VERSION 5.8 ;
BUSBITCHARS "[]" ;
DIVIDERCHAR "/" ;
UNITS
    DATABASE MICRONS 1000 ;
END UNITS

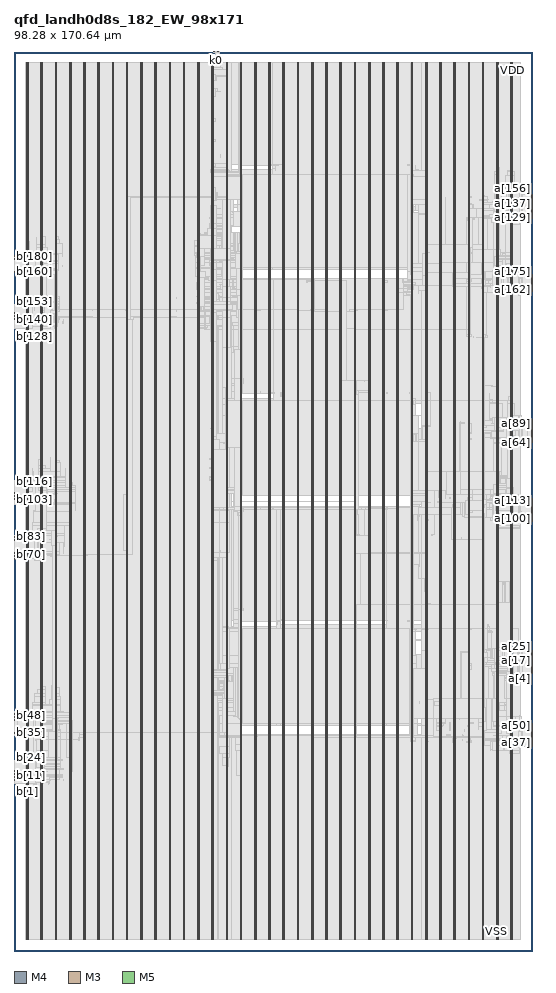
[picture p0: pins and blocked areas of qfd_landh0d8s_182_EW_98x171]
MACRO qfd_landh0d8s_182_EW_98x171
  FOREIGN qfd_landh0d8s_182_EW_98x171 0 0 ;
  CLASS BLOCK ;
  SIZE 98.28 BY 170.64 ;
  PIN a[0]
    DIRECTION INPUT ;
    USE SIGNAL ;
    PORT
      LAYER M4 ;
        RECT  98.196 52.56 98.28 52.584 ;
    END
  END a[0]
  PIN a[100]
    DIRECTION INPUT ;
    USE SIGNAL ;
    PORT
      LAYER M4 ;
        RECT  98.196 81.936 98.28 81.96 ;
    END
  END a[100]
  PIN a[101]
    DIRECTION INPUT ;
    USE SIGNAL ;
    PORT
      LAYER M4 ;
        RECT  98.196 82.08 98.28 82.104 ;
    END
  END a[101]
  PIN a[102]
    DIRECTION INPUT ;
    USE SIGNAL ;
    PORT
      LAYER M4 ;
        RECT  98.196 82.224 98.28 82.248 ;
    END
  END a[102]
  PIN a[103]
    DIRECTION INPUT ;
    USE SIGNAL ;
    PORT
      LAYER M4 ;
        RECT  98.196 82.368 98.28 82.392 ;
    END
  END a[103]
  PIN a[104]
    DIRECTION INPUT ;
    USE SIGNAL ;
    PORT
      LAYER M4 ;
        RECT  98.196 82.512 98.28 82.536 ;
    END
  END a[104]
  PIN a[105]
    DIRECTION INPUT ;
    USE SIGNAL ;
    PORT
      LAYER M4 ;
        RECT  98.196 82.656 98.28 82.68 ;
    END
  END a[105]
  PIN a[106]
    DIRECTION INPUT ;
    USE SIGNAL ;
    PORT
      LAYER M4 ;
        RECT  98.196 82.8 98.28 82.824 ;
    END
  END a[106]
  PIN a[107]
    DIRECTION INPUT ;
    USE SIGNAL ;
    PORT
      LAYER M4 ;
        RECT  98.196 82.944 98.28 82.968 ;
    END
  END a[107]
  PIN a[108]
    DIRECTION INPUT ;
    USE SIGNAL ;
    PORT
      LAYER M4 ;
        RECT  98.196 83.088 98.28 83.112 ;
    END
  END a[108]
  PIN a[109]
    DIRECTION INPUT ;
    USE SIGNAL ;
    PORT
      LAYER M4 ;
        RECT  98.196 83.232 98.28 83.256 ;
    END
  END a[109]
  PIN a[10]
    DIRECTION INPUT ;
    USE SIGNAL ;
    PORT
      LAYER M4 ;
        RECT  98.196 54 98.28 54.024 ;
    END
  END a[10]
  PIN a[110]
    DIRECTION INPUT ;
    USE SIGNAL ;
    PORT
      LAYER M4 ;
        RECT  98.196 83.376 98.28 83.4 ;
    END
  END a[110]
  PIN a[111]
    DIRECTION INPUT ;
    USE SIGNAL ;
    PORT
      LAYER M4 ;
        RECT  98.196 83.52 98.28 83.544 ;
    END
  END a[111]
  PIN a[112]
    DIRECTION INPUT ;
    USE SIGNAL ;
    PORT
      LAYER M4 ;
        RECT  98.196 83.664 98.28 83.688 ;
    END
  END a[112]
  PIN a[113]
    DIRECTION INPUT ;
    USE SIGNAL ;
    PORT
      LAYER M4 ;
        RECT  98.196 83.808 98.28 83.832 ;
    END
  END a[113]
  PIN a[114]
    DIRECTION INPUT ;
    USE SIGNAL ;
    PORT
      LAYER M4 ;
        RECT  98.196 83.952 98.28 83.976 ;
    END
  END a[114]
  PIN a[115]
    DIRECTION INPUT ;
    USE SIGNAL ;
    PORT
      LAYER M4 ;
        RECT  98.196 84.096 98.28 84.12 ;
    END
  END a[115]
  PIN a[116]
    DIRECTION INPUT ;
    USE SIGNAL ;
    PORT
      LAYER M4 ;
        RECT  98.196 84.24 98.28 84.264 ;
    END
  END a[116]
  PIN a[117]
    DIRECTION INPUT ;
    USE SIGNAL ;
    PORT
      LAYER M4 ;
        RECT  98.196 84.384 98.28 84.408 ;
    END
  END a[117]
  PIN a[118]
    DIRECTION INPUT ;
    USE SIGNAL ;
    PORT
      LAYER M4 ;
        RECT  98.196 84.528 98.28 84.552 ;
    END
  END a[118]
  PIN a[119]
    DIRECTION INPUT ;
    USE SIGNAL ;
    PORT
      LAYER M4 ;
        RECT  98.196 84.672 98.28 84.696 ;
    END
  END a[119]
  PIN a[11]
    DIRECTION INPUT ;
    USE SIGNAL ;
    PORT
      LAYER M4 ;
        RECT  98.196 54.144 98.28 54.168 ;
    END
  END a[11]
  PIN a[120]
    DIRECTION INPUT ;
    USE SIGNAL ;
    PORT
      LAYER M4 ;
        RECT  98.196 84.816 98.28 84.84 ;
    END
  END a[120]
  PIN a[121]
    DIRECTION INPUT ;
    USE SIGNAL ;
    PORT
      LAYER M4 ;
        RECT  98.196 84.96 98.28 84.984 ;
    END
  END a[121]
  PIN a[122]
    DIRECTION INPUT ;
    USE SIGNAL ;
    PORT
      LAYER M4 ;
        RECT  98.196 85.104 98.28 85.128 ;
    END
  END a[122]
  PIN a[123]
    DIRECTION INPUT ;
    USE SIGNAL ;
    PORT
      LAYER M4 ;
        RECT  98.196 85.248 98.28 85.272 ;
    END
  END a[123]
  PIN a[124]
    DIRECTION INPUT ;
    USE SIGNAL ;
    PORT
      LAYER M4 ;
        RECT  98.196 85.392 98.28 85.416 ;
    END
  END a[124]
  PIN a[125]
    DIRECTION INPUT ;
    USE SIGNAL ;
    PORT
      LAYER M4 ;
        RECT  98.196 85.536 98.28 85.56 ;
    END
  END a[125]
  PIN a[126]
    DIRECTION INPUT ;
    USE SIGNAL ;
    PORT
      LAYER M4 ;
        RECT  98.196 85.68 98.28 85.704 ;
    END
  END a[126]
  PIN a[127]
    DIRECTION INPUT ;
    USE SIGNAL ;
    PORT
      LAYER M4 ;
        RECT  98.196 85.824 98.28 85.848 ;
    END
  END a[127]
  PIN a[128]
    DIRECTION INPUT ;
    USE SIGNAL ;
    PORT
      LAYER M4 ;
        RECT  98.196 138.96 98.28 138.984 ;
    END
  END a[128]
  PIN a[129]
    DIRECTION INPUT ;
    USE SIGNAL ;
    PORT
      LAYER M4 ;
        RECT  98.196 139.104 98.28 139.128 ;
    END
  END a[129]
  PIN a[12]
    DIRECTION INPUT ;
    USE SIGNAL ;
    PORT
      LAYER M4 ;
        RECT  98.196 54.288 98.28 54.312 ;
    END
  END a[12]
  PIN a[130]
    DIRECTION INPUT ;
    USE SIGNAL ;
    PORT
      LAYER M4 ;
        RECT  98.196 139.248 98.28 139.272 ;
    END
  END a[130]
  PIN a[131]
    DIRECTION INPUT ;
    USE SIGNAL ;
    PORT
      LAYER M4 ;
        RECT  98.196 139.392 98.28 139.416 ;
    END
  END a[131]
  PIN a[132]
    DIRECTION INPUT ;
    USE SIGNAL ;
    PORT
      LAYER M4 ;
        RECT  98.196 139.536 98.28 139.56 ;
    END
  END a[132]
  PIN a[133]
    DIRECTION INPUT ;
    USE SIGNAL ;
    PORT
      LAYER M4 ;
        RECT  98.196 139.68 98.28 139.704 ;
    END
  END a[133]
  PIN a[134]
    DIRECTION INPUT ;
    USE SIGNAL ;
    PORT
      LAYER M4 ;
        RECT  98.196 139.824 98.28 139.848 ;
    END
  END a[134]
  PIN a[135]
    DIRECTION INPUT ;
    USE SIGNAL ;
    PORT
      LAYER M4 ;
        RECT  98.196 139.968 98.28 139.992 ;
    END
  END a[135]
  PIN a[136]
    DIRECTION INPUT ;
    USE SIGNAL ;
    PORT
      LAYER M4 ;
        RECT  98.196 140.112 98.28 140.136 ;
    END
  END a[136]
  PIN a[137]
    DIRECTION INPUT ;
    USE SIGNAL ;
    PORT
      LAYER M4 ;
        RECT  98.196 140.256 98.28 140.28 ;
    END
  END a[137]
  PIN a[138]
    DIRECTION INPUT ;
    USE SIGNAL ;
    PORT
      LAYER M4 ;
        RECT  98.196 140.4 98.28 140.424 ;
    END
  END a[138]
  PIN a[139]
    DIRECTION INPUT ;
    USE SIGNAL ;
    PORT
      LAYER M4 ;
        RECT  98.196 140.544 98.28 140.568 ;
    END
  END a[139]
  PIN a[13]
    DIRECTION INPUT ;
    USE SIGNAL ;
    PORT
      LAYER M4 ;
        RECT  98.196 54.432 98.28 54.456 ;
    END
  END a[13]
  PIN a[140]
    DIRECTION INPUT ;
    USE SIGNAL ;
    PORT
      LAYER M4 ;
        RECT  98.196 140.688 98.28 140.712 ;
    END
  END a[140]
  PIN a[141]
    DIRECTION INPUT ;
    USE SIGNAL ;
    PORT
      LAYER M4 ;
        RECT  98.196 140.832 98.28 140.856 ;
    END
  END a[141]
  PIN a[142]
    DIRECTION INPUT ;
    USE SIGNAL ;
    PORT
      LAYER M4 ;
        RECT  98.196 140.976 98.28 141 ;
    END
  END a[142]
  PIN a[143]
    DIRECTION INPUT ;
    USE SIGNAL ;
    PORT
      LAYER M4 ;
        RECT  98.196 141.12 98.28 141.144 ;
    END
  END a[143]
  PIN a[144]
    DIRECTION INPUT ;
    USE SIGNAL ;
    PORT
      LAYER M4 ;
        RECT  98.196 141.264 98.28 141.288 ;
    END
  END a[144]
  PIN a[145]
    DIRECTION INPUT ;
    USE SIGNAL ;
    PORT
      LAYER M4 ;
        RECT  98.196 141.408 98.28 141.432 ;
    END
  END a[145]
  PIN a[146]
    DIRECTION INPUT ;
    USE SIGNAL ;
    PORT
      LAYER M4 ;
        RECT  98.196 141.552 98.28 141.576 ;
    END
  END a[146]
  PIN a[147]
    DIRECTION INPUT ;
    USE SIGNAL ;
    PORT
      LAYER M4 ;
        RECT  98.196 141.696 98.28 141.72 ;
    END
  END a[147]
  PIN a[148]
    DIRECTION INPUT ;
    USE SIGNAL ;
    PORT
      LAYER M4 ;
        RECT  98.196 141.84 98.28 141.864 ;
    END
  END a[148]
  PIN a[149]
    DIRECTION INPUT ;
    USE SIGNAL ;
    PORT
      LAYER M4 ;
        RECT  98.196 141.984 98.28 142.008 ;
    END
  END a[149]
  PIN a[14]
    DIRECTION INPUT ;
    USE SIGNAL ;
    PORT
      LAYER M4 ;
        RECT  98.196 54.576 98.28 54.6 ;
    END
  END a[14]
  PIN a[150]
    DIRECTION INPUT ;
    USE SIGNAL ;
    PORT
      LAYER M4 ;
        RECT  98.196 142.128 98.28 142.152 ;
    END
  END a[150]
  PIN a[151]
    DIRECTION INPUT ;
    USE SIGNAL ;
    PORT
      LAYER M4 ;
        RECT  98.196 142.272 98.28 142.296 ;
    END
  END a[151]
  PIN a[152]
    DIRECTION INPUT ;
    USE SIGNAL ;
    PORT
      LAYER M4 ;
        RECT  98.196 142.416 98.28 142.44 ;
    END
  END a[152]
  PIN a[153]
    DIRECTION INPUT ;
    USE SIGNAL ;
    PORT
      LAYER M4 ;
        RECT  98.196 142.56 98.28 142.584 ;
    END
  END a[153]
  PIN a[154]
    DIRECTION INPUT ;
    USE SIGNAL ;
    PORT
      LAYER M4 ;
        RECT  98.196 142.704 98.28 142.728 ;
    END
  END a[154]
  PIN a[155]
    DIRECTION INPUT ;
    USE SIGNAL ;
    PORT
      LAYER M4 ;
        RECT  98.196 142.848 98.28 142.872 ;
    END
  END a[155]
  PIN a[156]
    DIRECTION INPUT ;
    USE SIGNAL ;
    PORT
      LAYER M4 ;
        RECT  98.196 142.992 98.28 143.016 ;
    END
  END a[156]
  PIN a[157]
    DIRECTION INPUT ;
    USE SIGNAL ;
    PORT
      LAYER M4 ;
        RECT  98.196 143.136 98.28 143.16 ;
    END
  END a[157]
  PIN a[158]
    DIRECTION INPUT ;
    USE SIGNAL ;
    PORT
      LAYER M4 ;
        RECT  98.196 143.28 98.28 143.304 ;
    END
  END a[158]
  PIN a[159]
    DIRECTION INPUT ;
    USE SIGNAL ;
    PORT
      LAYER M4 ;
        RECT  98.196 143.424 98.28 143.448 ;
    END
  END a[159]
  PIN a[15]
    DIRECTION INPUT ;
    USE SIGNAL ;
    PORT
      LAYER M4 ;
        RECT  98.196 54.72 98.28 54.744 ;
    END
  END a[15]
  PIN a[160]
    DIRECTION INPUT ;
    USE SIGNAL ;
    PORT
      LAYER M4 ;
        RECT  98.196 125.136 98.28 125.16 ;
    END
  END a[160]
  PIN a[161]
    DIRECTION INPUT ;
    USE SIGNAL ;
    PORT
      LAYER M4 ;
        RECT  98.196 125.28 98.28 125.304 ;
    END
  END a[161]
  PIN a[162]
    DIRECTION INPUT ;
    USE SIGNAL ;
    PORT
      LAYER M4 ;
        RECT  98.196 125.424 98.28 125.448 ;
    END
  END a[162]
  PIN a[163]
    DIRECTION INPUT ;
    USE SIGNAL ;
    PORT
      LAYER M4 ;
        RECT  98.196 125.568 98.28 125.592 ;
    END
  END a[163]
  PIN a[164]
    DIRECTION INPUT ;
    USE SIGNAL ;
    PORT
      LAYER M4 ;
        RECT  98.196 125.712 98.28 125.736 ;
    END
  END a[164]
  PIN a[165]
    DIRECTION INPUT ;
    USE SIGNAL ;
    PORT
      LAYER M4 ;
        RECT  98.196 125.856 98.28 125.88 ;
    END
  END a[165]
  PIN a[166]
    DIRECTION INPUT ;
    USE SIGNAL ;
    PORT
      LAYER M4 ;
        RECT  98.196 126 98.28 126.024 ;
    END
  END a[166]
  PIN a[167]
    DIRECTION INPUT ;
    USE SIGNAL ;
    PORT
      LAYER M4 ;
        RECT  98.196 126.144 98.28 126.168 ;
    END
  END a[167]
  PIN a[168]
    DIRECTION INPUT ;
    USE SIGNAL ;
    PORT
      LAYER M4 ;
        RECT  98.196 126.288 98.28 126.312 ;
    END
  END a[168]
  PIN a[169]
    DIRECTION INPUT ;
    USE SIGNAL ;
    PORT
      LAYER M4 ;
        RECT  98.196 126.432 98.28 126.456 ;
    END
  END a[169]
  PIN a[16]
    DIRECTION INPUT ;
    USE SIGNAL ;
    PORT
      LAYER M4 ;
        RECT  98.196 54.864 98.28 54.888 ;
    END
  END a[16]
  PIN a[170]
    DIRECTION INPUT ;
    USE SIGNAL ;
    PORT
      LAYER M4 ;
        RECT  98.196 126.576 98.28 126.6 ;
    END
  END a[170]
  PIN a[171]
    DIRECTION INPUT ;
    USE SIGNAL ;
    PORT
      LAYER M4 ;
        RECT  98.196 126.72 98.28 126.744 ;
    END
  END a[171]
  PIN a[172]
    DIRECTION INPUT ;
    USE SIGNAL ;
    PORT
      LAYER M4 ;
        RECT  98.196 126.864 98.28 126.888 ;
    END
  END a[172]
  PIN a[173]
    DIRECTION INPUT ;
    USE SIGNAL ;
    PORT
      LAYER M4 ;
        RECT  98.196 127.008 98.28 127.032 ;
    END
  END a[173]
  PIN a[174]
    DIRECTION INPUT ;
    USE SIGNAL ;
    PORT
      LAYER M4 ;
        RECT  98.196 127.152 98.28 127.176 ;
    END
  END a[174]
  PIN a[175]
    DIRECTION INPUT ;
    USE SIGNAL ;
    PORT
      LAYER M4 ;
        RECT  98.196 127.296 98.28 127.32 ;
    END
  END a[175]
  PIN a[176]
    DIRECTION INPUT ;
    USE SIGNAL ;
    PORT
      LAYER M4 ;
        RECT  98.196 127.44 98.28 127.464 ;
    END
  END a[176]
  PIN a[177]
    DIRECTION INPUT ;
    USE SIGNAL ;
    PORT
      LAYER M4 ;
        RECT  98.196 127.584 98.28 127.608 ;
    END
  END a[177]
  PIN a[178]
    DIRECTION INPUT ;
    USE SIGNAL ;
    PORT
      LAYER M4 ;
        RECT  98.196 127.728 98.28 127.752 ;
    END
  END a[178]
  PIN a[179]
    DIRECTION INPUT ;
    USE SIGNAL ;
    PORT
      LAYER M4 ;
        RECT  98.196 127.872 98.28 127.896 ;
    END
  END a[179]
  PIN a[17]
    DIRECTION INPUT ;
    USE SIGNAL ;
    PORT
      LAYER M4 ;
        RECT  98.196 55.008 98.28 55.032 ;
    END
  END a[17]
  PIN a[180]
    DIRECTION INPUT ;
    USE SIGNAL ;
    PORT
      LAYER M4 ;
        RECT  98.196 128.016 98.28 128.04 ;
    END
  END a[180]
  PIN a[181]
    DIRECTION INPUT ;
    USE SIGNAL ;
    PORT
      LAYER M4 ;
        RECT  98.196 128.16 98.28 128.184 ;
    END
  END a[181]
  PIN a[18]
    DIRECTION INPUT ;
    USE SIGNAL ;
    PORT
      LAYER M4 ;
        RECT  98.196 55.152 98.28 55.176 ;
    END
  END a[18]
  PIN a[19]
    DIRECTION INPUT ;
    USE SIGNAL ;
    PORT
      LAYER M4 ;
        RECT  98.196 55.296 98.28 55.32 ;
    END
  END a[19]
  PIN a[1]
    DIRECTION INPUT ;
    USE SIGNAL ;
    PORT
      LAYER M4 ;
        RECT  98.196 52.704 98.28 52.728 ;
    END
  END a[1]
  PIN a[20]
    DIRECTION INPUT ;
    USE SIGNAL ;
    PORT
      LAYER M4 ;
        RECT  98.196 55.44 98.28 55.464 ;
    END
  END a[20]
  PIN a[21]
    DIRECTION INPUT ;
    USE SIGNAL ;
    PORT
      LAYER M4 ;
        RECT  98.196 55.584 98.28 55.608 ;
    END
  END a[21]
  PIN a[22]
    DIRECTION INPUT ;
    USE SIGNAL ;
    PORT
      LAYER M4 ;
        RECT  98.196 55.728 98.28 55.752 ;
    END
  END a[22]
  PIN a[23]
    DIRECTION INPUT ;
    USE SIGNAL ;
    PORT
      LAYER M4 ;
        RECT  98.196 55.872 98.28 55.896 ;
    END
  END a[23]
  PIN a[24]
    DIRECTION INPUT ;
    USE SIGNAL ;
    PORT
      LAYER M4 ;
        RECT  98.196 56.016 98.28 56.04 ;
    END
  END a[24]
  PIN a[25]
    DIRECTION INPUT ;
    USE SIGNAL ;
    PORT
      LAYER M4 ;
        RECT  98.196 56.16 98.28 56.184 ;
    END
  END a[25]
  PIN a[26]
    DIRECTION INPUT ;
    USE SIGNAL ;
    PORT
      LAYER M4 ;
        RECT  98.196 56.304 98.28 56.328 ;
    END
  END a[26]
  PIN a[27]
    DIRECTION INPUT ;
    USE SIGNAL ;
    PORT
      LAYER M4 ;
        RECT  98.196 56.448 98.28 56.472 ;
    END
  END a[27]
  PIN a[28]
    DIRECTION INPUT ;
    USE SIGNAL ;
    PORT
      LAYER M4 ;
        RECT  98.196 56.592 98.28 56.616 ;
    END
  END a[28]
  PIN a[29]
    DIRECTION INPUT ;
    USE SIGNAL ;
    PORT
      LAYER M4 ;
        RECT  98.196 56.736 98.28 56.76 ;
    END
  END a[29]
  PIN a[2]
    DIRECTION INPUT ;
    USE SIGNAL ;
    PORT
      LAYER M4 ;
        RECT  98.196 52.848 98.28 52.872 ;
    END
  END a[2]
  PIN a[30]
    DIRECTION INPUT ;
    USE SIGNAL ;
    PORT
      LAYER M4 ;
        RECT  98.196 56.88 98.28 56.904 ;
    END
  END a[30]
  PIN a[31]
    DIRECTION INPUT ;
    USE SIGNAL ;
    PORT
      LAYER M4 ;
        RECT  98.196 57.024 98.28 57.048 ;
    END
  END a[31]
  PIN a[32]
    DIRECTION INPUT ;
    USE SIGNAL ;
    PORT
      LAYER M4 ;
        RECT  98.196 38.736 98.28 38.76 ;
    END
  END a[32]
  PIN a[33]
    DIRECTION INPUT ;
    USE SIGNAL ;
    PORT
      LAYER M4 ;
        RECT  98.196 38.88 98.28 38.904 ;
    END
  END a[33]
  PIN a[34]
    DIRECTION INPUT ;
    USE SIGNAL ;
    PORT
      LAYER M4 ;
        RECT  98.196 39.024 98.28 39.048 ;
    END
  END a[34]
  PIN a[35]
    DIRECTION INPUT ;
    USE SIGNAL ;
    PORT
      LAYER M4 ;
        RECT  98.196 39.168 98.28 39.192 ;
    END
  END a[35]
  PIN a[36]
    DIRECTION INPUT ;
    USE SIGNAL ;
    PORT
      LAYER M4 ;
        RECT  98.196 39.312 98.28 39.336 ;
    END
  END a[36]
  PIN a[37]
    DIRECTION INPUT ;
    USE SIGNAL ;
    PORT
      LAYER M4 ;
        RECT  98.196 39.456 98.28 39.48 ;
    END
  END a[37]
  PIN a[38]
    DIRECTION INPUT ;
    USE SIGNAL ;
    PORT
      LAYER M4 ;
        RECT  98.196 39.6 98.28 39.624 ;
    END
  END a[38]
  PIN a[39]
    DIRECTION INPUT ;
    USE SIGNAL ;
    PORT
      LAYER M4 ;
        RECT  98.196 39.744 98.28 39.768 ;
    END
  END a[39]
  PIN a[3]
    DIRECTION INPUT ;
    USE SIGNAL ;
    PORT
      LAYER M4 ;
        RECT  98.196 52.992 98.28 53.016 ;
    END
  END a[3]
  PIN a[40]
    DIRECTION INPUT ;
    USE SIGNAL ;
    PORT
      LAYER M4 ;
        RECT  98.196 39.888 98.28 39.912 ;
    END
  END a[40]
  PIN a[41]
    DIRECTION INPUT ;
    USE SIGNAL ;
    PORT
      LAYER M4 ;
        RECT  98.196 40.032 98.28 40.056 ;
    END
  END a[41]
  PIN a[42]
    DIRECTION INPUT ;
    USE SIGNAL ;
    PORT
      LAYER M4 ;
        RECT  98.196 40.176 98.28 40.2 ;
    END
  END a[42]
  PIN a[43]
    DIRECTION INPUT ;
    USE SIGNAL ;
    PORT
      LAYER M4 ;
        RECT  98.196 40.32 98.28 40.344 ;
    END
  END a[43]
  PIN a[44]
    DIRECTION INPUT ;
    USE SIGNAL ;
    PORT
      LAYER M4 ;
        RECT  98.196 40.464 98.28 40.488 ;
    END
  END a[44]
  PIN a[45]
    DIRECTION INPUT ;
    USE SIGNAL ;
    PORT
      LAYER M4 ;
        RECT  98.196 40.608 98.28 40.632 ;
    END
  END a[45]
  PIN a[46]
    DIRECTION INPUT ;
    USE SIGNAL ;
    PORT
      LAYER M4 ;
        RECT  98.196 40.752 98.28 40.776 ;
    END
  END a[46]
  PIN a[47]
    DIRECTION INPUT ;
    USE SIGNAL ;
    PORT
      LAYER M4 ;
        RECT  98.196 40.896 98.28 40.92 ;
    END
  END a[47]
  PIN a[48]
    DIRECTION INPUT ;
    USE SIGNAL ;
    PORT
      LAYER M4 ;
        RECT  98.196 41.04 98.28 41.064 ;
    END
  END a[48]
  PIN a[49]
    DIRECTION INPUT ;
    USE SIGNAL ;
    PORT
      LAYER M4 ;
        RECT  98.196 41.184 98.28 41.208 ;
    END
  END a[49]
  PIN a[4]
    DIRECTION INPUT ;
    USE SIGNAL ;
    PORT
      LAYER M4 ;
        RECT  98.196 53.136 98.28 53.16 ;
    END
  END a[4]
  PIN a[50]
    DIRECTION INPUT ;
    USE SIGNAL ;
    PORT
      LAYER M4 ;
        RECT  98.196 41.328 98.28 41.352 ;
    END
  END a[50]
  PIN a[51]
    DIRECTION INPUT ;
    USE SIGNAL ;
    PORT
      LAYER M4 ;
        RECT  98.196 41.472 98.28 41.496 ;
    END
  END a[51]
  PIN a[52]
    DIRECTION INPUT ;
    USE SIGNAL ;
    PORT
      LAYER M4 ;
        RECT  98.196 41.616 98.28 41.64 ;
    END
  END a[52]
  PIN a[53]
    DIRECTION INPUT ;
    USE SIGNAL ;
    PORT
      LAYER M4 ;
        RECT  98.196 41.76 98.28 41.784 ;
    END
  END a[53]
  PIN a[54]
    DIRECTION INPUT ;
    USE SIGNAL ;
    PORT
      LAYER M4 ;
        RECT  98.196 41.904 98.28 41.928 ;
    END
  END a[54]
  PIN a[55]
    DIRECTION INPUT ;
    USE SIGNAL ;
    PORT
      LAYER M4 ;
        RECT  98.196 42.048 98.28 42.072 ;
    END
  END a[55]
  PIN a[56]
    DIRECTION INPUT ;
    USE SIGNAL ;
    PORT
      LAYER M4 ;
        RECT  98.196 42.192 98.28 42.216 ;
    END
  END a[56]
  PIN a[57]
    DIRECTION INPUT ;
    USE SIGNAL ;
    PORT
      LAYER M4 ;
        RECT  98.196 42.336 98.28 42.36 ;
    END
  END a[57]
  PIN a[58]
    DIRECTION INPUT ;
    USE SIGNAL ;
    PORT
      LAYER M4 ;
        RECT  98.196 42.48 98.28 42.504 ;
    END
  END a[58]
  PIN a[59]
    DIRECTION INPUT ;
    USE SIGNAL ;
    PORT
      LAYER M4 ;
        RECT  98.196 42.624 98.28 42.648 ;
    END
  END a[59]
  PIN a[5]
    DIRECTION INPUT ;
    USE SIGNAL ;
    PORT
      LAYER M4 ;
        RECT  98.196 53.28 98.28 53.304 ;
    END
  END a[5]
  PIN a[60]
    DIRECTION INPUT ;
    USE SIGNAL ;
    PORT
      LAYER M4 ;
        RECT  98.196 42.768 98.28 42.792 ;
    END
  END a[60]
  PIN a[61]
    DIRECTION INPUT ;
    USE SIGNAL ;
    PORT
      LAYER M4 ;
        RECT  98.196 42.912 98.28 42.936 ;
    END
  END a[61]
  PIN a[62]
    DIRECTION INPUT ;
    USE SIGNAL ;
    PORT
      LAYER M4 ;
        RECT  98.196 43.056 98.28 43.08 ;
    END
  END a[62]
  PIN a[63]
    DIRECTION INPUT ;
    USE SIGNAL ;
    PORT
      LAYER M4 ;
        RECT  98.196 43.2 98.28 43.224 ;
    END
  END a[63]
  PIN a[64]
    DIRECTION INPUT ;
    USE SIGNAL ;
    PORT
      LAYER M4 ;
        RECT  98.196 96.336 98.28 96.36 ;
    END
  END a[64]
  PIN a[65]
    DIRECTION INPUT ;
    USE SIGNAL ;
    PORT
      LAYER M4 ;
        RECT  98.196 96.48 98.28 96.504 ;
    END
  END a[65]
  PIN a[66]
    DIRECTION INPUT ;
    USE SIGNAL ;
    PORT
      LAYER M4 ;
        RECT  98.196 96.624 98.28 96.648 ;
    END
  END a[66]
  PIN a[67]
    DIRECTION INPUT ;
    USE SIGNAL ;
    PORT
      LAYER M4 ;
        RECT  98.196 96.768 98.28 96.792 ;
    END
  END a[67]
  PIN a[68]
    DIRECTION INPUT ;
    USE SIGNAL ;
    PORT
      LAYER M4 ;
        RECT  98.196 96.912 98.28 96.936 ;
    END
  END a[68]
  PIN a[69]
    DIRECTION INPUT ;
    USE SIGNAL ;
    PORT
      LAYER M4 ;
        RECT  98.196 97.056 98.28 97.08 ;
    END
  END a[69]
  PIN a[6]
    DIRECTION INPUT ;
    USE SIGNAL ;
    PORT
      LAYER M4 ;
        RECT  98.196 53.424 98.28 53.448 ;
    END
  END a[6]
  PIN a[70]
    DIRECTION INPUT ;
    USE SIGNAL ;
    PORT
      LAYER M4 ;
        RECT  98.196 97.2 98.28 97.224 ;
    END
  END a[70]
  PIN a[71]
    DIRECTION INPUT ;
    USE SIGNAL ;
    PORT
      LAYER M4 ;
        RECT  98.196 97.344 98.28 97.368 ;
    END
  END a[71]
  PIN a[72]
    DIRECTION INPUT ;
    USE SIGNAL ;
    PORT
      LAYER M4 ;
        RECT  98.196 97.488 98.28 97.512 ;
    END
  END a[72]
  PIN a[73]
    DIRECTION INPUT ;
    USE SIGNAL ;
    PORT
      LAYER M4 ;
        RECT  98.196 97.632 98.28 97.656 ;
    END
  END a[73]
  PIN a[74]
    DIRECTION INPUT ;
    USE SIGNAL ;
    PORT
      LAYER M4 ;
        RECT  98.196 97.776 98.28 97.8 ;
    END
  END a[74]
  PIN a[75]
    DIRECTION INPUT ;
    USE SIGNAL ;
    PORT
      LAYER M4 ;
        RECT  98.196 97.92 98.28 97.944 ;
    END
  END a[75]
  PIN a[76]
    DIRECTION INPUT ;
    USE SIGNAL ;
    PORT
      LAYER M4 ;
        RECT  98.196 98.064 98.28 98.088 ;
    END
  END a[76]
  PIN a[77]
    DIRECTION INPUT ;
    USE SIGNAL ;
    PORT
      LAYER M4 ;
        RECT  98.196 98.208 98.28 98.232 ;
    END
  END a[77]
  PIN a[78]
    DIRECTION INPUT ;
    USE SIGNAL ;
    PORT
      LAYER M4 ;
        RECT  98.196 98.352 98.28 98.376 ;
    END
  END a[78]
  PIN a[79]
    DIRECTION INPUT ;
    USE SIGNAL ;
    PORT
      LAYER M4 ;
        RECT  98.196 98.496 98.28 98.52 ;
    END
  END a[79]
  PIN a[7]
    DIRECTION INPUT ;
    USE SIGNAL ;
    PORT
      LAYER M4 ;
        RECT  98.196 53.568 98.28 53.592 ;
    END
  END a[7]
  PIN a[80]
    DIRECTION INPUT ;
    USE SIGNAL ;
    PORT
      LAYER M4 ;
        RECT  98.196 98.64 98.28 98.664 ;
    END
  END a[80]
  PIN a[81]
    DIRECTION INPUT ;
    USE SIGNAL ;
    PORT
      LAYER M4 ;
        RECT  98.196 98.784 98.28 98.808 ;
    END
  END a[81]
  PIN a[82]
    DIRECTION INPUT ;
    USE SIGNAL ;
    PORT
      LAYER M4 ;
        RECT  98.196 98.928 98.28 98.952 ;
    END
  END a[82]
  PIN a[83]
    DIRECTION INPUT ;
    USE SIGNAL ;
    PORT
      LAYER M4 ;
        RECT  98.196 99.072 98.28 99.096 ;
    END
  END a[83]
  PIN a[84]
    DIRECTION INPUT ;
    USE SIGNAL ;
    PORT
      LAYER M4 ;
        RECT  98.196 99.216 98.28 99.24 ;
    END
  END a[84]
  PIN a[85]
    DIRECTION INPUT ;
    USE SIGNAL ;
    PORT
      LAYER M4 ;
        RECT  98.196 99.36 98.28 99.384 ;
    END
  END a[85]
  PIN a[86]
    DIRECTION INPUT ;
    USE SIGNAL ;
    PORT
      LAYER M4 ;
        RECT  98.196 99.504 98.28 99.528 ;
    END
  END a[86]
  PIN a[87]
    DIRECTION INPUT ;
    USE SIGNAL ;
    PORT
      LAYER M4 ;
        RECT  98.196 99.648 98.28 99.672 ;
    END
  END a[87]
  PIN a[88]
    DIRECTION INPUT ;
    USE SIGNAL ;
    PORT
      LAYER M4 ;
        RECT  98.196 99.792 98.28 99.816 ;
    END
  END a[88]
  PIN a[89]
    DIRECTION INPUT ;
    USE SIGNAL ;
    PORT
      LAYER M4 ;
        RECT  98.196 99.936 98.28 99.96 ;
    END
  END a[89]
  PIN a[8]
    DIRECTION INPUT ;
    USE SIGNAL ;
    PORT
      LAYER M4 ;
        RECT  98.196 53.712 98.28 53.736 ;
    END
  END a[8]
  PIN a[90]
    DIRECTION INPUT ;
    USE SIGNAL ;
    PORT
      LAYER M4 ;
        RECT  98.196 100.08 98.28 100.104 ;
    END
  END a[90]
  PIN a[91]
    DIRECTION INPUT ;
    USE SIGNAL ;
    PORT
      LAYER M4 ;
        RECT  98.196 100.224 98.28 100.248 ;
    END
  END a[91]
  PIN a[92]
    DIRECTION INPUT ;
    USE SIGNAL ;
    PORT
      LAYER M4 ;
        RECT  98.196 100.368 98.28 100.392 ;
    END
  END a[92]
  PIN a[93]
    DIRECTION INPUT ;
    USE SIGNAL ;
    PORT
      LAYER M4 ;
        RECT  98.196 100.512 98.28 100.536 ;
    END
  END a[93]
  PIN a[94]
    DIRECTION INPUT ;
    USE SIGNAL ;
    PORT
      LAYER M4 ;
        RECT  98.196 100.656 98.28 100.68 ;
    END
  END a[94]
  PIN a[95]
    DIRECTION INPUT ;
    USE SIGNAL ;
    PORT
      LAYER M4 ;
        RECT  98.196 100.8 98.28 100.824 ;
    END
  END a[95]
  PIN a[96]
    DIRECTION INPUT ;
    USE SIGNAL ;
    PORT
      LAYER M4 ;
        RECT  98.196 81.36 98.28 81.384 ;
    END
  END a[96]
  PIN a[97]
    DIRECTION INPUT ;
    USE SIGNAL ;
    PORT
      LAYER M4 ;
        RECT  98.196 81.504 98.28 81.528 ;
    END
  END a[97]
  PIN a[98]
    DIRECTION INPUT ;
    USE SIGNAL ;
    PORT
      LAYER M4 ;
        RECT  98.196 81.648 98.28 81.672 ;
    END
  END a[98]
  PIN a[99]
    DIRECTION INPUT ;
    USE SIGNAL ;
    PORT
      LAYER M4 ;
        RECT  98.196 81.792 98.28 81.816 ;
    END
  END a[99]
  PIN a[9]
    DIRECTION INPUT ;
    USE SIGNAL ;
    PORT
      LAYER M4 ;
        RECT  98.196 53.856 98.28 53.88 ;
    END
  END a[9]
  PIN b[0]
    DIRECTION OUTPUT ;
    USE SIGNAL ;
    PORT
      LAYER M4 ;
        RECT  0 31.68 0.084 31.704 ;
    END
  END b[0]
  PIN b[100]
    DIRECTION OUTPUT ;
    USE SIGNAL ;
    PORT
      LAYER M4 ;
        RECT  0 85.248 0.084 85.272 ;
    END
  END b[100]
  PIN b[101]
    DIRECTION OUTPUT ;
    USE SIGNAL ;
    PORT
      LAYER M4 ;
        RECT  0 85.392 0.084 85.416 ;
    END
  END b[101]
  PIN b[102]
    DIRECTION OUTPUT ;
    USE SIGNAL ;
    PORT
      LAYER M4 ;
        RECT  0 85.536 0.084 85.56 ;
    END
  END b[102]
  PIN b[103]
    DIRECTION OUTPUT ;
    USE SIGNAL ;
    PORT
      LAYER M4 ;
        RECT  0 85.68 0.084 85.704 ;
    END
  END b[103]
  PIN b[104]
    DIRECTION OUTPUT ;
    USE SIGNAL ;
    PORT
      LAYER M4 ;
        RECT  0 85.824 0.084 85.848 ;
    END
  END b[104]
  PIN b[105]
    DIRECTION OUTPUT ;
    USE SIGNAL ;
    PORT
      LAYER M4 ;
        RECT  0 85.968 0.084 85.992 ;
    END
  END b[105]
  PIN b[106]
    DIRECTION OUTPUT ;
    USE SIGNAL ;
    PORT
      LAYER M4 ;
        RECT  0 86.112 0.084 86.136 ;
    END
  END b[106]
  PIN b[107]
    DIRECTION OUTPUT ;
    USE SIGNAL ;
    PORT
      LAYER M4 ;
        RECT  0 86.256 0.084 86.28 ;
    END
  END b[107]
  PIN b[108]
    DIRECTION OUTPUT ;
    USE SIGNAL ;
    PORT
      LAYER M4 ;
        RECT  0 86.4 0.084 86.424 ;
    END
  END b[108]
  PIN b[109]
    DIRECTION OUTPUT ;
    USE SIGNAL ;
    PORT
      LAYER M4 ;
        RECT  0 86.544 0.084 86.568 ;
    END
  END b[109]
  PIN b[10]
    DIRECTION OUTPUT ;
    USE SIGNAL ;
    PORT
      LAYER M4 ;
        RECT  0 33.12 0.084 33.144 ;
    END
  END b[10]
  PIN b[110]
    DIRECTION OUTPUT ;
    USE SIGNAL ;
    PORT
      LAYER M4 ;
        RECT  0 86.688 0.084 86.712 ;
    END
  END b[110]
  PIN b[111]
    DIRECTION OUTPUT ;
    USE SIGNAL ;
    PORT
      LAYER M4 ;
        RECT  0 86.832 0.084 86.856 ;
    END
  END b[111]
  PIN b[112]
    DIRECTION OUTPUT ;
    USE SIGNAL ;
    PORT
      LAYER M4 ;
        RECT  0 86.976 0.084 87 ;
    END
  END b[112]
  PIN b[113]
    DIRECTION OUTPUT ;
    USE SIGNAL ;
    PORT
      LAYER M4 ;
        RECT  0 87.12 0.084 87.144 ;
    END
  END b[113]
  PIN b[114]
    DIRECTION OUTPUT ;
    USE SIGNAL ;
    PORT
      LAYER M4 ;
        RECT  0 87.264 0.084 87.288 ;
    END
  END b[114]
  PIN b[115]
    DIRECTION OUTPUT ;
    USE SIGNAL ;
    PORT
      LAYER M4 ;
        RECT  0 87.408 0.084 87.432 ;
    END
  END b[115]
  PIN b[116]
    DIRECTION OUTPUT ;
    USE SIGNAL ;
    PORT
      LAYER M4 ;
        RECT  0 87.552 0.084 87.576 ;
    END
  END b[116]
  PIN b[117]
    DIRECTION OUTPUT ;
    USE SIGNAL ;
    PORT
      LAYER M4 ;
        RECT  0 87.696 0.084 87.72 ;
    END
  END b[117]
  PIN b[118]
    DIRECTION OUTPUT ;
    USE SIGNAL ;
    PORT
      LAYER M4 ;
        RECT  0 87.84 0.084 87.864 ;
    END
  END b[118]
  PIN b[119]
    DIRECTION OUTPUT ;
    USE SIGNAL ;
    PORT
      LAYER M4 ;
        RECT  0 87.984 0.084 88.008 ;
    END
  END b[119]
  PIN b[11]
    DIRECTION OUTPUT ;
    USE SIGNAL ;
    PORT
      LAYER M4 ;
        RECT  0 33.264 0.084 33.288 ;
    END
  END b[11]
  PIN b[120]
    DIRECTION OUTPUT ;
    USE SIGNAL ;
    PORT
      LAYER M4 ;
        RECT  0 88.128 0.084 88.152 ;
    END
  END b[120]
  PIN b[121]
    DIRECTION OUTPUT ;
    USE SIGNAL ;
    PORT
      LAYER M4 ;
        RECT  0 88.272 0.084 88.296 ;
    END
  END b[121]
  PIN b[122]
    DIRECTION OUTPUT ;
    USE SIGNAL ;
    PORT
      LAYER M4 ;
        RECT  0 88.416 0.084 88.44 ;
    END
  END b[122]
  PIN b[123]
    DIRECTION OUTPUT ;
    USE SIGNAL ;
    PORT
      LAYER M4 ;
        RECT  0 88.56 0.084 88.584 ;
    END
  END b[123]
  PIN b[124]
    DIRECTION OUTPUT ;
    USE SIGNAL ;
    PORT
      LAYER M4 ;
        RECT  0 88.704 0.084 88.728 ;
    END
  END b[124]
  PIN b[125]
    DIRECTION OUTPUT ;
    USE SIGNAL ;
    PORT
      LAYER M4 ;
        RECT  0 88.848 0.084 88.872 ;
    END
  END b[125]
  PIN b[126]
    DIRECTION OUTPUT ;
    USE SIGNAL ;
    PORT
      LAYER M4 ;
        RECT  0 88.992 0.084 89.016 ;
    END
  END b[126]
  PIN b[127]
    DIRECTION OUTPUT ;
    USE SIGNAL ;
    PORT
      LAYER M4 ;
        RECT  0 89.136 0.084 89.16 ;
    END
  END b[127]
  PIN b[128]
    DIRECTION OUTPUT ;
    USE SIGNAL ;
    PORT
      LAYER M4 ;
        RECT  0 118.08 0.084 118.104 ;
    END
  END b[128]
  PIN b[129]
    DIRECTION OUTPUT ;
    USE SIGNAL ;
    PORT
      LAYER M4 ;
        RECT  0 118.224 0.084 118.248 ;
    END
  END b[129]
  PIN b[12]
    DIRECTION OUTPUT ;
    USE SIGNAL ;
    PORT
      LAYER M4 ;
        RECT  0 33.408 0.084 33.432 ;
    END
  END b[12]
  PIN b[130]
    DIRECTION OUTPUT ;
    USE SIGNAL ;
    PORT
      LAYER M4 ;
        RECT  0 118.368 0.084 118.392 ;
    END
  END b[130]
  PIN b[131]
    DIRECTION OUTPUT ;
    USE SIGNAL ;
    PORT
      LAYER M4 ;
        RECT  0 118.512 0.084 118.536 ;
    END
  END b[131]
  PIN b[132]
    DIRECTION OUTPUT ;
    USE SIGNAL ;
    PORT
      LAYER M4 ;
        RECT  0 118.656 0.084 118.68 ;
    END
  END b[132]
  PIN b[133]
    DIRECTION OUTPUT ;
    USE SIGNAL ;
    PORT
      LAYER M4 ;
        RECT  0 118.8 0.084 118.824 ;
    END
  END b[133]
  PIN b[134]
    DIRECTION OUTPUT ;
    USE SIGNAL ;
    PORT
      LAYER M4 ;
        RECT  0 118.944 0.084 118.968 ;
    END
  END b[134]
  PIN b[135]
    DIRECTION OUTPUT ;
    USE SIGNAL ;
    PORT
      LAYER M4 ;
        RECT  0 119.088 0.084 119.112 ;
    END
  END b[135]
  PIN b[136]
    DIRECTION OUTPUT ;
    USE SIGNAL ;
    PORT
      LAYER M4 ;
        RECT  0 119.232 0.084 119.256 ;
    END
  END b[136]
  PIN b[137]
    DIRECTION OUTPUT ;
    USE SIGNAL ;
    PORT
      LAYER M4 ;
        RECT  0 119.376 0.084 119.4 ;
    END
  END b[137]
  PIN b[138]
    DIRECTION OUTPUT ;
    USE SIGNAL ;
    PORT
      LAYER M4 ;
        RECT  0 119.52 0.084 119.544 ;
    END
  END b[138]
  PIN b[139]
    DIRECTION OUTPUT ;
    USE SIGNAL ;
    PORT
      LAYER M4 ;
        RECT  0 119.664 0.084 119.688 ;
    END
  END b[139]
  PIN b[13]
    DIRECTION OUTPUT ;
    USE SIGNAL ;
    PORT
      LAYER M4 ;
        RECT  0 33.552 0.084 33.576 ;
    END
  END b[13]
  PIN b[140]
    DIRECTION OUTPUT ;
    USE SIGNAL ;
    PORT
      LAYER M4 ;
        RECT  0 119.808 0.084 119.832 ;
    END
  END b[140]
  PIN b[141]
    DIRECTION OUTPUT ;
    USE SIGNAL ;
    PORT
      LAYER M4 ;
        RECT  0 119.952 0.084 119.976 ;
    END
  END b[141]
  PIN b[142]
    DIRECTION OUTPUT ;
    USE SIGNAL ;
    PORT
      LAYER M4 ;
        RECT  0 120.096 0.084 120.12 ;
    END
  END b[142]
  PIN b[143]
    DIRECTION OUTPUT ;
    USE SIGNAL ;
    PORT
      LAYER M4 ;
        RECT  0 120.24 0.084 120.264 ;
    END
  END b[143]
  PIN b[144]
    DIRECTION OUTPUT ;
    USE SIGNAL ;
    PORT
      LAYER M4 ;
        RECT  0 120.384 0.084 120.408 ;
    END
  END b[144]
  PIN b[145]
    DIRECTION OUTPUT ;
    USE SIGNAL ;
    PORT
      LAYER M4 ;
        RECT  0 120.528 0.084 120.552 ;
    END
  END b[145]
  PIN b[146]
    DIRECTION OUTPUT ;
    USE SIGNAL ;
    PORT
      LAYER M4 ;
        RECT  0 120.672 0.084 120.696 ;
    END
  END b[146]
  PIN b[147]
    DIRECTION OUTPUT ;
    USE SIGNAL ;
    PORT
      LAYER M4 ;
        RECT  0 120.816 0.084 120.84 ;
    END
  END b[147]
  PIN b[148]
    DIRECTION OUTPUT ;
    USE SIGNAL ;
    PORT
      LAYER M4 ;
        RECT  0 120.96 0.084 120.984 ;
    END
  END b[148]
  PIN b[149]
    DIRECTION OUTPUT ;
    USE SIGNAL ;
    PORT
      LAYER M4 ;
        RECT  0 121.104 0.084 121.128 ;
    END
  END b[149]
  PIN b[14]
    DIRECTION OUTPUT ;
    USE SIGNAL ;
    PORT
      LAYER M4 ;
        RECT  0 33.696 0.084 33.72 ;
    END
  END b[14]
  PIN b[150]
    DIRECTION OUTPUT ;
    USE SIGNAL ;
    PORT
      LAYER M4 ;
        RECT  0 121.248 0.084 121.272 ;
    END
  END b[150]
  PIN b[151]
    DIRECTION OUTPUT ;
    USE SIGNAL ;
    PORT
      LAYER M4 ;
        RECT  0 121.392 0.084 121.416 ;
    END
  END b[151]
  PIN b[152]
    DIRECTION OUTPUT ;
    USE SIGNAL ;
    PORT
      LAYER M4 ;
        RECT  0 121.536 0.084 121.56 ;
    END
  END b[152]
  PIN b[153]
    DIRECTION OUTPUT ;
    USE SIGNAL ;
    PORT
      LAYER M4 ;
        RECT  0 121.68 0.084 121.704 ;
    END
  END b[153]
  PIN b[154]
    DIRECTION OUTPUT ;
    USE SIGNAL ;
    PORT
      LAYER M4 ;
        RECT  0 121.824 0.084 121.848 ;
    END
  END b[154]
  PIN b[155]
    DIRECTION OUTPUT ;
    USE SIGNAL ;
    PORT
      LAYER M4 ;
        RECT  0 121.968 0.084 121.992 ;
    END
  END b[155]
  PIN b[156]
    DIRECTION OUTPUT ;
    USE SIGNAL ;
    PORT
      LAYER M4 ;
        RECT  0 122.112 0.084 122.136 ;
    END
  END b[156]
  PIN b[157]
    DIRECTION OUTPUT ;
    USE SIGNAL ;
    PORT
      LAYER M4 ;
        RECT  0 122.256 0.084 122.28 ;
    END
  END b[157]
  PIN b[158]
    DIRECTION OUTPUT ;
    USE SIGNAL ;
    PORT
      LAYER M4 ;
        RECT  0 122.4 0.084 122.424 ;
    END
  END b[158]
  PIN b[159]
    DIRECTION OUTPUT ;
    USE SIGNAL ;
    PORT
      LAYER M4 ;
        RECT  0 122.544 0.084 122.568 ;
    END
  END b[159]
  PIN b[15]
    DIRECTION OUTPUT ;
    USE SIGNAL ;
    PORT
      LAYER M4 ;
        RECT  0 33.84 0.084 33.864 ;
    END
  END b[15]
  PIN b[160]
    DIRECTION OUTPUT ;
    USE SIGNAL ;
    PORT
      LAYER M4 ;
        RECT  0 128.736 0.084 128.76 ;
    END
  END b[160]
  PIN b[161]
    DIRECTION OUTPUT ;
    USE SIGNAL ;
    PORT
      LAYER M4 ;
        RECT  0 128.88 0.084 128.904 ;
    END
  END b[161]
  PIN b[162]
    DIRECTION OUTPUT ;
    USE SIGNAL ;
    PORT
      LAYER M4 ;
        RECT  0 129.024 0.084 129.048 ;
    END
  END b[162]
  PIN b[163]
    DIRECTION OUTPUT ;
    USE SIGNAL ;
    PORT
      LAYER M4 ;
        RECT  0 129.168 0.084 129.192 ;
    END
  END b[163]
  PIN b[164]
    DIRECTION OUTPUT ;
    USE SIGNAL ;
    PORT
      LAYER M4 ;
        RECT  0 129.312 0.084 129.336 ;
    END
  END b[164]
  PIN b[165]
    DIRECTION OUTPUT ;
    USE SIGNAL ;
    PORT
      LAYER M4 ;
        RECT  0 129.456 0.084 129.48 ;
    END
  END b[165]
  PIN b[166]
    DIRECTION OUTPUT ;
    USE SIGNAL ;
    PORT
      LAYER M4 ;
        RECT  0 129.6 0.084 129.624 ;
    END
  END b[166]
  PIN b[167]
    DIRECTION OUTPUT ;
    USE SIGNAL ;
    PORT
      LAYER M4 ;
        RECT  0 129.744 0.084 129.768 ;
    END
  END b[167]
  PIN b[168]
    DIRECTION OUTPUT ;
    USE SIGNAL ;
    PORT
      LAYER M4 ;
        RECT  0 129.888 0.084 129.912 ;
    END
  END b[168]
  PIN b[169]
    DIRECTION OUTPUT ;
    USE SIGNAL ;
    PORT
      LAYER M4 ;
        RECT  0 130.032 0.084 130.056 ;
    END
  END b[169]
  PIN b[16]
    DIRECTION OUTPUT ;
    USE SIGNAL ;
    PORT
      LAYER M4 ;
        RECT  0 33.984 0.084 34.008 ;
    END
  END b[16]
  PIN b[170]
    DIRECTION OUTPUT ;
    USE SIGNAL ;
    PORT
      LAYER M4 ;
        RECT  0 130.176 0.084 130.2 ;
    END
  END b[170]
  PIN b[171]
    DIRECTION OUTPUT ;
    USE SIGNAL ;
    PORT
      LAYER M4 ;
        RECT  0 130.32 0.084 130.344 ;
    END
  END b[171]
  PIN b[172]
    DIRECTION OUTPUT ;
    USE SIGNAL ;
    PORT
      LAYER M4 ;
        RECT  0 130.464 0.084 130.488 ;
    END
  END b[172]
  PIN b[173]
    DIRECTION OUTPUT ;
    USE SIGNAL ;
    PORT
      LAYER M4 ;
        RECT  0 130.608 0.084 130.632 ;
    END
  END b[173]
  PIN b[174]
    DIRECTION OUTPUT ;
    USE SIGNAL ;
    PORT
      LAYER M4 ;
        RECT  0 130.752 0.084 130.776 ;
    END
  END b[174]
  PIN b[175]
    DIRECTION OUTPUT ;
    USE SIGNAL ;
    PORT
      LAYER M4 ;
        RECT  0 130.896 0.084 130.92 ;
    END
  END b[175]
  PIN b[176]
    DIRECTION OUTPUT ;
    USE SIGNAL ;
    PORT
      LAYER M4 ;
        RECT  0 131.04 0.084 131.064 ;
    END
  END b[176]
  PIN b[177]
    DIRECTION OUTPUT ;
    USE SIGNAL ;
    PORT
      LAYER M4 ;
        RECT  0 131.184 0.084 131.208 ;
    END
  END b[177]
  PIN b[178]
    DIRECTION OUTPUT ;
    USE SIGNAL ;
    PORT
      LAYER M4 ;
        RECT  0 131.328 0.084 131.352 ;
    END
  END b[178]
  PIN b[179]
    DIRECTION OUTPUT ;
    USE SIGNAL ;
    PORT
      LAYER M4 ;
        RECT  0 131.472 0.084 131.496 ;
    END
  END b[179]
  PIN b[17]
    DIRECTION OUTPUT ;
    USE SIGNAL ;
    PORT
      LAYER M4 ;
        RECT  0 34.128 0.084 34.152 ;
    END
  END b[17]
  PIN b[180]
    DIRECTION OUTPUT ;
    USE SIGNAL ;
    PORT
      LAYER M4 ;
        RECT  0 131.616 0.084 131.64 ;
    END
  END b[180]
  PIN b[181]
    DIRECTION OUTPUT ;
    USE SIGNAL ;
    PORT
      LAYER M4 ;
        RECT  0 131.76 0.084 131.784 ;
    END
  END b[181]
  PIN b[18]
    DIRECTION OUTPUT ;
    USE SIGNAL ;
    PORT
      LAYER M4 ;
        RECT  0 34.272 0.084 34.296 ;
    END
  END b[18]
  PIN b[19]
    DIRECTION OUTPUT ;
    USE SIGNAL ;
    PORT
      LAYER M4 ;
        RECT  0 34.416 0.084 34.44 ;
    END
  END b[19]
  PIN b[1]
    DIRECTION OUTPUT ;
    USE SIGNAL ;
    PORT
      LAYER M4 ;
        RECT  0 31.824 0.084 31.848 ;
    END
  END b[1]
  PIN b[20]
    DIRECTION OUTPUT ;
    USE SIGNAL ;
    PORT
      LAYER M4 ;
        RECT  0 34.56 0.084 34.584 ;
    END
  END b[20]
  PIN b[21]
    DIRECTION OUTPUT ;
    USE SIGNAL ;
    PORT
      LAYER M4 ;
        RECT  0 34.704 0.084 34.728 ;
    END
  END b[21]
  PIN b[22]
    DIRECTION OUTPUT ;
    USE SIGNAL ;
    PORT
      LAYER M4 ;
        RECT  0 34.848 0.084 34.872 ;
    END
  END b[22]
  PIN b[23]
    DIRECTION OUTPUT ;
    USE SIGNAL ;
    PORT
      LAYER M4 ;
        RECT  0 34.992 0.084 35.016 ;
    END
  END b[23]
  PIN b[24]
    DIRECTION OUTPUT ;
    USE SIGNAL ;
    PORT
      LAYER M4 ;
        RECT  0 35.136 0.084 35.16 ;
    END
  END b[24]
  PIN b[25]
    DIRECTION OUTPUT ;
    USE SIGNAL ;
    PORT
      LAYER M4 ;
        RECT  0 35.28 0.084 35.304 ;
    END
  END b[25]
  PIN b[26]
    DIRECTION OUTPUT ;
    USE SIGNAL ;
    PORT
      LAYER M4 ;
        RECT  0 35.424 0.084 35.448 ;
    END
  END b[26]
  PIN b[27]
    DIRECTION OUTPUT ;
    USE SIGNAL ;
    PORT
      LAYER M4 ;
        RECT  0 35.568 0.084 35.592 ;
    END
  END b[27]
  PIN b[28]
    DIRECTION OUTPUT ;
    USE SIGNAL ;
    PORT
      LAYER M4 ;
        RECT  0 35.712 0.084 35.736 ;
    END
  END b[28]
  PIN b[29]
    DIRECTION OUTPUT ;
    USE SIGNAL ;
    PORT
      LAYER M4 ;
        RECT  0 35.856 0.084 35.88 ;
    END
  END b[29]
  PIN b[2]
    DIRECTION OUTPUT ;
    USE SIGNAL ;
    PORT
      LAYER M4 ;
        RECT  0 31.968 0.084 31.992 ;
    END
  END b[2]
  PIN b[30]
    DIRECTION OUTPUT ;
    USE SIGNAL ;
    PORT
      LAYER M4 ;
        RECT  0 36 0.084 36.024 ;
    END
  END b[30]
  PIN b[31]
    DIRECTION OUTPUT ;
    USE SIGNAL ;
    PORT
      LAYER M4 ;
        RECT  0 36.144 0.084 36.168 ;
    END
  END b[31]
  PIN b[32]
    DIRECTION OUTPUT ;
    USE SIGNAL ;
    PORT
      LAYER M4 ;
        RECT  0 40.896 0.084 40.92 ;
    END
  END b[32]
  PIN b[33]
    DIRECTION OUTPUT ;
    USE SIGNAL ;
    PORT
      LAYER M4 ;
        RECT  0 41.04 0.084 41.064 ;
    END
  END b[33]
  PIN b[34]
    DIRECTION OUTPUT ;
    USE SIGNAL ;
    PORT
      LAYER M4 ;
        RECT  0 41.184 0.084 41.208 ;
    END
  END b[34]
  PIN b[35]
    DIRECTION OUTPUT ;
    USE SIGNAL ;
    PORT
      LAYER M4 ;
        RECT  0 41.328 0.084 41.352 ;
    END
  END b[35]
  PIN b[36]
    DIRECTION OUTPUT ;
    USE SIGNAL ;
    PORT
      LAYER M4 ;
        RECT  0 41.472 0.084 41.496 ;
    END
  END b[36]
  PIN b[37]
    DIRECTION OUTPUT ;
    USE SIGNAL ;
    PORT
      LAYER M4 ;
        RECT  0 41.616 0.084 41.64 ;
    END
  END b[37]
  PIN b[38]
    DIRECTION OUTPUT ;
    USE SIGNAL ;
    PORT
      LAYER M4 ;
        RECT  0 41.76 0.084 41.784 ;
    END
  END b[38]
  PIN b[39]
    DIRECTION OUTPUT ;
    USE SIGNAL ;
    PORT
      LAYER M4 ;
        RECT  0 41.904 0.084 41.928 ;
    END
  END b[39]
  PIN b[3]
    DIRECTION OUTPUT ;
    USE SIGNAL ;
    PORT
      LAYER M4 ;
        RECT  0 32.112 0.084 32.136 ;
    END
  END b[3]
  PIN b[40]
    DIRECTION OUTPUT ;
    USE SIGNAL ;
    PORT
      LAYER M4 ;
        RECT  0 42.048 0.084 42.072 ;
    END
  END b[40]
  PIN b[41]
    DIRECTION OUTPUT ;
    USE SIGNAL ;
    PORT
      LAYER M4 ;
        RECT  0 42.192 0.084 42.216 ;
    END
  END b[41]
  PIN b[42]
    DIRECTION OUTPUT ;
    USE SIGNAL ;
    PORT
      LAYER M4 ;
        RECT  0 42.336 0.084 42.36 ;
    END
  END b[42]
  PIN b[43]
    DIRECTION OUTPUT ;
    USE SIGNAL ;
    PORT
      LAYER M4 ;
        RECT  0 42.48 0.084 42.504 ;
    END
  END b[43]
  PIN b[44]
    DIRECTION OUTPUT ;
    USE SIGNAL ;
    PORT
      LAYER M4 ;
        RECT  0 42.624 0.084 42.648 ;
    END
  END b[44]
  PIN b[45]
    DIRECTION OUTPUT ;
    USE SIGNAL ;
    PORT
      LAYER M4 ;
        RECT  0 42.768 0.084 42.792 ;
    END
  END b[45]
  PIN b[46]
    DIRECTION OUTPUT ;
    USE SIGNAL ;
    PORT
      LAYER M4 ;
        RECT  0 42.912 0.084 42.936 ;
    END
  END b[46]
  PIN b[47]
    DIRECTION OUTPUT ;
    USE SIGNAL ;
    PORT
      LAYER M4 ;
        RECT  0 43.056 0.084 43.08 ;
    END
  END b[47]
  PIN b[48]
    DIRECTION OUTPUT ;
    USE SIGNAL ;
    PORT
      LAYER M4 ;
        RECT  0 43.2 0.084 43.224 ;
    END
  END b[48]
  PIN b[49]
    DIRECTION OUTPUT ;
    USE SIGNAL ;
    PORT
      LAYER M4 ;
        RECT  0 43.344 0.084 43.368 ;
    END
  END b[49]
  PIN b[4]
    DIRECTION OUTPUT ;
    USE SIGNAL ;
    PORT
      LAYER M4 ;
        RECT  0 32.256 0.084 32.28 ;
    END
  END b[4]
  PIN b[50]
    DIRECTION OUTPUT ;
    USE SIGNAL ;
    PORT
      LAYER M4 ;
        RECT  0 43.488 0.084 43.512 ;
    END
  END b[50]
  PIN b[51]
    DIRECTION OUTPUT ;
    USE SIGNAL ;
    PORT
      LAYER M4 ;
        RECT  0 43.632 0.084 43.656 ;
    END
  END b[51]
  PIN b[52]
    DIRECTION OUTPUT ;
    USE SIGNAL ;
    PORT
      LAYER M4 ;
        RECT  0 43.776 0.084 43.8 ;
    END
  END b[52]
  PIN b[53]
    DIRECTION OUTPUT ;
    USE SIGNAL ;
    PORT
      LAYER M4 ;
        RECT  0 43.92 0.084 43.944 ;
    END
  END b[53]
  PIN b[54]
    DIRECTION OUTPUT ;
    USE SIGNAL ;
    PORT
      LAYER M4 ;
        RECT  0 44.064 0.084 44.088 ;
    END
  END b[54]
  PIN b[55]
    DIRECTION OUTPUT ;
    USE SIGNAL ;
    PORT
      LAYER M4 ;
        RECT  0 44.208 0.084 44.232 ;
    END
  END b[55]
  PIN b[56]
    DIRECTION OUTPUT ;
    USE SIGNAL ;
    PORT
      LAYER M4 ;
        RECT  0 44.352 0.084 44.376 ;
    END
  END b[56]
  PIN b[57]
    DIRECTION OUTPUT ;
    USE SIGNAL ;
    PORT
      LAYER M4 ;
        RECT  0 44.496 0.084 44.52 ;
    END
  END b[57]
  PIN b[58]
    DIRECTION OUTPUT ;
    USE SIGNAL ;
    PORT
      LAYER M4 ;
        RECT  0 44.64 0.084 44.664 ;
    END
  END b[58]
  PIN b[59]
    DIRECTION OUTPUT ;
    USE SIGNAL ;
    PORT
      LAYER M4 ;
        RECT  0 44.784 0.084 44.808 ;
    END
  END b[59]
  PIN b[5]
    DIRECTION OUTPUT ;
    USE SIGNAL ;
    PORT
      LAYER M4 ;
        RECT  0 32.4 0.084 32.424 ;
    END
  END b[5]
  PIN b[60]
    DIRECTION OUTPUT ;
    USE SIGNAL ;
    PORT
      LAYER M4 ;
        RECT  0 44.928 0.084 44.952 ;
    END
  END b[60]
  PIN b[61]
    DIRECTION OUTPUT ;
    USE SIGNAL ;
    PORT
      LAYER M4 ;
        RECT  0 45.072 0.084 45.096 ;
    END
  END b[61]
  PIN b[62]
    DIRECTION OUTPUT ;
    USE SIGNAL ;
    PORT
      LAYER M4 ;
        RECT  0 45.216 0.084 45.24 ;
    END
  END b[62]
  PIN b[63]
    DIRECTION OUTPUT ;
    USE SIGNAL ;
    PORT
      LAYER M4 ;
        RECT  0 45.36 0.084 45.384 ;
    END
  END b[63]
  PIN b[64]
    DIRECTION OUTPUT ;
    USE SIGNAL ;
    PORT
      LAYER M4 ;
        RECT  0 74.304 0.084 74.328 ;
    END
  END b[64]
  PIN b[65]
    DIRECTION OUTPUT ;
    USE SIGNAL ;
    PORT
      LAYER M4 ;
        RECT  0 74.448 0.084 74.472 ;
    END
  END b[65]
  PIN b[66]
    DIRECTION OUTPUT ;
    USE SIGNAL ;
    PORT
      LAYER M4 ;
        RECT  0 74.592 0.084 74.616 ;
    END
  END b[66]
  PIN b[67]
    DIRECTION OUTPUT ;
    USE SIGNAL ;
    PORT
      LAYER M4 ;
        RECT  0 74.736 0.084 74.76 ;
    END
  END b[67]
  PIN b[68]
    DIRECTION OUTPUT ;
    USE SIGNAL ;
    PORT
      LAYER M4 ;
        RECT  0 74.88 0.084 74.904 ;
    END
  END b[68]
  PIN b[69]
    DIRECTION OUTPUT ;
    USE SIGNAL ;
    PORT
      LAYER M4 ;
        RECT  0 75.024 0.084 75.048 ;
    END
  END b[69]
  PIN b[6]
    DIRECTION OUTPUT ;
    USE SIGNAL ;
    PORT
      LAYER M4 ;
        RECT  0 32.544 0.084 32.568 ;
    END
  END b[6]
  PIN b[70]
    DIRECTION OUTPUT ;
    USE SIGNAL ;
    PORT
      LAYER M4 ;
        RECT  0 75.168 0.084 75.192 ;
    END
  END b[70]
  PIN b[71]
    DIRECTION OUTPUT ;
    USE SIGNAL ;
    PORT
      LAYER M4 ;
        RECT  0 75.312 0.084 75.336 ;
    END
  END b[71]
  PIN b[72]
    DIRECTION OUTPUT ;
    USE SIGNAL ;
    PORT
      LAYER M4 ;
        RECT  0 75.456 0.084 75.48 ;
    END
  END b[72]
  PIN b[73]
    DIRECTION OUTPUT ;
    USE SIGNAL ;
    PORT
      LAYER M4 ;
        RECT  0 75.6 0.084 75.624 ;
    END
  END b[73]
  PIN b[74]
    DIRECTION OUTPUT ;
    USE SIGNAL ;
    PORT
      LAYER M4 ;
        RECT  0 75.744 0.084 75.768 ;
    END
  END b[74]
  PIN b[75]
    DIRECTION OUTPUT ;
    USE SIGNAL ;
    PORT
      LAYER M4 ;
        RECT  0 75.888 0.084 75.912 ;
    END
  END b[75]
  PIN b[76]
    DIRECTION OUTPUT ;
    USE SIGNAL ;
    PORT
      LAYER M4 ;
        RECT  0 76.032 0.084 76.056 ;
    END
  END b[76]
  PIN b[77]
    DIRECTION OUTPUT ;
    USE SIGNAL ;
    PORT
      LAYER M4 ;
        RECT  0 76.176 0.084 76.2 ;
    END
  END b[77]
  PIN b[78]
    DIRECTION OUTPUT ;
    USE SIGNAL ;
    PORT
      LAYER M4 ;
        RECT  0 76.32 0.084 76.344 ;
    END
  END b[78]
  PIN b[79]
    DIRECTION OUTPUT ;
    USE SIGNAL ;
    PORT
      LAYER M4 ;
        RECT  0 76.464 0.084 76.488 ;
    END
  END b[79]
  PIN b[7]
    DIRECTION OUTPUT ;
    USE SIGNAL ;
    PORT
      LAYER M4 ;
        RECT  0 32.688 0.084 32.712 ;
    END
  END b[7]
  PIN b[80]
    DIRECTION OUTPUT ;
    USE SIGNAL ;
    PORT
      LAYER M4 ;
        RECT  0 76.608 0.084 76.632 ;
    END
  END b[80]
  PIN b[81]
    DIRECTION OUTPUT ;
    USE SIGNAL ;
    PORT
      LAYER M4 ;
        RECT  0 76.752 0.084 76.776 ;
    END
  END b[81]
  PIN b[82]
    DIRECTION OUTPUT ;
    USE SIGNAL ;
    PORT
      LAYER M4 ;
        RECT  0 76.896 0.084 76.92 ;
    END
  END b[82]
  PIN b[83]
    DIRECTION OUTPUT ;
    USE SIGNAL ;
    PORT
      LAYER M4 ;
        RECT  0 77.04 0.084 77.064 ;
    END
  END b[83]
  PIN b[84]
    DIRECTION OUTPUT ;
    USE SIGNAL ;
    PORT
      LAYER M4 ;
        RECT  0 77.184 0.084 77.208 ;
    END
  END b[84]
  PIN b[85]
    DIRECTION OUTPUT ;
    USE SIGNAL ;
    PORT
      LAYER M4 ;
        RECT  0 77.328 0.084 77.352 ;
    END
  END b[85]
  PIN b[86]
    DIRECTION OUTPUT ;
    USE SIGNAL ;
    PORT
      LAYER M4 ;
        RECT  0 77.472 0.084 77.496 ;
    END
  END b[86]
  PIN b[87]
    DIRECTION OUTPUT ;
    USE SIGNAL ;
    PORT
      LAYER M4 ;
        RECT  0 77.616 0.084 77.64 ;
    END
  END b[87]
  PIN b[88]
    DIRECTION OUTPUT ;
    USE SIGNAL ;
    PORT
      LAYER M4 ;
        RECT  0 77.76 0.084 77.784 ;
    END
  END b[88]
  PIN b[89]
    DIRECTION OUTPUT ;
    USE SIGNAL ;
    PORT
      LAYER M4 ;
        RECT  0 77.904 0.084 77.928 ;
    END
  END b[89]
  PIN b[8]
    DIRECTION OUTPUT ;
    USE SIGNAL ;
    PORT
      LAYER M4 ;
        RECT  0 32.832 0.084 32.856 ;
    END
  END b[8]
  PIN b[90]
    DIRECTION OUTPUT ;
    USE SIGNAL ;
    PORT
      LAYER M4 ;
        RECT  0 78.048 0.084 78.072 ;
    END
  END b[90]
  PIN b[91]
    DIRECTION OUTPUT ;
    USE SIGNAL ;
    PORT
      LAYER M4 ;
        RECT  0 78.192 0.084 78.216 ;
    END
  END b[91]
  PIN b[92]
    DIRECTION OUTPUT ;
    USE SIGNAL ;
    PORT
      LAYER M4 ;
        RECT  0 78.336 0.084 78.36 ;
    END
  END b[92]
  PIN b[93]
    DIRECTION OUTPUT ;
    USE SIGNAL ;
    PORT
      LAYER M4 ;
        RECT  0 78.48 0.084 78.504 ;
    END
  END b[93]
  PIN b[94]
    DIRECTION OUTPUT ;
    USE SIGNAL ;
    PORT
      LAYER M4 ;
        RECT  0 78.624 0.084 78.648 ;
    END
  END b[94]
  PIN b[95]
    DIRECTION OUTPUT ;
    USE SIGNAL ;
    PORT
      LAYER M4 ;
        RECT  0 78.768 0.084 78.792 ;
    END
  END b[95]
  PIN b[96]
    DIRECTION OUTPUT ;
    USE SIGNAL ;
    PORT
      LAYER M4 ;
        RECT  0 84.672 0.084 84.696 ;
    END
  END b[96]
  PIN b[97]
    DIRECTION OUTPUT ;
    USE SIGNAL ;
    PORT
      LAYER M4 ;
        RECT  0 84.816 0.084 84.84 ;
    END
  END b[97]
  PIN b[98]
    DIRECTION OUTPUT ;
    USE SIGNAL ;
    PORT
      LAYER M4 ;
        RECT  0 84.96 0.084 84.984 ;
    END
  END b[98]
  PIN b[99]
    DIRECTION OUTPUT ;
    USE SIGNAL ;
    PORT
      LAYER M4 ;
        RECT  0 85.104 0.084 85.128 ;
    END
  END b[99]
  PIN b[9]
    DIRECTION OUTPUT ;
    USE SIGNAL ;
    PORT
      LAYER M4 ;
        RECT  0 32.976 0.084 33 ;
    END
  END b[9]
  PIN ck
    DIRECTION INPUT ;
    USE SIGNAL ;
    PORT
      LAYER M3 ;
        RECT  37.908 170.603 37.926 170.64 ;
    END
  END ck
  PIN ck_s
    DIRECTION INPUT ;
    USE SIGNAL ;
    PORT
      LAYER M3 ;
        RECT  38.016 170.603 38.034 170.64 ;
    END
  END ck_s
  PIN en
    DIRECTION INPUT ;
    USE SIGNAL ;
    PORT
      LAYER M3 ;
        RECT  38.124 170.603 38.142 170.64 ;
    END
  END en
  PIN fault
    DIRECTION OUTPUT ;
    USE SIGNAL ;
    PORT
      LAYER M3 ;
        RECT  38.232 170.603 38.25 170.64 ;
    END
  END fault
  PIN k0
    DIRECTION INPUT ;
    USE SIGNAL ;
    PORT
      LAYER M3 ;
        RECT  38.34 170.603 38.358 170.64 ;
    END
  END k0
  PIN k1
    DIRECTION INPUT ;
    USE SIGNAL ;
    PORT
      LAYER M3 ;
        RECT  38.448 170.603 38.466 170.64 ;
    END
  END k1
  PIN k2
    DIRECTION INPUT ;
    USE SIGNAL ;
    PORT
      LAYER M3 ;
        RECT  38.556 170.603 38.574 170.64 ;
    END
  END k2
  PIN k3
    DIRECTION INPUT ;
    USE SIGNAL ;
    PORT
      LAYER M3 ;
        RECT  38.664 170.603 38.682 170.64 ;
    END
  END k3
  PIN rs
    DIRECTION INPUT ;
    USE SIGNAL ;
    PORT
      LAYER M3 ;
        RECT  38.772 170.603 38.79 170.64 ;
    END
  END rs
  PIN tie_hi
    DIRECTION OUTPUT ;
    USE SIGNAL ;
    PORT
      LAYER M3 ;
        RECT  38.88 170.603 38.898 170.64 ;
    END
  END tie_hi
  PIN tie_lo
    DIRECTION OUTPUT ;
    USE SIGNAL ;
    PORT
      LAYER M3 ;
        RECT  38.988 170.603 39.006 170.64 ;
    END
  END tie_lo
  PIN VDD
    DIRECTION INOUT ;
    USE POWER ;
    PORT
      LAYER M5 ;
        RECT  94.392 2.151 94.512 168.489 ;
        RECT  91.692 2.151 91.812 168.489 ;
        RECT  88.992 2.151 89.112 168.489 ;
        RECT  86.292 2.151 86.412 168.489 ;
        RECT  83.592 2.151 83.712 168.489 ;
        RECT  80.892 2.151 81.012 168.489 ;
        RECT  78.192 2.151 78.312 168.489 ;
        RECT  75.492 2.151 75.612 168.489 ;
        RECT  72.792 2.151 72.912 168.489 ;
        RECT  70.092 2.151 70.212 168.489 ;
        RECT  67.392 2.151 67.512 168.489 ;
        RECT  64.692 2.151 64.812 168.489 ;
        RECT  61.992 2.151 62.112 168.489 ;
        RECT  59.292 2.151 59.412 168.489 ;
        RECT  56.592 2.151 56.712 168.489 ;
        RECT  53.892 2.151 54.012 168.489 ;
        RECT  51.192 2.151 51.312 168.489 ;
        RECT  48.492 2.151 48.612 168.489 ;
        RECT  45.792 2.151 45.912 168.489 ;
        RECT  43.092 2.151 43.212 168.489 ;
        RECT  40.392 2.151 40.512 168.489 ;
        RECT  37.692 2.151 37.812 168.489 ;
        RECT  34.992 2.151 35.112 168.489 ;
        RECT  32.292 2.151 32.412 168.489 ;
        RECT  29.592 2.151 29.712 168.489 ;
        RECT  26.892 2.151 27.012 168.489 ;
        RECT  24.192 2.151 24.312 168.489 ;
        RECT  21.492 2.151 21.612 168.489 ;
        RECT  18.792 2.151 18.912 168.489 ;
        RECT  16.092 2.151 16.212 168.489 ;
        RECT  13.392 2.151 13.512 168.489 ;
        RECT  10.692 2.151 10.812 168.489 ;
        RECT  7.992 2.151 8.112 168.489 ;
        RECT  5.292 2.151 5.412 168.489 ;
        RECT  2.592 2.151 2.712 168.489 ;
    END
  END VDD
  PIN VSS
    DIRECTION INOUT ;
    USE GROUND ;
    PORT
      LAYER M5 ;
        RECT  94.2 2.137 94.32 168.503 ;
        RECT  91.5 2.137 91.62 168.503 ;
        RECT  88.8 2.137 88.92 168.503 ;
        RECT  86.1 2.137 86.22 168.503 ;
        RECT  83.4 2.137 83.52 168.503 ;
        RECT  80.7 2.137 80.82 168.503 ;
        RECT  78 2.137 78.12 168.503 ;
        RECT  75.3 2.137 75.42 168.503 ;
        RECT  72.6 2.137 72.72 168.503 ;
        RECT  69.9 2.137 70.02 168.503 ;
        RECT  67.2 2.137 67.32 168.503 ;
        RECT  64.5 2.137 64.62 168.503 ;
        RECT  61.8 2.137 61.92 168.503 ;
        RECT  59.1 2.137 59.22 168.503 ;
        RECT  56.4 2.137 56.52 168.503 ;
        RECT  53.7 2.137 53.82 168.503 ;
        RECT  51 2.137 51.12 168.503 ;
        RECT  48.3 2.137 48.42 168.503 ;
        RECT  45.6 2.137 45.72 168.503 ;
        RECT  42.9 2.137 43.02 168.503 ;
        RECT  40.2 2.137 40.32 168.503 ;
        RECT  37.5 2.137 37.62 168.503 ;
        RECT  34.8 2.137 34.92 168.503 ;
        RECT  32.1 2.137 32.22 168.503 ;
        RECT  29.4 2.137 29.52 168.503 ;
        RECT  26.7 2.137 26.82 168.503 ;
        RECT  24 2.137 24.12 168.503 ;
        RECT  21.3 2.137 21.42 168.503 ;
        RECT  18.6 2.137 18.72 168.503 ;
        RECT  15.9 2.137 16.02 168.503 ;
        RECT  13.2 2.137 13.32 168.503 ;
        RECT  10.5 2.137 10.62 168.503 ;
        RECT  7.8 2.137 7.92 168.503 ;
        RECT  5.1 2.137 5.22 168.503 ;
        RECT  2.4 2.137 2.52 168.503 ;
    END
  END VSS
  OBS
    LAYER RVTN ;
     RECT  2.16 2.16 96.12 2.295 ;
     RECT  2.16 2.565 96.12 2.835 ;
     RECT  2.16 3.105 96.12 3.375 ;
     RECT  2.16 3.645 96.12 3.915 ;
     RECT  2.16 4.185 96.12 4.455 ;
     RECT  2.16 4.725 96.12 4.995 ;
     RECT  2.16 5.265 96.12 5.535 ;
     RECT  2.16 5.805 96.12 6.075 ;
     RECT  2.16 6.345 96.12 6.615 ;
     RECT  2.16 6.885 96.12 7.155 ;
     RECT  2.16 7.425 96.12 7.695 ;
     RECT  2.16 7.965 96.12 8.235 ;
     RECT  2.16 8.505 96.12 8.775 ;
     RECT  2.16 9.045 96.12 9.315 ;
     RECT  2.16 9.585 96.12 9.855 ;
     RECT  2.16 10.125 96.12 10.395 ;
     RECT  2.16 10.665 96.12 10.935 ;
     RECT  2.16 11.205 96.12 11.475 ;
     RECT  2.16 11.745 96.12 12.015 ;
     RECT  2.16 12.285 96.12 12.555 ;
     RECT  2.16 12.825 96.12 13.095 ;
     RECT  2.16 13.365 96.12 13.635 ;
     RECT  2.16 13.905 96.12 14.175 ;
     RECT  2.16 14.445 96.12 14.715 ;
     RECT  2.16 14.985 96.12 15.255 ;
     RECT  2.16 15.525 96.12 15.795 ;
     RECT  2.16 16.065 96.12 16.335 ;
     RECT  2.16 16.605 96.12 16.875 ;
     RECT  2.16 17.145 96.12 17.415 ;
     RECT  2.16 17.685 96.12 17.955 ;
     RECT  2.16 18.225 96.12 18.495 ;
     RECT  2.16 18.765 96.12 19.035 ;
     RECT  2.16 19.305 96.12 19.575 ;
     RECT  2.16 19.845 96.12 20.115 ;
     RECT  2.16 20.385 96.12 20.655 ;
     RECT  2.16 20.925 96.12 21.195 ;
     RECT  2.16 21.465 96.12 21.735 ;
     RECT  2.16 22.005 96.12 22.275 ;
     RECT  2.16 22.545 96.12 22.815 ;
     RECT  2.16 23.085 96.12 23.355 ;
     RECT  2.16 23.625 96.12 23.895 ;
     RECT  2.16 24.165 96.12 24.435 ;
     RECT  2.16 24.705 96.12 24.975 ;
     RECT  2.16 25.245 96.12 25.515 ;
     RECT  2.16 25.785 96.12 26.055 ;
     RECT  2.16 26.325 96.12 26.595 ;
     RECT  2.16 26.865 96.12 27.135 ;
     RECT  2.16 27.405 96.12 27.675 ;
     RECT  2.16 27.945 96.12 28.215 ;
     RECT  2.16 28.485 96.12 28.755 ;
     RECT  2.16 29.025 96.12 29.295 ;
     RECT  2.16 29.565 96.12 29.835 ;
     RECT  2.16 30.105 96.12 30.375 ;
     RECT  2.16 30.645 96.12 30.915 ;
     RECT  2.16 31.185 96.12 31.455 ;
     RECT  2.16 31.725 96.12 31.995 ;
     RECT  2.16 32.265 96.12 32.535 ;
     RECT  2.16 32.805 96.12 33.075 ;
     RECT  2.16 33.345 96.12 33.615 ;
     RECT  2.16 33.885 96.12 34.155 ;
     RECT  2.16 34.425 96.12 34.695 ;
     RECT  2.16 34.965 96.12 35.235 ;
     RECT  2.16 35.505 96.12 35.775 ;
     RECT  2.16 36.045 96.12 36.315 ;
     RECT  2.16 36.585 96.12 36.855 ;
     RECT  2.16 37.125 96.12 37.395 ;
     RECT  2.16 37.665 96.12 37.935 ;
     RECT  2.16 38.205 96.12 38.475 ;
     RECT  2.16 38.745 96.12 39.015 ;
     RECT  2.16 39.285 96.12 39.555 ;
     RECT  2.16 39.825 96.12 40.095 ;
     RECT  2.16 40.365 96.12 40.635 ;
     RECT  2.16 40.905 96.12 41.04 ;
     RECT  2.16 41.04 41.148 41.175 ;
     RECT  77.22 41.04 96.12 41.175 ;
     RECT  2.16 41.445 41.148 41.715 ;
     RECT  77.22 41.445 96.12 41.715 ;
     RECT  2.16 41.985 41.148 42.255 ;
     RECT  77.22 41.985 96.12 42.255 ;
     RECT  2.16 42.525 41.148 42.795 ;
     RECT  77.22 42.525 96.12 42.795 ;
     RECT  2.16 43.065 41.148 43.335 ;
     RECT  77.22 43.065 96.12 43.335 ;
     RECT  2.16 43.605 41.148 43.875 ;
     RECT  77.22 43.605 96.12 43.875 ;
     RECT  2.16 44.145 41.148 44.415 ;
     RECT  77.22 44.145 96.12 44.415 ;
     RECT  2.16 44.685 41.148 44.955 ;
     RECT  77.22 44.685 96.12 44.955 ;
     RECT  2.16 45.225 41.148 45.495 ;
     RECT  77.22 45.225 96.12 45.495 ;
     RECT  2.16 45.765 41.148 46.035 ;
     RECT  77.22 45.765 96.12 46.035 ;
     RECT  2.16 46.305 41.148 46.575 ;
     RECT  77.22 46.305 96.12 46.575 ;
     RECT  2.16 46.845 41.148 47.115 ;
     RECT  77.22 46.845 96.12 47.115 ;
     RECT  2.16 47.385 41.148 47.655 ;
     RECT  77.22 47.385 96.12 47.655 ;
     RECT  2.16 47.925 41.148 48.195 ;
     RECT  77.22 47.925 96.12 48.195 ;
     RECT  2.16 48.465 41.148 48.735 ;
     RECT  77.22 48.465 96.12 48.735 ;
     RECT  2.16 49.005 41.148 49.275 ;
     RECT  77.22 49.005 96.12 49.275 ;
     RECT  2.16 49.545 41.148 49.815 ;
     RECT  77.22 49.545 96.12 49.815 ;
     RECT  2.16 50.085 41.148 50.355 ;
     RECT  77.22 50.085 96.12 50.355 ;
     RECT  2.16 50.625 41.148 50.895 ;
     RECT  77.22 50.625 96.12 50.895 ;
     RECT  2.16 51.165 41.148 51.435 ;
     RECT  77.22 51.165 96.12 51.435 ;
     RECT  2.16 51.705 41.148 51.975 ;
     RECT  77.22 51.705 96.12 51.975 ;
     RECT  2.16 52.245 41.148 52.515 ;
     RECT  77.22 52.245 96.12 52.515 ;
     RECT  2.16 52.785 41.148 53.055 ;
     RECT  77.22 52.785 96.12 53.055 ;
     RECT  2.16 53.325 41.148 53.595 ;
     RECT  77.22 53.325 96.12 53.595 ;
     RECT  2.16 53.865 41.148 54.135 ;
     RECT  77.22 53.865 96.12 54.135 ;
     RECT  2.16 54.405 41.148 54.675 ;
     RECT  77.22 54.405 96.12 54.675 ;
     RECT  2.16 54.945 41.148 55.215 ;
     RECT  77.22 54.945 96.12 55.215 ;
     RECT  2.16 55.485 41.148 55.755 ;
     RECT  77.22 55.485 96.12 55.755 ;
     RECT  2.16 56.025 41.148 56.295 ;
     RECT  77.22 56.025 96.12 56.295 ;
     RECT  2.16 56.565 41.148 56.835 ;
     RECT  77.22 56.565 96.12 56.835 ;
     RECT  2.16 57.105 41.148 57.375 ;
     RECT  77.22 57.105 96.12 57.375 ;
     RECT  2.16 57.645 41.148 57.915 ;
     RECT  77.22 57.645 96.12 57.915 ;
     RECT  2.16 58.185 41.148 58.455 ;
     RECT  77.22 58.185 96.12 58.455 ;
     RECT  2.16 58.725 41.148 58.995 ;
     RECT  77.22 58.725 96.12 58.995 ;
     RECT  2.16 59.265 41.148 59.535 ;
     RECT  77.22 59.265 96.12 59.535 ;
     RECT  2.16 59.805 41.148 60.075 ;
     RECT  77.22 59.805 96.12 60.075 ;
     RECT  2.16 60.345 41.148 60.615 ;
     RECT  77.22 60.345 96.12 60.615 ;
     RECT  2.16 60.885 41.148 61.155 ;
     RECT  77.22 60.885 96.12 61.155 ;
     RECT  2.16 61.425 41.148 61.695 ;
     RECT  77.22 61.425 96.12 61.695 ;
     RECT  2.16 61.965 41.148 62.235 ;
     RECT  77.22 61.965 96.12 62.235 ;
     RECT  2.16 62.505 41.148 62.64 ;
     RECT  77.22 62.505 96.12 62.64 ;
     RECT  2.16 62.64 96.12 62.775 ;
     RECT  2.16 63.045 96.12 63.315 ;
     RECT  2.16 63.585 96.12 63.855 ;
     RECT  2.16 64.125 96.12 64.395 ;
     RECT  2.16 64.665 96.12 64.935 ;
     RECT  2.16 65.205 96.12 65.475 ;
     RECT  2.16 65.745 96.12 66.015 ;
     RECT  2.16 66.285 96.12 66.555 ;
     RECT  2.16 66.825 96.12 67.095 ;
     RECT  2.16 67.365 96.12 67.635 ;
     RECT  2.16 67.905 96.12 68.175 ;
     RECT  2.16 68.445 96.12 68.715 ;
     RECT  2.16 68.985 96.12 69.255 ;
     RECT  2.16 69.525 96.12 69.795 ;
     RECT  2.16 70.065 96.12 70.335 ;
     RECT  2.16 70.605 96.12 70.875 ;
     RECT  2.16 71.145 96.12 71.415 ;
     RECT  2.16 71.685 96.12 71.955 ;
     RECT  2.16 72.225 96.12 72.495 ;
     RECT  2.16 72.765 96.12 73.035 ;
     RECT  2.16 73.305 96.12 73.575 ;
     RECT  2.16 73.845 96.12 74.115 ;
     RECT  2.16 74.385 96.12 74.655 ;
     RECT  2.16 74.925 96.12 75.195 ;
     RECT  2.16 75.465 96.12 75.735 ;
     RECT  2.16 76.005 96.12 76.275 ;
     RECT  2.16 76.545 96.12 76.815 ;
     RECT  2.16 77.085 96.12 77.355 ;
     RECT  2.16 77.625 96.12 77.895 ;
     RECT  2.16 78.165 96.12 78.435 ;
     RECT  2.16 78.705 96.12 78.975 ;
     RECT  2.16 79.245 96.12 79.515 ;
     RECT  2.16 79.785 96.12 80.055 ;
     RECT  2.16 80.325 96.12 80.595 ;
     RECT  2.16 80.865 96.12 81.135 ;
     RECT  2.16 81.405 96.12 81.675 ;
     RECT  2.16 81.945 96.12 82.215 ;
     RECT  2.16 82.485 96.12 82.755 ;
     RECT  2.16 83.025 96.12 83.295 ;
     RECT  2.16 83.565 96.12 83.835 ;
     RECT  2.16 84.105 96.12 84.24 ;
     RECT  2.16 84.24 41.148 84.375 ;
     RECT  77.22 84.24 96.12 84.375 ;
     RECT  2.16 84.645 41.148 84.915 ;
     RECT  77.22 84.645 96.12 84.915 ;
     RECT  2.16 85.185 41.148 85.455 ;
     RECT  77.22 85.185 96.12 85.455 ;
     RECT  2.16 85.725 41.148 85.995 ;
     RECT  77.22 85.725 96.12 85.995 ;
     RECT  2.16 86.265 41.148 86.535 ;
     RECT  77.22 86.265 96.12 86.535 ;
     RECT  2.16 86.805 41.148 87.075 ;
     RECT  77.22 86.805 96.12 87.075 ;
     RECT  2.16 87.345 41.148 87.615 ;
     RECT  77.22 87.345 96.12 87.615 ;
     RECT  2.16 87.885 41.148 88.155 ;
     RECT  77.22 87.885 96.12 88.155 ;
     RECT  2.16 88.425 41.148 88.695 ;
     RECT  77.22 88.425 96.12 88.695 ;
     RECT  2.16 88.965 41.148 89.235 ;
     RECT  77.22 88.965 96.12 89.235 ;
     RECT  2.16 89.505 41.148 89.775 ;
     RECT  77.22 89.505 96.12 89.775 ;
     RECT  2.16 90.045 41.148 90.315 ;
     RECT  77.22 90.045 96.12 90.315 ;
     RECT  2.16 90.585 41.148 90.855 ;
     RECT  77.22 90.585 96.12 90.855 ;
     RECT  2.16 91.125 41.148 91.395 ;
     RECT  77.22 91.125 96.12 91.395 ;
     RECT  2.16 91.665 41.148 91.935 ;
     RECT  77.22 91.665 96.12 91.935 ;
     RECT  2.16 92.205 41.148 92.475 ;
     RECT  77.22 92.205 96.12 92.475 ;
     RECT  2.16 92.745 41.148 93.015 ;
     RECT  77.22 92.745 96.12 93.015 ;
     RECT  2.16 93.285 41.148 93.555 ;
     RECT  77.22 93.285 96.12 93.555 ;
     RECT  2.16 93.825 41.148 94.095 ;
     RECT  77.22 93.825 96.12 94.095 ;
     RECT  2.16 94.365 41.148 94.635 ;
     RECT  77.22 94.365 96.12 94.635 ;
     RECT  2.16 94.905 41.148 95.175 ;
     RECT  77.22 94.905 96.12 95.175 ;
     RECT  2.16 95.445 41.148 95.715 ;
     RECT  77.22 95.445 96.12 95.715 ;
     RECT  2.16 95.985 41.148 96.255 ;
     RECT  77.22 95.985 96.12 96.255 ;
     RECT  2.16 96.525 41.148 96.795 ;
     RECT  77.22 96.525 96.12 96.795 ;
     RECT  2.16 97.065 41.148 97.335 ;
     RECT  77.22 97.065 96.12 97.335 ;
     RECT  2.16 97.605 41.148 97.875 ;
     RECT  77.22 97.605 96.12 97.875 ;
     RECT  2.16 98.145 41.148 98.415 ;
     RECT  77.22 98.145 96.12 98.415 ;
     RECT  2.16 98.685 41.148 98.955 ;
     RECT  77.22 98.685 96.12 98.955 ;
     RECT  2.16 99.225 41.148 99.495 ;
     RECT  77.22 99.225 96.12 99.495 ;
     RECT  2.16 99.765 41.148 100.035 ;
     RECT  77.22 99.765 96.12 100.035 ;
     RECT  2.16 100.305 41.148 100.575 ;
     RECT  77.22 100.305 96.12 100.575 ;
     RECT  2.16 100.845 41.148 101.115 ;
     RECT  77.22 100.845 96.12 101.115 ;
     RECT  2.16 101.385 41.148 101.655 ;
     RECT  77.22 101.385 96.12 101.655 ;
     RECT  2.16 101.925 41.148 102.195 ;
     RECT  77.22 101.925 96.12 102.195 ;
     RECT  2.16 102.465 41.148 102.735 ;
     RECT  77.22 102.465 96.12 102.735 ;
     RECT  2.16 103.005 41.148 103.275 ;
     RECT  77.22 103.005 96.12 103.275 ;
     RECT  2.16 103.545 41.148 103.815 ;
     RECT  77.22 103.545 96.12 103.815 ;
     RECT  2.16 104.085 41.148 104.355 ;
     RECT  77.22 104.085 96.12 104.355 ;
     RECT  2.16 104.625 41.148 104.895 ;
     RECT  77.22 104.625 96.12 104.895 ;
     RECT  2.16 105.165 41.148 105.435 ;
     RECT  77.22 105.165 96.12 105.435 ;
     RECT  2.16 105.705 41.148 105.84 ;
     RECT  77.22 105.705 96.12 105.84 ;
     RECT  2.16 105.84 96.12 105.975 ;
     RECT  2.16 106.245 96.12 106.515 ;
     RECT  2.16 106.785 96.12 107.055 ;
     RECT  2.16 107.325 96.12 107.595 ;
     RECT  2.16 107.865 96.12 108.135 ;
     RECT  2.16 108.405 96.12 108.675 ;
     RECT  2.16 108.945 96.12 109.215 ;
     RECT  2.16 109.485 96.12 109.755 ;
     RECT  2.16 110.025 96.12 110.295 ;
     RECT  2.16 110.565 96.12 110.835 ;
     RECT  2.16 111.105 96.12 111.375 ;
     RECT  2.16 111.645 96.12 111.915 ;
     RECT  2.16 112.185 96.12 112.455 ;
     RECT  2.16 112.725 96.12 112.995 ;
     RECT  2.16 113.265 96.12 113.535 ;
     RECT  2.16 113.805 96.12 114.075 ;
     RECT  2.16 114.345 96.12 114.615 ;
     RECT  2.16 114.885 96.12 115.155 ;
     RECT  2.16 115.425 96.12 115.695 ;
     RECT  2.16 115.965 96.12 116.235 ;
     RECT  2.16 116.505 96.12 116.775 ;
     RECT  2.16 117.045 96.12 117.315 ;
     RECT  2.16 117.585 96.12 117.855 ;
     RECT  2.16 118.125 96.12 118.395 ;
     RECT  2.16 118.665 96.12 118.935 ;
     RECT  2.16 119.205 96.12 119.475 ;
     RECT  2.16 119.745 96.12 120.015 ;
     RECT  2.16 120.285 96.12 120.555 ;
     RECT  2.16 120.825 96.12 121.095 ;
     RECT  2.16 121.365 96.12 121.635 ;
     RECT  2.16 121.905 96.12 122.175 ;
     RECT  2.16 122.445 96.12 122.715 ;
     RECT  2.16 122.985 96.12 123.255 ;
     RECT  2.16 123.525 96.12 123.795 ;
     RECT  2.16 124.065 96.12 124.335 ;
     RECT  2.16 124.605 96.12 124.875 ;
     RECT  2.16 125.145 96.12 125.415 ;
     RECT  2.16 125.685 96.12 125.955 ;
     RECT  2.16 126.225 96.12 126.495 ;
     RECT  2.16 126.765 96.12 127.035 ;
     RECT  2.16 127.305 96.12 127.44 ;
     RECT  2.16 127.44 41.148 127.575 ;
     RECT  77.22 127.44 96.12 127.575 ;
     RECT  2.16 127.845 41.148 128.115 ;
     RECT  77.22 127.845 96.12 128.115 ;
     RECT  2.16 128.385 41.148 128.655 ;
     RECT  77.22 128.385 96.12 128.655 ;
     RECT  2.16 128.925 41.148 129.195 ;
     RECT  77.22 128.925 96.12 129.195 ;
     RECT  2.16 129.465 41.148 129.735 ;
     RECT  77.22 129.465 96.12 129.735 ;
     RECT  2.16 130.005 41.148 130.275 ;
     RECT  77.22 130.005 96.12 130.275 ;
     RECT  2.16 130.545 41.148 130.815 ;
     RECT  77.22 130.545 96.12 130.815 ;
     RECT  2.16 131.085 41.148 131.355 ;
     RECT  77.22 131.085 96.12 131.355 ;
     RECT  2.16 131.625 41.148 131.895 ;
     RECT  77.22 131.625 96.12 131.895 ;
     RECT  2.16 132.165 41.148 132.435 ;
     RECT  77.22 132.165 96.12 132.435 ;
     RECT  2.16 132.705 41.148 132.975 ;
     RECT  77.22 132.705 96.12 132.975 ;
     RECT  2.16 133.245 41.148 133.515 ;
     RECT  77.22 133.245 96.12 133.515 ;
     RECT  2.16 133.785 41.148 134.055 ;
     RECT  77.22 133.785 96.12 134.055 ;
     RECT  2.16 134.325 41.148 134.595 ;
     RECT  77.22 134.325 96.12 134.595 ;
     RECT  2.16 134.865 41.148 135.135 ;
     RECT  77.22 134.865 96.12 135.135 ;
     RECT  2.16 135.405 41.148 135.675 ;
     RECT  77.22 135.405 96.12 135.675 ;
     RECT  2.16 135.945 41.148 136.215 ;
     RECT  77.22 135.945 96.12 136.215 ;
     RECT  2.16 136.485 41.148 136.755 ;
     RECT  77.22 136.485 96.12 136.755 ;
     RECT  2.16 137.025 41.148 137.295 ;
     RECT  77.22 137.025 96.12 137.295 ;
     RECT  2.16 137.565 41.148 137.835 ;
     RECT  77.22 137.565 96.12 137.835 ;
     RECT  2.16 138.105 41.148 138.375 ;
     RECT  77.22 138.105 96.12 138.375 ;
     RECT  2.16 138.645 41.148 138.915 ;
     RECT  77.22 138.645 96.12 138.915 ;
     RECT  2.16 139.185 41.148 139.455 ;
     RECT  77.22 139.185 96.12 139.455 ;
     RECT  2.16 139.725 41.148 139.995 ;
     RECT  77.22 139.725 96.12 139.995 ;
     RECT  2.16 140.265 41.148 140.535 ;
     RECT  77.22 140.265 96.12 140.535 ;
     RECT  2.16 140.805 41.148 141.075 ;
     RECT  77.22 140.805 96.12 141.075 ;
     RECT  2.16 141.345 41.148 141.615 ;
     RECT  77.22 141.345 96.12 141.615 ;
     RECT  2.16 141.885 41.148 142.155 ;
     RECT  77.22 141.885 96.12 142.155 ;
     RECT  2.16 142.425 41.148 142.695 ;
     RECT  77.22 142.425 96.12 142.695 ;
     RECT  2.16 142.965 41.148 143.235 ;
     RECT  77.22 142.965 96.12 143.235 ;
     RECT  2.16 143.505 41.148 143.775 ;
     RECT  77.22 143.505 96.12 143.775 ;
     RECT  2.16 144.045 41.148 144.315 ;
     RECT  77.22 144.045 96.12 144.315 ;
     RECT  2.16 144.585 41.148 144.855 ;
     RECT  77.22 144.585 96.12 144.855 ;
     RECT  2.16 145.125 41.148 145.395 ;
     RECT  77.22 145.125 96.12 145.395 ;
     RECT  2.16 145.665 41.148 145.935 ;
     RECT  77.22 145.665 96.12 145.935 ;
     RECT  2.16 146.205 41.148 146.475 ;
     RECT  77.22 146.205 96.12 146.475 ;
     RECT  2.16 146.745 41.148 147.015 ;
     RECT  77.22 146.745 96.12 147.015 ;
     RECT  2.16 147.285 41.148 147.555 ;
     RECT  77.22 147.285 96.12 147.555 ;
     RECT  2.16 147.825 41.148 148.095 ;
     RECT  77.22 147.825 96.12 148.095 ;
     RECT  2.16 148.365 41.148 148.635 ;
     RECT  77.22 148.365 96.12 148.635 ;
     RECT  2.16 148.905 41.148 149.04 ;
     RECT  77.22 148.905 96.12 149.04 ;
     RECT  2.16 149.04 96.12 149.175 ;
     RECT  2.16 149.445 96.12 149.715 ;
     RECT  2.16 149.985 96.12 150.255 ;
     RECT  2.16 150.525 96.12 150.795 ;
     RECT  2.16 151.065 96.12 151.335 ;
     RECT  2.16 151.605 96.12 151.875 ;
     RECT  2.16 152.145 96.12 152.415 ;
     RECT  2.16 152.685 96.12 152.955 ;
     RECT  2.16 153.225 96.12 153.495 ;
     RECT  2.16 153.765 96.12 154.035 ;
     RECT  2.16 154.305 96.12 154.575 ;
     RECT  2.16 154.845 96.12 155.115 ;
     RECT  2.16 155.385 96.12 155.655 ;
     RECT  2.16 155.925 96.12 156.195 ;
     RECT  2.16 156.465 96.12 156.735 ;
     RECT  2.16 157.005 96.12 157.275 ;
     RECT  2.16 157.545 96.12 157.815 ;
     RECT  2.16 158.085 96.12 158.355 ;
     RECT  2.16 158.625 96.12 158.895 ;
     RECT  2.16 159.165 96.12 159.435 ;
     RECT  2.16 159.705 96.12 159.975 ;
     RECT  2.16 160.245 96.12 160.515 ;
     RECT  2.16 160.785 96.12 161.055 ;
     RECT  2.16 161.325 96.12 161.595 ;
     RECT  2.16 161.865 96.12 162.135 ;
     RECT  2.16 162.405 96.12 162.675 ;
     RECT  2.16 162.945 96.12 163.215 ;
     RECT  2.16 163.485 96.12 163.755 ;
     RECT  2.16 164.025 96.12 164.295 ;
     RECT  2.16 164.565 96.12 164.835 ;
     RECT  2.16 165.105 96.12 165.375 ;
     RECT  2.16 165.645 96.12 165.915 ;
     RECT  2.16 166.185 96.12 166.455 ;
     RECT  2.16 166.725 96.12 166.995 ;
     RECT  2.16 167.265 96.12 167.535 ;
     RECT  2.16 167.805 96.12 168.075 ;
     RECT  2.16 168.345 96.12 168.48 ;
    LAYER RVTP ;
     RECT  2.16 2.295 96.12 2.565 ;
     RECT  2.16 2.835 96.12 3.105 ;
     RECT  2.16 3.375 96.12 3.645 ;
     RECT  2.16 3.915 96.12 4.185 ;
     RECT  2.16 4.455 96.12 4.725 ;
     RECT  2.16 4.995 96.12 5.265 ;
     RECT  2.16 5.535 96.12 5.805 ;
     RECT  2.16 6.075 96.12 6.345 ;
     RECT  2.16 6.615 96.12 6.885 ;
     RECT  2.16 7.155 96.12 7.425 ;
     RECT  2.16 7.695 96.12 7.965 ;
     RECT  2.16 8.235 96.12 8.505 ;
     RECT  2.16 8.775 96.12 9.045 ;
     RECT  2.16 9.315 96.12 9.585 ;
     RECT  2.16 9.855 96.12 10.125 ;
     RECT  2.16 10.395 96.12 10.665 ;
     RECT  2.16 10.935 96.12 11.205 ;
     RECT  2.16 11.475 96.12 11.745 ;
     RECT  2.16 12.015 96.12 12.285 ;
     RECT  2.16 12.555 96.12 12.825 ;
     RECT  2.16 13.095 96.12 13.365 ;
     RECT  2.16 13.635 96.12 13.905 ;
     RECT  2.16 14.175 96.12 14.445 ;
     RECT  2.16 14.715 96.12 14.985 ;
     RECT  2.16 15.255 96.12 15.525 ;
     RECT  2.16 15.795 96.12 16.065 ;
     RECT  2.16 16.335 96.12 16.605 ;
     RECT  2.16 16.875 96.12 17.145 ;
     RECT  2.16 17.415 96.12 17.685 ;
     RECT  2.16 17.955 96.12 18.225 ;
     RECT  2.16 18.495 96.12 18.765 ;
     RECT  2.16 19.035 96.12 19.305 ;
     RECT  2.16 19.575 96.12 19.845 ;
     RECT  2.16 20.115 96.12 20.385 ;
     RECT  2.16 20.655 96.12 20.925 ;
     RECT  2.16 21.195 96.12 21.465 ;
     RECT  2.16 21.735 96.12 22.005 ;
     RECT  2.16 22.275 96.12 22.545 ;
     RECT  2.16 22.815 96.12 23.085 ;
     RECT  2.16 23.355 96.12 23.625 ;
     RECT  2.16 23.895 96.12 24.165 ;
     RECT  2.16 24.435 96.12 24.705 ;
     RECT  2.16 24.975 96.12 25.245 ;
     RECT  2.16 25.515 96.12 25.785 ;
     RECT  2.16 26.055 96.12 26.325 ;
     RECT  2.16 26.595 96.12 26.865 ;
     RECT  2.16 27.135 96.12 27.405 ;
     RECT  2.16 27.675 96.12 27.945 ;
     RECT  2.16 28.215 96.12 28.485 ;
     RECT  2.16 28.755 96.12 29.025 ;
     RECT  2.16 29.295 96.12 29.565 ;
     RECT  2.16 29.835 96.12 30.105 ;
     RECT  2.16 30.375 96.12 30.645 ;
     RECT  2.16 30.915 96.12 31.185 ;
     RECT  2.16 31.455 96.12 31.725 ;
     RECT  2.16 31.995 96.12 32.265 ;
     RECT  2.16 32.535 96.12 32.805 ;
     RECT  2.16 33.075 96.12 33.345 ;
     RECT  2.16 33.615 96.12 33.885 ;
     RECT  2.16 34.155 96.12 34.425 ;
     RECT  2.16 34.695 96.12 34.965 ;
     RECT  2.16 35.235 96.12 35.505 ;
     RECT  2.16 35.775 96.12 36.045 ;
     RECT  2.16 36.315 96.12 36.585 ;
     RECT  2.16 36.855 96.12 37.125 ;
     RECT  2.16 37.395 96.12 37.665 ;
     RECT  2.16 37.935 96.12 38.205 ;
     RECT  2.16 38.475 96.12 38.745 ;
     RECT  2.16 39.015 96.12 39.285 ;
     RECT  2.16 39.555 96.12 39.825 ;
     RECT  2.16 40.095 96.12 40.365 ;
     RECT  2.16 40.635 96.12 40.905 ;
     RECT  2.16 41.175 41.148 41.445 ;
     RECT  77.22 41.175 96.12 41.445 ;
     RECT  2.16 41.715 41.148 41.985 ;
     RECT  77.22 41.715 96.12 41.985 ;
     RECT  2.16 42.255 41.148 42.525 ;
     RECT  77.22 42.255 96.12 42.525 ;
     RECT  2.16 42.795 41.148 43.065 ;
     RECT  77.22 42.795 96.12 43.065 ;
     RECT  2.16 43.335 41.148 43.605 ;
     RECT  77.22 43.335 96.12 43.605 ;
     RECT  2.16 43.875 41.148 44.145 ;
     RECT  77.22 43.875 96.12 44.145 ;
     RECT  2.16 44.415 41.148 44.685 ;
     RECT  77.22 44.415 96.12 44.685 ;
     RECT  2.16 44.955 41.148 45.225 ;
     RECT  77.22 44.955 96.12 45.225 ;
     RECT  2.16 45.495 41.148 45.765 ;
     RECT  77.22 45.495 96.12 45.765 ;
     RECT  2.16 46.035 41.148 46.305 ;
     RECT  77.22 46.035 96.12 46.305 ;
     RECT  2.16 46.575 41.148 46.845 ;
     RECT  77.22 46.575 96.12 46.845 ;
     RECT  2.16 47.115 41.148 47.385 ;
     RECT  77.22 47.115 96.12 47.385 ;
     RECT  2.16 47.655 41.148 47.925 ;
     RECT  77.22 47.655 96.12 47.925 ;
     RECT  2.16 48.195 41.148 48.465 ;
     RECT  77.22 48.195 96.12 48.465 ;
     RECT  2.16 48.735 41.148 49.005 ;
     RECT  77.22 48.735 96.12 49.005 ;
     RECT  2.16 49.275 41.148 49.545 ;
     RECT  77.22 49.275 96.12 49.545 ;
     RECT  2.16 49.815 41.148 50.085 ;
     RECT  77.22 49.815 96.12 50.085 ;
     RECT  2.16 50.355 41.148 50.625 ;
     RECT  77.22 50.355 96.12 50.625 ;
     RECT  2.16 50.895 41.148 51.165 ;
     RECT  77.22 50.895 96.12 51.165 ;
     RECT  2.16 51.435 41.148 51.705 ;
     RECT  77.22 51.435 96.12 51.705 ;
     RECT  2.16 51.975 41.148 52.245 ;
     RECT  77.22 51.975 96.12 52.245 ;
     RECT  2.16 52.515 41.148 52.785 ;
     RECT  77.22 52.515 96.12 52.785 ;
     RECT  2.16 53.055 41.148 53.325 ;
     RECT  77.22 53.055 96.12 53.325 ;
     RECT  2.16 53.595 41.148 53.865 ;
     RECT  77.22 53.595 96.12 53.865 ;
     RECT  2.16 54.135 41.148 54.405 ;
     RECT  77.22 54.135 96.12 54.405 ;
     RECT  2.16 54.675 41.148 54.945 ;
     RECT  77.22 54.675 96.12 54.945 ;
     RECT  2.16 55.215 41.148 55.485 ;
     RECT  77.22 55.215 96.12 55.485 ;
     RECT  2.16 55.755 41.148 56.025 ;
     RECT  77.22 55.755 96.12 56.025 ;
     RECT  2.16 56.295 41.148 56.565 ;
     RECT  77.22 56.295 96.12 56.565 ;
     RECT  2.16 56.835 41.148 57.105 ;
     RECT  77.22 56.835 96.12 57.105 ;
     RECT  2.16 57.375 41.148 57.645 ;
     RECT  77.22 57.375 96.12 57.645 ;
     RECT  2.16 57.915 41.148 58.185 ;
     RECT  77.22 57.915 96.12 58.185 ;
     RECT  2.16 58.455 41.148 58.725 ;
     RECT  77.22 58.455 96.12 58.725 ;
     RECT  2.16 58.995 41.148 59.265 ;
     RECT  77.22 58.995 96.12 59.265 ;
     RECT  2.16 59.535 41.148 59.805 ;
     RECT  77.22 59.535 96.12 59.805 ;
     RECT  2.16 60.075 41.148 60.345 ;
     RECT  77.22 60.075 96.12 60.345 ;
     RECT  2.16 60.615 41.148 60.885 ;
     RECT  77.22 60.615 96.12 60.885 ;
     RECT  2.16 61.155 41.148 61.425 ;
     RECT  77.22 61.155 96.12 61.425 ;
     RECT  2.16 61.695 41.148 61.965 ;
     RECT  77.22 61.695 96.12 61.965 ;
     RECT  2.16 62.235 41.148 62.505 ;
     RECT  77.22 62.235 96.12 62.505 ;
     RECT  2.16 62.775 96.12 63.045 ;
     RECT  2.16 63.315 96.12 63.585 ;
     RECT  2.16 63.855 96.12 64.125 ;
     RECT  2.16 64.395 96.12 64.665 ;
     RECT  2.16 64.935 96.12 65.205 ;
     RECT  2.16 65.475 96.12 65.745 ;
     RECT  2.16 66.015 96.12 66.285 ;
     RECT  2.16 66.555 96.12 66.825 ;
     RECT  2.16 67.095 96.12 67.365 ;
     RECT  2.16 67.635 96.12 67.905 ;
     RECT  2.16 68.175 96.12 68.445 ;
     RECT  2.16 68.715 96.12 68.985 ;
     RECT  2.16 69.255 96.12 69.525 ;
     RECT  2.16 69.795 96.12 70.065 ;
     RECT  2.16 70.335 96.12 70.605 ;
     RECT  2.16 70.875 96.12 71.145 ;
     RECT  2.16 71.415 96.12 71.685 ;
     RECT  2.16 71.955 96.12 72.225 ;
     RECT  2.16 72.495 96.12 72.765 ;
     RECT  2.16 73.035 96.12 73.305 ;
     RECT  2.16 73.575 96.12 73.845 ;
     RECT  2.16 74.115 96.12 74.385 ;
     RECT  2.16 74.655 96.12 74.925 ;
     RECT  2.16 75.195 96.12 75.465 ;
     RECT  2.16 75.735 96.12 76.005 ;
     RECT  2.16 76.275 96.12 76.545 ;
     RECT  2.16 76.815 96.12 77.085 ;
     RECT  2.16 77.355 96.12 77.625 ;
     RECT  2.16 77.895 96.12 78.165 ;
     RECT  2.16 78.435 96.12 78.705 ;
     RECT  2.16 78.975 96.12 79.245 ;
     RECT  2.16 79.515 96.12 79.785 ;
     RECT  2.16 80.055 96.12 80.325 ;
     RECT  2.16 80.595 96.12 80.865 ;
     RECT  2.16 81.135 96.12 81.405 ;
     RECT  2.16 81.675 96.12 81.945 ;
     RECT  2.16 82.215 96.12 82.485 ;
     RECT  2.16 82.755 96.12 83.025 ;
     RECT  2.16 83.295 96.12 83.565 ;
     RECT  2.16 83.835 96.12 84.105 ;
     RECT  2.16 84.375 41.148 84.645 ;
     RECT  77.22 84.375 96.12 84.645 ;
     RECT  2.16 84.915 41.148 85.185 ;
     RECT  77.22 84.915 96.12 85.185 ;
     RECT  2.16 85.455 41.148 85.725 ;
     RECT  77.22 85.455 96.12 85.725 ;
     RECT  2.16 85.995 41.148 86.265 ;
     RECT  77.22 85.995 96.12 86.265 ;
     RECT  2.16 86.535 41.148 86.805 ;
     RECT  77.22 86.535 96.12 86.805 ;
     RECT  2.16 87.075 41.148 87.345 ;
     RECT  77.22 87.075 96.12 87.345 ;
     RECT  2.16 87.615 41.148 87.885 ;
     RECT  77.22 87.615 96.12 87.885 ;
     RECT  2.16 88.155 41.148 88.425 ;
     RECT  77.22 88.155 96.12 88.425 ;
     RECT  2.16 88.695 41.148 88.965 ;
     RECT  77.22 88.695 96.12 88.965 ;
     RECT  2.16 89.235 41.148 89.505 ;
     RECT  77.22 89.235 96.12 89.505 ;
     RECT  2.16 89.775 41.148 90.045 ;
     RECT  77.22 89.775 96.12 90.045 ;
     RECT  2.16 90.315 41.148 90.585 ;
     RECT  77.22 90.315 96.12 90.585 ;
     RECT  2.16 90.855 41.148 91.125 ;
     RECT  77.22 90.855 96.12 91.125 ;
     RECT  2.16 91.395 41.148 91.665 ;
     RECT  77.22 91.395 96.12 91.665 ;
     RECT  2.16 91.935 41.148 92.205 ;
     RECT  77.22 91.935 96.12 92.205 ;
     RECT  2.16 92.475 41.148 92.745 ;
     RECT  77.22 92.475 96.12 92.745 ;
     RECT  2.16 93.015 41.148 93.285 ;
     RECT  77.22 93.015 96.12 93.285 ;
     RECT  2.16 93.555 41.148 93.825 ;
     RECT  77.22 93.555 96.12 93.825 ;
     RECT  2.16 94.095 41.148 94.365 ;
     RECT  77.22 94.095 96.12 94.365 ;
     RECT  2.16 94.635 41.148 94.905 ;
     RECT  77.22 94.635 96.12 94.905 ;
     RECT  2.16 95.175 41.148 95.445 ;
     RECT  77.22 95.175 96.12 95.445 ;
     RECT  2.16 95.715 41.148 95.985 ;
     RECT  77.22 95.715 96.12 95.985 ;
     RECT  2.16 96.255 41.148 96.525 ;
     RECT  77.22 96.255 96.12 96.525 ;
     RECT  2.16 96.795 41.148 97.065 ;
     RECT  77.22 96.795 96.12 97.065 ;
     RECT  2.16 97.335 41.148 97.605 ;
     RECT  77.22 97.335 96.12 97.605 ;
     RECT  2.16 97.875 41.148 98.145 ;
     RECT  77.22 97.875 96.12 98.145 ;
     RECT  2.16 98.415 41.148 98.685 ;
     RECT  77.22 98.415 96.12 98.685 ;
     RECT  2.16 98.955 41.148 99.225 ;
     RECT  77.22 98.955 96.12 99.225 ;
     RECT  2.16 99.495 41.148 99.765 ;
     RECT  77.22 99.495 96.12 99.765 ;
     RECT  2.16 100.035 41.148 100.305 ;
     RECT  77.22 100.035 96.12 100.305 ;
     RECT  2.16 100.575 41.148 100.845 ;
     RECT  77.22 100.575 96.12 100.845 ;
     RECT  2.16 101.115 41.148 101.385 ;
     RECT  77.22 101.115 96.12 101.385 ;
     RECT  2.16 101.655 41.148 101.925 ;
     RECT  77.22 101.655 96.12 101.925 ;
     RECT  2.16 102.195 41.148 102.465 ;
     RECT  77.22 102.195 96.12 102.465 ;
     RECT  2.16 102.735 41.148 103.005 ;
     RECT  77.22 102.735 96.12 103.005 ;
     RECT  2.16 103.275 41.148 103.545 ;
     RECT  77.22 103.275 96.12 103.545 ;
     RECT  2.16 103.815 41.148 104.085 ;
     RECT  77.22 103.815 96.12 104.085 ;
     RECT  2.16 104.355 41.148 104.625 ;
     RECT  77.22 104.355 96.12 104.625 ;
     RECT  2.16 104.895 41.148 105.165 ;
     RECT  77.22 104.895 96.12 105.165 ;
     RECT  2.16 105.435 41.148 105.705 ;
     RECT  77.22 105.435 96.12 105.705 ;
     RECT  2.16 105.975 96.12 106.245 ;
     RECT  2.16 106.515 96.12 106.785 ;
     RECT  2.16 107.055 96.12 107.325 ;
     RECT  2.16 107.595 96.12 107.865 ;
     RECT  2.16 108.135 96.12 108.405 ;
     RECT  2.16 108.675 96.12 108.945 ;
     RECT  2.16 109.215 96.12 109.485 ;
     RECT  2.16 109.755 96.12 110.025 ;
     RECT  2.16 110.295 96.12 110.565 ;
     RECT  2.16 110.835 96.12 111.105 ;
     RECT  2.16 111.375 96.12 111.645 ;
     RECT  2.16 111.915 96.12 112.185 ;
     RECT  2.16 112.455 96.12 112.725 ;
     RECT  2.16 112.995 96.12 113.265 ;
     RECT  2.16 113.535 96.12 113.805 ;
     RECT  2.16 114.075 96.12 114.345 ;
     RECT  2.16 114.615 96.12 114.885 ;
     RECT  2.16 115.155 96.12 115.425 ;
     RECT  2.16 115.695 96.12 115.965 ;
     RECT  2.16 116.235 96.12 116.505 ;
     RECT  2.16 116.775 96.12 117.045 ;
     RECT  2.16 117.315 96.12 117.585 ;
     RECT  2.16 117.855 96.12 118.125 ;
     RECT  2.16 118.395 96.12 118.665 ;
     RECT  2.16 118.935 96.12 119.205 ;
     RECT  2.16 119.475 96.12 119.745 ;
     RECT  2.16 120.015 96.12 120.285 ;
     RECT  2.16 120.555 96.12 120.825 ;
     RECT  2.16 121.095 96.12 121.365 ;
     RECT  2.16 121.635 96.12 121.905 ;
     RECT  2.16 122.175 96.12 122.445 ;
     RECT  2.16 122.715 96.12 122.985 ;
     RECT  2.16 123.255 96.12 123.525 ;
     RECT  2.16 123.795 96.12 124.065 ;
     RECT  2.16 124.335 96.12 124.605 ;
     RECT  2.16 124.875 96.12 125.145 ;
     RECT  2.16 125.415 96.12 125.685 ;
     RECT  2.16 125.955 96.12 126.225 ;
     RECT  2.16 126.495 96.12 126.765 ;
     RECT  2.16 127.035 96.12 127.305 ;
     RECT  2.16 127.575 41.148 127.845 ;
     RECT  77.22 127.575 96.12 127.845 ;
     RECT  2.16 128.115 41.148 128.385 ;
     RECT  77.22 128.115 96.12 128.385 ;
     RECT  2.16 128.655 41.148 128.925 ;
     RECT  77.22 128.655 96.12 128.925 ;
     RECT  2.16 129.195 41.148 129.465 ;
     RECT  77.22 129.195 96.12 129.465 ;
     RECT  2.16 129.735 41.148 130.005 ;
     RECT  77.22 129.735 96.12 130.005 ;
     RECT  2.16 130.275 41.148 130.545 ;
     RECT  77.22 130.275 96.12 130.545 ;
     RECT  2.16 130.815 41.148 131.085 ;
     RECT  77.22 130.815 96.12 131.085 ;
     RECT  2.16 131.355 41.148 131.625 ;
     RECT  77.22 131.355 96.12 131.625 ;
     RECT  2.16 131.895 41.148 132.165 ;
     RECT  77.22 131.895 96.12 132.165 ;
     RECT  2.16 132.435 41.148 132.705 ;
     RECT  77.22 132.435 96.12 132.705 ;
     RECT  2.16 132.975 41.148 133.245 ;
     RECT  77.22 132.975 96.12 133.245 ;
     RECT  2.16 133.515 41.148 133.785 ;
     RECT  77.22 133.515 96.12 133.785 ;
     RECT  2.16 134.055 41.148 134.325 ;
     RECT  77.22 134.055 96.12 134.325 ;
     RECT  2.16 134.595 41.148 134.865 ;
     RECT  77.22 134.595 96.12 134.865 ;
     RECT  2.16 135.135 41.148 135.405 ;
     RECT  77.22 135.135 96.12 135.405 ;
     RECT  2.16 135.675 41.148 135.945 ;
     RECT  77.22 135.675 96.12 135.945 ;
     RECT  2.16 136.215 41.148 136.485 ;
     RECT  77.22 136.215 96.12 136.485 ;
     RECT  2.16 136.755 41.148 137.025 ;
     RECT  77.22 136.755 96.12 137.025 ;
     RECT  2.16 137.295 41.148 137.565 ;
     RECT  77.22 137.295 96.12 137.565 ;
     RECT  2.16 137.835 41.148 138.105 ;
     RECT  77.22 137.835 96.12 138.105 ;
     RECT  2.16 138.375 41.148 138.645 ;
     RECT  77.22 138.375 96.12 138.645 ;
     RECT  2.16 138.915 41.148 139.185 ;
     RECT  77.22 138.915 96.12 139.185 ;
     RECT  2.16 139.455 41.148 139.725 ;
     RECT  77.22 139.455 96.12 139.725 ;
     RECT  2.16 139.995 41.148 140.265 ;
     RECT  77.22 139.995 96.12 140.265 ;
     RECT  2.16 140.535 41.148 140.805 ;
     RECT  77.22 140.535 96.12 140.805 ;
     RECT  2.16 141.075 41.148 141.345 ;
     RECT  77.22 141.075 96.12 141.345 ;
     RECT  2.16 141.615 41.148 141.885 ;
     RECT  77.22 141.615 96.12 141.885 ;
     RECT  2.16 142.155 41.148 142.425 ;
     RECT  77.22 142.155 96.12 142.425 ;
     RECT  2.16 142.695 41.148 142.965 ;
     RECT  77.22 142.695 96.12 142.965 ;
     RECT  2.16 143.235 41.148 143.505 ;
     RECT  77.22 143.235 96.12 143.505 ;
     RECT  2.16 143.775 41.148 144.045 ;
     RECT  77.22 143.775 96.12 144.045 ;
     RECT  2.16 144.315 41.148 144.585 ;
     RECT  77.22 144.315 96.12 144.585 ;
     RECT  2.16 144.855 41.148 145.125 ;
     RECT  77.22 144.855 96.12 145.125 ;
     RECT  2.16 145.395 41.148 145.665 ;
     RECT  77.22 145.395 96.12 145.665 ;
     RECT  2.16 145.935 41.148 146.205 ;
     RECT  77.22 145.935 96.12 146.205 ;
     RECT  2.16 146.475 41.148 146.745 ;
     RECT  77.22 146.475 96.12 146.745 ;
     RECT  2.16 147.015 41.148 147.285 ;
     RECT  77.22 147.015 96.12 147.285 ;
     RECT  2.16 147.555 41.148 147.825 ;
     RECT  77.22 147.555 96.12 147.825 ;
     RECT  2.16 148.095 41.148 148.365 ;
     RECT  77.22 148.095 96.12 148.365 ;
     RECT  2.16 148.635 41.148 148.905 ;
     RECT  77.22 148.635 96.12 148.905 ;
     RECT  2.16 149.175 96.12 149.445 ;
     RECT  2.16 149.715 96.12 149.985 ;
     RECT  2.16 150.255 96.12 150.525 ;
     RECT  2.16 150.795 96.12 151.065 ;
     RECT  2.16 151.335 96.12 151.605 ;
     RECT  2.16 151.875 96.12 152.145 ;
     RECT  2.16 152.415 96.12 152.685 ;
     RECT  2.16 152.955 96.12 153.225 ;
     RECT  2.16 153.495 96.12 153.765 ;
     RECT  2.16 154.035 96.12 154.305 ;
     RECT  2.16 154.575 96.12 154.845 ;
     RECT  2.16 155.115 96.12 155.385 ;
     RECT  2.16 155.655 96.12 155.925 ;
     RECT  2.16 156.195 96.12 156.465 ;
     RECT  2.16 156.735 96.12 157.005 ;
     RECT  2.16 157.275 96.12 157.545 ;
     RECT  2.16 157.815 96.12 158.085 ;
     RECT  2.16 158.355 96.12 158.625 ;
     RECT  2.16 158.895 96.12 159.165 ;
     RECT  2.16 159.435 96.12 159.705 ;
     RECT  2.16 159.975 96.12 160.245 ;
     RECT  2.16 160.515 96.12 160.785 ;
     RECT  2.16 161.055 96.12 161.325 ;
     RECT  2.16 161.595 96.12 161.865 ;
     RECT  2.16 162.135 96.12 162.405 ;
     RECT  2.16 162.675 96.12 162.945 ;
     RECT  2.16 163.215 96.12 163.485 ;
     RECT  2.16 163.755 96.12 164.025 ;
     RECT  2.16 164.295 96.12 164.565 ;
     RECT  2.16 164.835 96.12 165.105 ;
     RECT  2.16 165.375 96.12 165.645 ;
     RECT  2.16 165.915 96.12 166.185 ;
     RECT  2.16 166.455 96.12 166.725 ;
     RECT  2.16 166.995 96.12 167.265 ;
     RECT  2.16 167.535 96.12 167.805 ;
     RECT  2.16 168.075 96.12 168.345 ;
    LAYER M1 ;
     RECT  2.16 2.151 96.12 41.049 ;
     RECT  43.2 43.2 75.192 60.504 ;
     RECT  2.16 41.049 41.148 62.631 ;
     RECT  77.22 41.049 96.12 62.631 ;
     RECT  2.16 62.631 96.12 84.249 ;
     RECT  43.2 86.4 75.192 103.704 ;
     RECT  2.16 84.249 41.148 105.831 ;
     RECT  77.22 84.249 96.12 105.831 ;
     RECT  2.16 105.831 96.12 127.449 ;
     RECT  43.2 129.6 75.192 146.904 ;
     RECT  2.16 127.449 41.148 149.031 ;
     RECT  77.22 127.449 96.12 149.031 ;
     RECT  2.16 149.031 96.12 168.489 ;
    LAYER M2 ;
     RECT  0.103 119.556 0.275 121.734 ;
     RECT  0.103 42.066 0.535 42.084 ;
     RECT  0.103 43.308 0.535 44.514 ;
     RECT  0.103 31.806 2.16 31.824 ;
     RECT  0.103 33.048 2.16 34.146 ;
     RECT  0.103 35.856 2.16 35.874 ;
     RECT  0.535 40.986 2.16 41.004 ;
     RECT  0.535 41.994 2.16 44.946 ;
     RECT  0.103 74.466 2.16 75.564 ;
     RECT  0.103 76.626 2.16 77.184 ;
     RECT  0.103 78.606 2.16 78.624 ;
     RECT  0.103 84.726 2.16 84.744 ;
     RECT  0.535 86.346 2.16 86.904 ;
     RECT  0.103 87.696 2.16 88.254 ;
     RECT  0.103 118.134 2.16 118.764 ;
     RECT  0.275 119.556 2.16 119.574 ;
     RECT  0.275 120.636 2.16 121.734 ;
     RECT  0.103 131.058 2.16 131.076 ;
     RECT  37.831 170.586 37.903 170.604 ;
     RECT  37.903 170.514 38.003 170.604 ;
     RECT  38.003 170.586 38.471 170.604 ;
     RECT  2.16 2.151 38.587 168.489 ;
     RECT  38.587 2.151 38.687 168.714 ;
     RECT  38.687 2.151 41.148 168.489 ;
     RECT  41.148 57.816 41.351 58.014 ;
     RECT  41.148 93.906 41.351 100.134 ;
     RECT  41.148 131.328 41.351 131.346 ;
     RECT  41.148 144.216 41.351 144.414 ;
     RECT  41.148 50.904 41.423 56.214 ;
     RECT  41.351 57.996 41.423 58.014 ;
     RECT  41.351 93.906 41.459 96.444 ;
     RECT  41.148 137.34 41.459 140.094 ;
     RECT  41.351 97.308 41.531 100.134 ;
     RECT  41.459 137.34 41.567 139.914 ;
     RECT  41.148 140.976 41.603 142.452 ;
     RECT  41.148 134.262 41.639 135.666 ;
     RECT  41.148 45.234 41.675 47.682 ;
     RECT  41.675 45.432 41.747 47.682 ;
     RECT  41.148 49.014 41.747 50.148 ;
     RECT  41.148 129.132 41.747 129.456 ;
     RECT  41.148 130.356 41.783 130.536 ;
     RECT  41.783 130.446 41.819 130.536 ;
     RECT  41.747 129.132 41.891 129.294 ;
     RECT  41.148 101.556 41.927 101.754 ;
     RECT  41.148 60.552 41.935 61.452 ;
     RECT  41.423 50.904 41.963 56.124 ;
     RECT  41.531 97.416 41.999 100.134 ;
     RECT  41.148 87.084 42.035 92.808 ;
     RECT  41.927 101.736 42.071 101.754 ;
     RECT  41.567 137.34 42.143 139.644 ;
     RECT  41.963 50.904 42.179 55.944 ;
     RECT  41.459 93.906 42.179 96.084 ;
     RECT  42.143 137.34 42.179 139.554 ;
     RECT  41.747 45.432 42.215 46.602 ;
     RECT  41.747 47.43 42.215 47.682 ;
     RECT  42.035 88.902 42.215 92.808 ;
     RECT  41.639 134.262 42.215 134.892 ;
     RECT  41.639 135.648 42.215 135.666 ;
     RECT  42.179 137.34 42.215 137.358 ;
     RECT  41.351 144.396 42.215 144.414 ;
     RECT  42.035 87.084 42.251 88.146 ;
     RECT  42.215 89.244 42.251 89.262 ;
     RECT  42.215 90.018 42.251 90.036 ;
     RECT  42.215 45.432 42.287 46.566 ;
     RECT  42.251 88.056 42.287 88.146 ;
     RECT  42.215 91.71 42.287 92.808 ;
     RECT  42.287 45.972 42.359 46.332 ;
     RECT  41.148 105.831 42.403 127.449 ;
     RECT  42.359 46.314 42.431 46.332 ;
     RECT  41.999 97.416 42.431 99.954 ;
     RECT  42.179 51.786 42.467 53.784 ;
     RECT  42.179 95.346 42.467 96.084 ;
     RECT  42.215 134.262 42.467 134.28 ;
     RECT  42.179 138.186 42.467 139.554 ;
     RECT  41.603 142.434 42.511 142.452 ;
     RECT  41.148 42.732 42.583 43.164 ;
     RECT  41.148 103.752 42.583 104.724 ;
     RECT  42.403 105.831 42.583 127.494 ;
     RECT  42.511 142.398 42.583 142.452 ;
     RECT  42.583 103.752 42.655 127.494 ;
     RECT  41.148 149.031 42.655 168.489 ;
     RECT  42.655 148.986 42.691 168.489 ;
     RECT  42.583 42.696 42.719 43.164 ;
     RECT  41.747 49.014 42.727 49.032 ;
     RECT  41.747 49.788 42.727 50.148 ;
     RECT  42.691 148.95 42.727 168.489 ;
     RECT  42.655 103.752 42.755 127.674 ;
     RECT  42.755 105.678 42.863 127.674 ;
     RECT  41.935 60.552 43.015 61.614 ;
     RECT  41.148 62.631 43.015 84.249 ;
     RECT  43.015 60.552 43.151 84.249 ;
     RECT  42.719 42.732 43.2 43.164 ;
     RECT  42.215 47.664 43.2 47.682 ;
     RECT  42.727 49.014 43.2 50.148 ;
     RECT  42.467 52.056 43.2 53.784 ;
     RECT  42.179 54.684 43.2 55.944 ;
     RECT  43.151 60.552 43.2 61.614 ;
     RECT  42.251 87.084 43.2 87.174 ;
     RECT  42.287 88.056 43.2 88.074 ;
     RECT  42.215 90.828 43.2 90.846 ;
     RECT  42.287 91.71 43.2 92.736 ;
     RECT  42.179 93.906 43.2 93.924 ;
     RECT  42.467 95.346 43.2 95.634 ;
     RECT  42.431 97.416 43.2 98.604 ;
     RECT  42.431 99.666 43.2 99.954 ;
     RECT  42.755 103.752 43.2 104.724 ;
     RECT  41.891 129.276 43.2 129.294 ;
     RECT  41.148 132.48 43.2 132.498 ;
     RECT  42.467 138.546 43.2 139.554 ;
     RECT  41.603 140.976 43.2 141.534 ;
     RECT  42.583 142.398 43.2 142.488 ;
     RECT  41.148 147.06 43.2 148.086 ;
     RECT  42.863 105.678 43.367 127.566 ;
     RECT  43.2 129.276 48.991 148.086 ;
     RECT  42.727 148.878 48.991 168.489 ;
     RECT  43.2 86.4 49.207 104.724 ;
     RECT  43.367 105.678 49.207 127.449 ;
     RECT  43.2 42.732 49.855 61.614 ;
     RECT  43.151 62.55 49.855 84.249 ;
     RECT  49.855 42.732 50.459 84.249 ;
     RECT  41.148 85.23 65.039 85.248 ;
     RECT  50.459 42.732 70.699 61.884 ;
     RECT  50.459 62.631 70.699 84.249 ;
     RECT  49.207 86.4 75.127 127.449 ;
     RECT  70.699 42.732 75.192 84.249 ;
     RECT  75.127 86.076 75.192 127.449 ;
     RECT  48.991 129.276 75.192 168.489 ;
     RECT  75.192 103.752 75.271 127.449 ;
     RECT  75.192 129.276 75.299 129.564 ;
     RECT  75.299 129.276 75.307 129.294 ;
     RECT  75.192 52.794 75.335 54.738 ;
     RECT  75.192 139.194 75.335 141.066 ;
     RECT  75.192 58.698 75.371 58.986 ;
     RECT  75.192 86.076 75.371 87.174 ;
     RECT  75.271 103.752 75.371 127.53 ;
     RECT  75.371 86.346 75.443 87.174 ;
     RECT  75.307 128.826 75.551 129.294 ;
     RECT  75.192 134.496 75.551 137.934 ;
     RECT  75.371 58.77 75.587 58.986 ;
     RECT  75.192 132.786 75.659 132.804 ;
     RECT  75.587 58.851 75.731 58.986 ;
     RECT  75.192 60.552 75.731 84.249 ;
     RECT  75.192 102.546 75.731 102.564 ;
     RECT  75.192 96.534 76.063 98.019 ;
     RECT  75.335 140.472 76.063 141.066 ;
     RECT  75.335 52.794 76.099 54.468 ;
     RECT  76.063 55.53 76.099 55.548 ;
     RECT  75.192 99.126 76.099 99.144 ;
     RECT  76.099 52.794 76.135 55.548 ;
     RECT  76.063 96.534 76.135 98.172 ;
     RECT  76.099 98.928 76.135 99.144 ;
     RECT  76.063 140.472 76.135 141.57 ;
     RECT  75.192 142.326 76.135 142.344 ;
     RECT  75.192 48.906 76.315 50.148 ;
     RECT  76.315 48.366 76.351 50.148 ;
     RECT  76.315 91.476 76.351 91.494 ;
     RECT  75.192 93.996 76.351 94.626 ;
     RECT  76.351 48.276 76.387 50.148 ;
     RECT  75.192 51.21 76.387 51.228 ;
     RECT  76.351 91.476 76.387 92.268 ;
     RECT  76.351 93.798 76.387 94.896 ;
     RECT  76.135 96.534 76.387 99.144 ;
     RECT  75.192 133.686 76.387 133.704 ;
     RECT  75.551 135.072 76.387 137.934 ;
     RECT  75.335 139.194 76.387 139.644 ;
     RECT  76.171 130.212 76.639 130.23 ;
     RECT  76.387 135.072 76.639 139.644 ;
     RECT  76.135 140.472 76.639 142.344 ;
     RECT  75.551 129.276 76.675 129.294 ;
     RECT  76.639 130.212 76.675 130.5 ;
     RECT  76.099 144.486 76.747 144.504 ;
     RECT  75.192 45.126 76.927 45.144 ;
     RECT  75.192 131.904 76.963 131.922 ;
     RECT  76.675 129.276 76.999 130.5 ;
     RECT  76.387 133.686 77.035 134.154 ;
     RECT  75.192 42.732 77.215 43.164 ;
     RECT  76.999 129.276 77.215 130.914 ;
     RECT  41.148 2.151 77.22 41.049 ;
     RECT  77.215 42.066 77.22 43.164 ;
     RECT  76.927 45.126 77.22 45.828 ;
     RECT  76.387 48.276 77.22 51.93 ;
     RECT  76.135 52.794 77.22 56.286 ;
     RECT  75.731 58.932 77.22 58.986 ;
     RECT  75.731 60.552 77.22 61.884 ;
     RECT  75.731 62.631 77.22 84.249 ;
     RECT  77.215 85.194 77.22 85.212 ;
     RECT  75.443 86.85 77.22 87.174 ;
     RECT  75.192 88.506 77.22 88.524 ;
     RECT  76.387 91.476 77.22 99.144 ;
     RECT  76.639 101.592 77.22 101.61 ;
     RECT  75.371 103.752 77.22 127.449 ;
     RECT  77.215 128.736 77.22 130.914 ;
     RECT  76.963 131.904 77.22 132.534 ;
     RECT  77.035 133.686 77.22 134.244 ;
     RECT  76.639 135.072 77.22 142.344 ;
     RECT  76.747 143.946 77.22 144.504 ;
     RECT  76.675 145.872 77.22 145.89 ;
     RECT  75.192 147.06 77.22 168.489 ;
     RECT  77.22 2.151 96.12 168.489 ;
     RECT  96.12 54.99 96.935 56.286 ;
     RECT  96.12 84.078 97.439 85.716 ;
     RECT  96.12 99.468 97.439 99.756 ;
     RECT  96.12 40.338 97.475 40.896 ;
     RECT  96.12 41.958 97.475 42.246 ;
     RECT  96.12 53.298 97.475 53.856 ;
     RECT  96.935 55.458 97.475 56.286 ;
     RECT  96.12 81.918 97.475 81.936 ;
     RECT  96.12 83.268 97.475 83.286 ;
     RECT  97.439 84.078 97.475 84.366 ;
     RECT  97.439 85.158 97.475 85.716 ;
     RECT  96.12 96.498 97.475 97.326 ;
     RECT  96.12 98.118 97.475 98.136 ;
     RECT  97.439 99.468 97.475 99.486 ;
     RECT  96.12 126.468 97.475 126.486 ;
     RECT  96.12 140.508 97.475 140.526 ;
     RECT  96.12 141.318 97.475 142.146 ;
     RECT  98.167 100.242 98.267 100.26 ;
     RECT  98.167 125.586 98.267 125.604 ;
    LAYER M3 ;
     RECT  2.415 2.143 2.505 2.413 ;
     RECT  5.115 2.143 5.205 2.413 ;
     RECT  7.815 2.143 7.905 2.413 ;
     RECT  10.515 2.143 10.605 2.413 ;
     RECT  13.215 2.143 13.305 2.413 ;
     RECT  15.915 2.143 16.005 2.413 ;
     RECT  18.615 2.143 18.705 2.413 ;
     RECT  21.315 2.143 21.405 2.413 ;
     RECT  24.015 2.143 24.105 2.413 ;
     RECT  26.715 2.143 26.805 2.413 ;
     RECT  29.415 2.143 29.505 2.413 ;
     RECT  32.115 2.143 32.205 2.413 ;
     RECT  34.815 2.143 34.905 2.413 ;
     RECT  37.515 2.143 37.605 2.413 ;
     RECT  40.215 2.143 40.305 2.413 ;
     RECT  42.915 2.143 43.005 2.413 ;
     RECT  45.615 2.143 45.705 2.413 ;
     RECT  48.315 2.143 48.405 2.413 ;
     RECT  51.015 2.143 51.105 2.413 ;
     RECT  53.715 2.143 53.805 2.413 ;
     RECT  56.415 2.143 56.505 2.413 ;
     RECT  59.115 2.143 59.205 2.413 ;
     RECT  61.815 2.143 61.905 2.413 ;
     RECT  64.515 2.143 64.605 2.413 ;
     RECT  67.215 2.143 67.305 2.413 ;
     RECT  69.915 2.143 70.005 2.413 ;
     RECT  72.615 2.143 72.705 2.413 ;
     RECT  75.315 2.143 75.405 2.413 ;
     RECT  78.015 2.143 78.105 2.413 ;
     RECT  80.715 2.143 80.805 2.413 ;
     RECT  83.415 2.143 83.505 2.413 ;
     RECT  86.115 2.143 86.205 2.413 ;
     RECT  88.815 2.143 88.905 2.413 ;
     RECT  91.515 2.143 91.605 2.413 ;
     RECT  94.215 2.143 94.305 2.413 ;
     RECT  5.115 2.413 5.397 31.801 ;
     RECT  6.48 31.621 6.498 31.801 ;
     RECT  0.108 31.675 0.126 31.819 ;
     RECT  0.108 31.819 0.162 31.829 ;
     RECT  5.115 31.801 5.562 31.891 ;
     RECT  6.48 31.801 6.786 31.891 ;
     RECT  0.144 31.829 0.162 31.949 ;
     RECT  3.744 31.657 4.302 31.963 ;
     RECT  5.115 31.891 6.786 31.963 ;
     RECT  2.415 2.413 2.697 32.059 ;
     RECT  2.415 32.059 2.79 32.099 ;
     RECT  3.744 31.963 6.786 32.189 ;
     RECT  3.744 32.189 6.066 32.251 ;
     RECT  7.815 2.413 8.097 32.269 ;
     RECT  2.415 32.099 2.697 32.395 ;
     RECT  6.804 32.233 6.894 32.431 ;
     RECT  7.815 32.269 8.118 32.431 ;
     RECT  2.304 32.395 2.697 32.459 ;
     RECT  3.42 32.251 6.066 32.459 ;
     RECT  9.396 32.341 9.414 32.459 ;
     RECT  6.804 32.431 8.118 32.467 ;
     RECT  0.18 32.683 0.198 32.813 ;
     RECT  6.804 32.467 8.658 32.971 ;
     RECT  3.744 32.459 6.066 33.151 ;
     RECT  6.804 32.971 9.198 33.151 ;
     RECT  3.744 33.151 9.198 33.241 ;
     RECT  42.915 2.413 43.197 33.349 ;
     RECT  3.708 33.241 9.198 33.539 ;
     RECT  2.415 32.459 2.697 33.547 ;
     RECT  10.515 2.413 10.797 33.961 ;
     RECT  0.108 32.827 0.126 34.151 ;
     RECT  2.304 33.547 2.697 34.219 ;
     RECT  2.304 34.219 2.79 34.465 ;
     RECT  3.708 33.539 8.658 34.465 ;
     RECT  2.304 34.465 8.658 34.501 ;
     RECT  2.304 34.501 9.414 34.619 ;
     RECT  2.304 34.619 8.838 34.925 ;
     RECT  40.215 2.413 40.497 35.041 ;
     RECT  40.215 35.041 40.626 35.131 ;
     RECT  0.144 35.131 0.162 35.261 ;
     RECT  3.42 34.925 8.838 35.339 ;
     RECT  3.456 35.339 8.838 35.429 ;
     RECT  3.528 35.429 8.838 35.501 ;
     RECT  0.108 35.707 0.126 35.879 ;
     RECT  3.6 35.501 8.838 36.085 ;
     RECT  3.6 36.085 9.162 36.239 ;
     RECT  2.304 34.925 2.697 36.269 ;
     RECT  10.515 33.961 11.106 36.625 ;
     RECT  39.6 35.131 40.626 36.751 ;
     RECT  3.6 36.239 8.838 36.779 ;
     RECT  38.772 35.941 38.79 37.085 ;
     RECT  39.6 36.751 40.95 37.363 ;
     RECT  95.904 37.435 95.922 37.579 ;
     RECT  42.192 33.349 43.197 37.939 ;
     RECT  94.215 2.413 94.497 37.963 ;
     RECT  42.12 37.939 43.197 38.101 ;
     RECT  95.76 37.579 95.922 38.101 ;
     RECT  90.648 37.963 90.666 38.141 ;
     RECT  94.215 37.963 94.59 38.203 ;
     RECT  95.364 38.101 95.922 38.429 ;
     RECT  94.032 38.203 94.59 38.779 ;
     RECT  95.364 38.429 95.85 38.779 ;
     RECT  94.032 38.779 95.85 38.813 ;
     RECT  39.024 37.363 40.95 38.821 ;
     RECT  92.88 38.713 92.898 38.821 ;
     RECT  92.88 38.821 93.222 38.939 ;
     RECT  91.515 2.413 91.797 38.983 ;
     RECT  42.048 38.101 43.197 39.083 ;
     RECT  90.036 39.019 90.054 39.091 ;
     RECT  91.512 38.983 91.797 39.091 ;
     RECT  94.032 38.813 95.778 39.091 ;
     RECT  88.815 2.413 89.097 39.289 ;
     RECT  90.036 39.091 90.666 39.289 ;
     RECT  88.815 39.289 90.666 39.325 ;
     RECT  91.512 39.091 92.574 39.325 ;
     RECT  83.415 2.413 83.697 39.451 ;
     RECT  86.115 2.413 86.397 39.487 ;
     RECT  86.115 39.487 86.706 39.523 ;
     RECT  75.315 2.413 75.597 39.631 ;
     RECT  78.015 2.413 78.297 39.631 ;
     RECT  78.015 39.631 78.678 39.749 ;
     RECT  83.16 39.451 83.697 39.757 ;
     RECT  85.788 39.523 86.706 39.785 ;
     RECT  75.168 39.631 75.597 39.793 ;
     RECT  86.115 39.785 86.706 39.857 ;
     RECT  75.168 39.793 76.086 39.865 ;
     RECT  88.815 39.325 92.574 39.883 ;
     RECT  88.815 39.883 92.61 39.901 ;
     RECT  93.456 39.091 95.778 39.901 ;
     RECT  88.815 39.901 95.778 39.931 ;
     RECT  88.815 39.931 95.922 40.019 ;
     RECT  12.312 39.991 12.33 40.027 ;
     RECT  11.952 40.027 12.33 40.064 ;
     RECT  85.032 39.991 85.05 40.091 ;
     RECT  83.088 39.757 83.697 40.199 ;
     RECT  88.815 40.019 94.698 40.199 ;
     RECT  88.815 40.199 92.61 40.289 ;
     RECT  83.415 40.199 83.697 40.297 ;
     RECT  38.772 38.821 40.95 40.441 ;
     RECT  42.084 39.083 43.197 40.441 ;
     RECT  12.312 40.064 12.33 40.445 ;
     RECT  64.515 2.413 64.797 40.531 ;
     RECT  83.415 40.297 83.934 40.559 ;
     RECT  3.708 36.779 8.838 40.595 ;
     RECT  38.772 40.441 43.197 40.703 ;
     RECT  86.115 39.857 86.634 40.703 ;
     RECT  93.384 40.199 94.698 40.703 ;
     RECT  45.615 2.413 45.897 40.711 ;
     RECT  64.515 40.531 64.926 40.711 ;
     RECT  75.096 39.865 76.086 40.711 ;
     RECT  83.415 40.559 83.862 40.739 ;
     RECT  39.024 40.703 43.197 40.787 ;
     RECT  48.315 2.413 48.597 40.787 ;
     RECT  51.015 2.413 51.297 40.787 ;
     RECT  53.715 2.413 53.997 40.787 ;
     RECT  56.415 2.413 56.697 40.787 ;
     RECT  59.115 2.413 59.397 40.787 ;
     RECT  61.815 2.413 62.097 40.787 ;
     RECT  67.215 2.413 67.497 40.787 ;
     RECT  69.915 2.413 70.197 40.787 ;
     RECT  72.615 2.413 72.897 40.787 ;
     RECT  64.515 40.711 64.962 40.801 ;
     RECT  93.528 40.703 94.698 40.801 ;
     RECT  95.508 40.019 95.922 40.801 ;
     RECT  58.104 40.555 58.122 40.829 ;
     RECT  45.615 40.711 46.242 40.837 ;
     RECT  82.656 40.639 82.674 40.837 ;
     RECT  85.14 40.711 85.158 40.865 ;
     RECT  45.615 40.837 46.314 40.877 ;
     RECT  56.415 40.787 56.574 40.877 ;
     RECT  64.515 40.801 65.25 40.877 ;
     RECT  97.452 40.171 97.47 40.901 ;
     RECT  75.096 40.711 76.446 40.945 ;
     RECT  0.54 40.891 0.558 41.009 ;
     RECT  45.615 40.877 46.242 41.009 ;
     RECT  82.08 40.837 82.674 41.009 ;
     RECT  64.515 40.877 64.962 41.021 ;
     RECT  45.615 41.009 45.705 41.057 ;
     RECT  48.315 40.787 48.405 41.057 ;
     RECT  51.015 40.787 51.105 41.057 ;
     RECT  53.715 40.787 53.805 41.057 ;
     RECT  56.415 40.877 56.505 41.057 ;
     RECT  59.115 40.787 59.205 41.057 ;
     RECT  61.815 40.787 61.905 41.057 ;
     RECT  64.515 41.021 64.605 41.057 ;
     RECT  67.215 40.787 67.305 41.057 ;
     RECT  69.915 40.787 70.005 41.057 ;
     RECT  72.615 40.787 72.705 41.057 ;
     RECT  82.08 41.009 82.098 41.099 ;
     RECT  85.068 40.873 85.086 41.099 ;
     RECT  98.1 41.035 98.118 41.165 ;
     RECT  88.815 40.289 92.574 41.449 ;
     RECT  93.528 40.801 95.922 41.449 ;
     RECT  2.415 36.269 2.697 41.467 ;
     RECT  0.144 41.035 0.162 41.611 ;
     RECT  3.96 40.595 8.838 41.755 ;
     RECT  3.924 41.755 8.838 41.791 ;
     RECT  80.715 2.413 80.997 41.791 ;
     RECT  2.304 41.467 2.697 41.819 ;
     RECT  3.42 41.791 8.838 41.909 ;
     RECT  85.356 41.611 85.374 41.909 ;
     RECT  0.108 41.611 0.162 41.989 ;
     RECT  2.415 41.819 2.697 41.989 ;
     RECT  3.42 41.909 8.694 41.989 ;
     RECT  0.108 41.989 0.558 42.089 ;
     RECT  97.452 41.755 97.47 42.251 ;
     RECT  80.064 41.791 80.997 42.529 ;
     RECT  88.056 42.061 88.074 42.529 ;
     RECT  88.815 41.449 95.922 42.529 ;
     RECT  86.115 40.703 86.397 42.601 ;
     RECT  0.18 42.089 0.558 42.653 ;
     RECT  77.22 42.061 77.238 42.727 ;
     RECT  78.015 39.749 78.297 42.727 ;
     RECT  80.064 42.529 81.306 42.727 ;
     RECT  86.04 42.601 86.397 42.791 ;
     RECT  2.415 41.989 8.694 42.871 ;
     RECT  98.1 42.763 98.118 42.893 ;
     RECT  2.415 42.871 9.126 43.069 ;
     RECT  9.936 36.625 11.106 43.069 ;
     RECT  80.064 42.727 81.414 43.141 ;
     RECT  86.115 42.791 86.397 43.141 ;
     RECT  39.024 40.787 43.146 43.2 ;
     RECT  74.952 40.945 76.446 43.2 ;
     RECT  82.656 41.881 82.674 43.259 ;
     RECT  88.056 42.529 95.922 43.259 ;
     RECT  86.115 43.141 87.102 43.295 ;
     RECT  80.064 43.141 81.774 43.411 ;
     RECT  2.415 43.069 11.106 43.483 ;
     RECT  2.268 43.483 11.106 43.601 ;
     RECT  2.304 43.601 11.106 43.637 ;
     RECT  88.056 43.259 88.074 43.681 ;
     RECT  87.984 43.681 88.074 43.835 ;
     RECT  0.108 43.195 0.126 44.059 ;
     RECT  84.528 43.843 84.546 44.107 ;
     RECT  2.304 43.637 10.797 44.249 ;
     RECT  0.108 44.059 0.162 44.311 ;
     RECT  88.815 43.259 95.922 44.339 ;
     RECT  0.108 44.311 0.558 44.528 ;
     RECT  77.22 42.727 78.297 44.539 ;
     RECT  95.76 44.339 95.922 44.609 ;
     RECT  95.76 44.609 95.778 44.645 ;
     RECT  2.415 44.249 10.797 44.669 ;
     RECT  77.22 44.539 78.39 44.669 ;
     RECT  39.024 43.2 76.446 44.725 ;
     RECT  0.144 44.528 0.558 44.957 ;
     RECT  0.144 44.957 0.162 45.197 ;
     RECT  3.42 44.669 10.797 45.293 ;
     RECT  2.415 44.669 2.697 45.355 ;
     RECT  2.304 45.355 2.697 45.419 ;
     RECT  3.42 45.293 9.342 45.491 ;
     RECT  88.815 44.339 94.497 45.533 ;
     RECT  90.648 45.533 94.497 45.689 ;
     RECT  38.844 44.725 76.446 45.691 ;
     RECT  77.22 44.669 78.297 45.691 ;
     RECT  86.115 43.295 86.397 45.691 ;
     RECT  90.648 45.689 92.07 45.725 ;
     RECT  86.115 45.691 86.67 45.869 ;
     RECT  38.844 45.691 78.297 46.109 ;
     RECT  82.656 45.979 82.674 46.109 ;
     RECT  80.064 43.411 81.846 46.201 ;
     RECT  38.844 46.109 75.726 46.205 ;
     RECT  80.064 46.201 82.206 46.253 ;
     RECT  88.056 43.835 88.074 46.345 ;
     RECT  88.815 45.533 89.91 46.345 ;
     RECT  80.064 46.253 81.846 46.349 ;
     RECT  88.056 46.345 89.91 46.397 ;
     RECT  3.42 45.491 8.838 46.535 ;
     RECT  93.06 45.689 94.497 46.603 ;
     RECT  92.916 46.603 94.497 46.643 ;
     RECT  3.6 46.535 8.838 46.679 ;
     RECT  86.115 45.869 86.397 46.747 ;
     RECT  88.056 46.397 88.074 46.781 ;
     RECT  86.115 46.747 86.49 46.877 ;
     RECT  76.932 46.109 78.297 46.891 ;
     RECT  34.815 2.413 35.097 46.921 ;
     RECT  80.532 46.349 81.846 46.925 ;
     RECT  90.936 45.725 92.07 47.039 ;
     RECT  83.415 40.739 83.697 47.047 ;
     RECT  84.528 44.107 84.798 47.047 ;
     RECT  90.936 47.039 91.797 47.047 ;
     RECT  92.988 46.643 94.497 47.069 ;
     RECT  3.6 46.679 5.994 47.111 ;
     RECT  80.532 46.925 80.997 47.117 ;
     RECT  38.844 46.205 75.51 47.155 ;
     RECT  88.815 46.397 89.91 47.165 ;
     RECT  76.896 46.891 78.297 47.191 ;
     RECT  76.896 47.191 78.39 47.213 ;
     RECT  90.648 47.047 91.797 47.219 ;
     RECT  76.932 47.213 78.39 47.261 ;
     RECT  80.64 47.117 80.997 47.261 ;
     RECT  81.756 46.925 81.846 47.419 ;
     RECT  38.628 47.155 75.51 47.425 ;
     RECT  81.756 47.419 81.882 47.453 ;
     RECT  83.415 47.047 84.798 47.453 ;
     RECT  79.308 47.323 79.326 47.579 ;
     RECT  84.528 47.453 84.798 47.645 ;
     RECT  6.732 46.679 8.838 47.651 ;
     RECT  81.864 47.453 81.882 47.693 ;
     RECT  34.776 46.921 35.097 47.849 ;
     RECT  38.52 47.425 75.51 47.849 ;
     RECT  79.596 47.731 79.614 47.885 ;
     RECT  93.42 47.069 94.497 47.893 ;
     RECT  38.628 47.849 75.51 47.933 ;
     RECT  3.852 47.111 5.994 48.191 ;
     RECT  76.932 47.261 78.297 48.271 ;
     RECT  7.056 47.651 8.838 48.299 ;
     RECT  76.356 48.271 78.297 48.361 ;
     RECT  37.515 2.413 37.797 48.703 ;
     RECT  38.628 47.933 75.33 48.703 ;
     RECT  3.888 48.191 5.994 48.731 ;
     RECT  7.056 48.299 8.622 48.767 ;
     RECT  37.515 48.703 75.33 48.901 ;
     RECT  76.32 48.361 78.297 48.901 ;
     RECT  37.515 48.901 78.297 48.989 ;
     RECT  34.815 47.849 35.097 49.315 ;
     RECT  37.515 48.989 76.41 49.343 ;
     RECT  34.776 49.315 35.097 49.469 ;
     RECT  77.652 48.989 78.297 49.469 ;
     RECT  38.772 49.343 76.41 49.577 ;
     RECT  4.464 48.731 5.994 49.649 ;
     RECT  7.2 48.767 8.622 49.883 ;
     RECT  7.2 49.883 8.514 49.919 ;
     RECT  5.115 49.649 5.994 50.189 ;
     RECT  38.88 49.577 76.41 50.237 ;
     RECT  77.724 49.469 78.297 50.287 ;
     RECT  7.2 49.919 8.097 50.387 ;
     RECT  77.688 50.287 78.297 50.584 ;
     RECT  38.88 50.237 75.192 50.665 ;
     RECT  77.616 50.584 78.297 50.779 ;
     RECT  77.58 50.779 78.297 50.855 ;
     RECT  38.844 50.665 75.192 51.097 ;
     RECT  38.736 51.097 75.192 51.101 ;
     RECT  41.58 51.101 75.192 51.205 ;
     RECT  76.392 50.237 76.41 51.205 ;
     RECT  95.724 51.061 95.742 51.205 ;
     RECT  95.724 51.205 95.778 51.331 ;
     RECT  93.024 47.893 94.497 51.355 ;
     RECT  38.736 51.101 40.806 51.359 ;
     RECT  41.58 51.205 76.41 51.389 ;
     RECT  95.724 51.331 95.922 51.389 ;
     RECT  95.724 51.389 95.778 51.533 ;
     RECT  93.024 51.355 94.59 51.637 ;
     RECT  77.688 50.855 78.297 51.736 ;
     RECT  93.024 51.637 94.662 51.809 ;
     RECT  37.515 49.343 37.797 51.883 ;
     RECT  38.736 51.359 40.734 51.883 ;
     RECT  76.392 51.389 76.41 51.965 ;
     RECT  95.724 51.533 95.742 52.051 ;
     RECT  77.58 51.736 78.297 52.123 ;
     RECT  90.936 47.219 91.797 52.141 ;
     RECT  95.58 52.051 95.742 52.141 ;
     RECT  90.756 52.141 91.797 52.249 ;
     RECT  93.024 51.809 94.626 52.249 ;
     RECT  77.544 52.123 78.297 52.315 ;
     RECT  37.515 51.883 40.734 52.321 ;
     RECT  41.58 51.389 75.192 52.321 ;
     RECT  90.684 52.249 94.626 52.591 ;
     RECT  95.436 52.141 95.742 52.591 ;
     RECT  90.684 52.591 95.742 52.681 ;
     RECT  37.515 52.321 75.192 52.789 ;
     RECT  90.648 52.681 95.742 52.825 ;
     RECT  76.392 52.795 76.41 52.891 ;
     RECT  77.4 52.315 78.297 52.891 ;
     RECT  76.392 52.891 78.297 53.015 ;
     RECT  90.648 52.825 95.778 53.131 ;
     RECT  37.515 52.789 75.51 53.179 ;
     RECT  76.968 53.015 78.297 53.249 ;
     RECT  90.648 53.131 95.922 53.249 ;
     RECT  37.515 53.179 76.23 53.285 ;
     RECT  86.115 46.877 86.397 53.401 ;
     RECT  38.772 53.285 76.23 53.429 ;
     RECT  89.892 47.165 89.91 53.491 ;
     RECT  90.648 53.249 95.562 53.491 ;
     RECT  97.452 53.275 97.47 53.861 ;
     RECT  89.892 53.491 95.562 53.995 ;
     RECT  88.815 47.165 89.097 54.031 ;
     RECT  89.892 53.995 95.778 54.031 ;
     RECT  86.115 53.401 86.67 54.175 ;
     RECT  86.115 54.175 86.778 54.473 ;
     RECT  39.06 53.429 76.23 54.481 ;
     RECT  38.952 54.481 76.23 54.557 ;
     RECT  88.815 54.031 95.778 54.653 ;
     RECT  98.1 54.715 98.118 54.845 ;
     RECT  96.912 54.985 96.93 55.037 ;
     RECT  89.856 54.653 95.778 55.111 ;
     RECT  88.815 54.653 89.097 55.561 ;
     RECT  89.856 55.111 95.922 55.561 ;
     RECT  88.815 55.561 95.922 55.679 ;
     RECT  89.856 55.679 95.922 55.867 ;
     RECT  39.492 54.557 76.23 55.949 ;
     RECT  84.636 47.645 84.798 55.949 ;
     RECT  97.452 55.435 97.47 56.291 ;
     RECT  88.815 55.679 89.097 56.491 ;
     RECT  89.856 55.867 96.426 56.491 ;
     RECT  84.708 55.949 84.798 56.641 ;
     RECT  86.115 54.473 86.397 56.641 ;
     RECT  84.708 56.641 86.397 56.759 ;
     RECT  84.708 56.759 84.726 56.831 ;
     RECT  88.815 56.491 96.426 56.957 ;
     RECT  77.22 53.249 78.297 57.029 ;
     RECT  80.676 47.261 80.997 57.065 ;
     RECT  88.815 56.957 95.922 57.245 ;
     RECT  89.856 57.245 95.922 57.344 ;
     RECT  91.515 57.344 95.922 57.569 ;
     RECT  91.515 57.569 95.778 57.641 ;
     RECT  89.856 57.344 90.486 60.421 ;
     RECT  39.492 55.949 76.158 60.504 ;
     RECT  89.856 60.421 90.666 60.611 ;
     RECT  89.856 60.611 90.486 60.719 ;
     RECT  75.204 60.504 76.158 61.051 ;
     RECT  77.22 57.029 77.238 61.051 ;
     RECT  78.015 57.029 78.297 61.051 ;
     RECT  86.115 56.759 86.397 61.051 ;
     RECT  77.22 61.051 78.678 61.088 ;
     RECT  91.515 57.641 95.562 61.115 ;
     RECT  94.215 61.115 95.562 61.133 ;
     RECT  91.515 61.115 93.15 61.151 ;
     RECT  78.015 61.088 78.678 61.181 ;
     RECT  86.115 61.051 86.67 61.181 ;
     RECT  95.544 61.133 95.562 61.181 ;
     RECT  75.204 61.051 76.23 61.187 ;
     RECT  75.204 61.187 76.086 61.223 ;
     RECT  39.492 60.504 43.11 61.385 ;
     RECT  77.22 61.088 77.238 61.421 ;
     RECT  39.492 61.385 40.698 61.457 ;
     RECT  89.856 60.719 90.162 61.619 ;
     RECT  89.856 61.619 89.874 61.889 ;
     RECT  41.688 61.385 43.11 62.131 ;
     RECT  75.204 61.223 75.726 62.473 ;
     RECT  74.664 62.473 75.726 62.501 ;
     RECT  49.86 61.861 49.878 62.545 ;
     RECT  74.664 62.501 75.597 62.609 ;
     RECT  49.86 62.545 50.454 62.623 ;
     RECT  70.704 62.581 70.722 62.623 ;
     RECT  49.86 62.623 51.105 62.699 ;
     RECT  69.915 62.623 70.722 62.699 ;
     RECT  75.204 62.609 75.597 62.735 ;
     RECT  50.436 62.699 51.105 62.879 ;
     RECT  41.688 62.131 43.146 62.893 ;
     RECT  45.615 62.623 45.705 62.893 ;
     RECT  48.315 62.623 48.405 62.893 ;
     RECT  51.015 62.879 51.105 62.893 ;
     RECT  53.715 62.623 53.805 62.893 ;
     RECT  56.415 62.623 56.505 62.893 ;
     RECT  59.115 62.623 59.205 62.893 ;
     RECT  61.815 62.623 61.905 62.893 ;
     RECT  64.515 62.623 64.605 62.893 ;
     RECT  67.215 62.623 67.305 62.893 ;
     RECT  72.615 62.623 72.705 62.893 ;
     RECT  75.24 62.735 75.597 62.969 ;
     RECT  41.688 62.893 43.197 64.561 ;
     RECT  41.688 64.561 43.542 64.859 ;
     RECT  41.688 64.859 43.254 64.877 ;
     RECT  41.688 64.877 43.218 64.973 ;
     RECT  80.715 57.065 80.997 65.707 ;
     RECT  80.424 65.707 80.997 65.747 ;
     RECT  78.015 61.181 78.297 65.803 ;
     RECT  78.015 65.803 78.894 65.849 ;
     RECT  78.015 65.849 78.297 67.819 ;
     RECT  78.015 67.819 78.462 68.099 ;
     RECT  91.515 61.151 91.797 69.451 ;
     RECT  91.515 69.451 92.106 69.643 ;
     RECT  93.024 61.151 93.15 69.643 ;
     RECT  91.515 69.643 93.15 69.719 ;
     RECT  78.015 68.099 78.297 70.501 ;
     RECT  77.904 70.501 78.297 70.541 ;
     RECT  77.22 70.645 77.238 70.685 ;
     RECT  91.515 69.719 92.214 70.685 ;
     RECT  76.752 72.955 76.77 73.229 ;
     RECT  76.428 73.273 76.446 73.325 ;
     RECT  37.515 53.285 37.797 74.011 ;
     RECT  5.115 50.189 5.397 74.047 ;
     RECT  4.5 74.047 5.397 74.093 ;
     RECT  5.115 74.093 5.397 74.191 ;
     RECT  5.115 74.191 5.454 74.309 ;
     RECT  2.415 45.419 2.697 74.425 ;
     RECT  2.304 74.425 2.697 74.461 ;
     RECT  3.996 74.443 4.014 74.461 ;
     RECT  2.304 74.461 4.014 74.477 ;
     RECT  37.515 74.011 38.502 74.551 ;
     RECT  39.492 61.457 40.497 74.551 ;
     RECT  0.108 74.299 0.126 74.731 ;
     RECT  2.415 74.477 4.014 74.821 ;
     RECT  6.912 74.731 6.93 74.821 ;
     RECT  7.815 50.387 8.097 74.821 ;
     RECT  0.108 74.731 0.162 74.923 ;
     RECT  6.912 74.821 8.097 74.929 ;
     RECT  6.84 74.929 8.097 74.965 ;
     RECT  10.515 45.293 10.797 74.971 ;
     RECT  13.215 2.413 13.497 74.971 ;
     RECT  0.108 74.923 0.198 75.053 ;
     RECT  5.115 74.309 5.397 75.091 ;
     RECT  6.372 74.965 8.097 75.091 ;
     RECT  10.515 74.971 10.854 75.101 ;
     RECT  13.215 74.971 13.842 75.119 ;
     RECT  5.115 75.091 8.097 75.127 ;
     RECT  5.115 75.127 8.478 75.163 ;
     RECT  13.215 75.119 13.554 75.197 ;
     RECT  2.415 74.821 4.194 75.433 ;
     RECT  75.315 62.969 75.597 75.451 ;
     RECT  77.184 75.433 77.202 75.485 ;
     RECT  37.515 74.551 40.497 75.505 ;
     RECT  0.108 75.053 0.126 75.569 ;
     RECT  75.315 75.451 75.654 75.569 ;
     RECT  2.415 75.433 4.23 75.595 ;
     RECT  2.304 75.595 4.23 75.659 ;
     RECT  2.415 75.659 4.23 75.739 ;
     RECT  2.415 75.739 4.374 75.775 ;
     RECT  5.115 75.163 8.622 75.775 ;
     RECT  21.315 2.413 21.597 75.901 ;
     RECT  10.515 75.101 10.797 76.081 ;
     RECT  10.515 76.081 10.854 76.199 ;
     RECT  0.144 75.883 0.162 76.603 ;
     RECT  9.432 75.433 9.45 76.621 ;
     RECT  9.432 76.621 9.558 76.739 ;
     RECT  0.108 76.603 0.162 76.747 ;
     RECT  0.108 76.747 0.198 76.783 ;
     RECT  0.108 76.783 0.27 76.829 ;
     RECT  0.108 76.829 0.198 76.919 ;
     RECT  0.108 76.919 0.126 77.213 ;
     RECT  2.415 75.775 8.622 77.431 ;
     RECT  9.432 76.739 9.486 77.431 ;
     RECT  86.115 61.181 86.397 77.947 ;
     RECT  93.024 69.719 93.15 77.995 ;
     RECT  94.215 61.133 94.497 77.995 ;
     RECT  93.024 77.995 93.294 78.043 ;
     RECT  94.176 77.995 94.497 78.043 ;
     RECT  0.144 77.755 0.162 78.077 ;
     RECT  86.115 77.947 86.67 78.077 ;
     RECT  84.6 77.947 84.906 78.089 ;
     RECT  84.888 78.089 84.906 78.359 ;
     RECT  93.024 78.043 94.497 78.403 ;
     RECT  92.988 78.403 94.497 78.467 ;
     RECT  64.515 62.893 64.797 78.511 ;
     RECT  66.06 78.331 66.078 78.511 ;
     RECT  67.215 62.893 67.497 78.511 ;
     RECT  66.06 78.511 67.497 78.557 ;
     RECT  0.108 78.331 0.126 78.629 ;
     RECT  66.06 78.557 66.15 78.629 ;
     RECT  92.988 78.467 93.15 78.629 ;
     RECT  64.515 78.511 65.286 78.664 ;
     RECT  64.515 78.664 65.754 78.701 ;
     RECT  2.415 77.431 9.486 78.763 ;
     RECT  2.304 78.763 9.486 78.809 ;
     RECT  64.515 78.701 65.538 78.899 ;
     RECT  79.236 78.745 79.254 78.943 ;
     RECT  79.236 78.943 79.65 78.971 ;
     RECT  92.988 78.629 93.042 78.971 ;
     RECT  2.415 78.809 9.486 79.169 ;
     RECT  95.76 80.095 95.778 80.131 ;
     RECT  3.6 79.169 9.486 80.671 ;
     RECT  10.515 76.199 10.797 80.671 ;
     RECT  95.76 80.131 95.922 80.869 ;
     RECT  95.76 80.869 95.994 80.909 ;
     RECT  94.215 78.467 94.497 80.923 ;
     RECT  95.76 80.909 95.922 80.923 ;
     RECT  94.215 80.923 95.922 81.101 ;
     RECT  2.415 79.169 2.79 81.239 ;
     RECT  37.515 75.505 40.77 81.301 ;
     RECT  92.988 78.971 93.006 81.301 ;
     RECT  3.6 80.671 10.797 81.329 ;
     RECT  94.215 81.101 95.778 81.403 ;
     RECT  92.556 81.301 93.006 81.445 ;
     RECT  93.924 81.403 95.778 81.445 ;
     RECT  78.015 70.541 78.297 81.607 ;
     RECT  91.515 70.685 91.797 81.607 ;
     RECT  92.556 81.445 95.778 81.607 ;
     RECT  78.015 81.607 78.678 81.779 ;
     RECT  97.452 81.643 97.47 81.941 ;
     RECT  86.115 78.077 86.397 82.111 ;
     RECT  88.815 57.245 89.097 82.123 ;
     RECT  90.324 81.571 90.666 82.123 ;
     RECT  91.515 81.607 95.778 82.123 ;
     RECT  76.464 81.571 76.482 82.291 ;
     RECT  86.115 82.111 86.67 82.409 ;
     RECT  88.815 82.123 95.778 82.409 ;
     RECT  75.315 75.569 75.597 82.525 ;
     RECT  85.068 82.411 85.086 82.651 ;
     RECT  64.515 78.899 65.286 82.679 ;
     RECT  84.96 82.651 85.086 82.715 ;
     RECT  75.168 82.525 75.597 82.747 ;
     RECT  76.464 82.291 76.914 82.747 ;
     RECT  85.068 82.715 85.086 82.747 ;
     RECT  90.18 82.409 95.778 82.747 ;
     RECT  64.515 82.679 65.214 82.751 ;
     RECT  75.168 82.747 76.914 82.831 ;
     RECT  85.068 82.747 85.194 82.921 ;
     RECT  88.815 82.409 89.406 82.973 ;
     RECT  85.068 82.921 85.23 82.985 ;
     RECT  90.18 82.747 95.814 83.035 ;
     RECT  75.132 82.831 76.914 83.101 ;
     RECT  90.18 83.035 95.922 83.129 ;
     RECT  86.115 82.409 86.397 83.191 ;
     RECT  75.096 83.101 76.914 83.219 ;
     RECT  3.708 81.329 10.797 83.255 ;
     RECT  41.688 64.973 43.197 83.275 ;
     RECT  91.44 83.129 95.922 83.489 ;
     RECT  3.708 83.255 4.086 83.525 ;
     RECT  86.115 83.191 86.922 83.563 ;
     RECT  90.18 83.129 90.666 83.569 ;
     RECT  4.032 83.525 4.086 83.597 ;
     RECT  37.515 81.301 40.878 83.605 ;
     RECT  64.515 82.751 65.178 83.641 ;
     RECT  48.315 62.893 48.597 83.659 ;
     RECT  64.515 83.641 65.25 83.755 ;
     RECT  64.404 83.755 65.25 83.795 ;
     RECT  66.384 83.755 66.402 83.795 ;
     RECT  85.356 83.563 86.922 83.795 ;
     RECT  69.915 62.699 70.197 83.797 ;
     RECT  69.915 83.797 70.686 83.803 ;
     RECT  78.015 81.779 78.297 83.803 ;
     RECT  53.715 62.893 53.997 83.899 ;
     RECT  61.815 62.893 62.097 83.899 ;
     RECT  64.515 83.795 65.25 83.899 ;
     RECT  78.015 83.803 78.678 83.933 ;
     RECT  85.5 83.795 86.922 83.939 ;
     RECT  72.615 62.893 72.897 83.947 ;
     RECT  45.615 62.893 45.897 83.987 ;
     RECT  51.015 62.893 51.297 83.987 ;
     RECT  56.415 62.893 56.697 83.987 ;
     RECT  59.115 62.893 59.397 83.987 ;
     RECT  67.215 78.557 67.497 83.987 ;
     RECT  72.216 83.947 72.897 83.987 ;
     RECT  88.815 82.973 89.37 84.001 ;
     RECT  90.144 83.569 90.666 84.001 ;
     RECT  85.536 83.939 86.922 84.029 ;
     RECT  53.715 83.899 54.09 84.043 ;
     RECT  54.828 83.899 54.846 84.043 ;
     RECT  85.644 84.029 86.922 84.065 ;
     RECT  48.315 83.659 49.086 84.077 ;
     RECT  53.715 84.043 54.846 84.077 ;
     RECT  61.815 83.899 62.802 84.077 ;
     RECT  72.216 83.987 72.705 84.077 ;
     RECT  83.415 47.453 83.697 84.091 ;
     RECT  88.815 84.001 90.666 84.137 ;
     RECT  64.515 83.899 65.538 84.139 ;
     RECT  90.144 84.137 90.666 84.139 ;
     RECT  46.764 84.043 46.782 84.173 ;
     RECT  53.715 84.077 54.198 84.173 ;
     RECT  64.515 84.139 65.862 84.173 ;
     RECT  65.844 84.173 65.862 84.179 ;
     RECT  49.356 84.091 49.374 84.209 ;
     RECT  69.915 83.803 70.83 84.221 ;
     RECT  45.615 83.987 45.705 84.257 ;
     RECT  48.315 84.077 48.405 84.257 ;
     RECT  51.015 83.987 51.105 84.257 ;
     RECT  53.715 84.173 53.805 84.257 ;
     RECT  56.415 83.987 56.505 84.257 ;
     RECT  59.115 83.987 59.205 84.257 ;
     RECT  61.815 84.077 61.905 84.257 ;
     RECT  64.515 84.173 65.034 84.257 ;
     RECT  67.215 83.987 67.305 84.257 ;
     RECT  69.915 84.221 70.005 84.257 ;
     RECT  72.615 84.077 72.705 84.257 ;
     RECT  41.688 83.275 43.542 84.365 ;
     RECT  70.812 84.221 70.83 84.365 ;
     RECT  97.452 83.227 97.47 84.37 ;
     RECT  83.196 84.091 83.697 84.569 ;
     RECT  84.744 84.568 84.762 84.605 ;
     RECT  97.416 84.37 97.47 84.641 ;
     RECT  4.068 83.597 4.086 84.649 ;
     RECT  5.115 83.255 10.797 84.649 ;
     RECT  2.415 81.239 2.697 84.721 ;
     RECT  4.068 84.649 10.797 84.721 ;
     RECT  75.132 83.219 76.914 84.721 ;
     RECT  0.108 84.667 0.126 84.749 ;
     RECT  2.415 84.721 2.898 84.811 ;
     RECT  90.144 84.139 90.774 84.847 ;
     RECT  91.515 83.489 95.922 84.847 ;
     RECT  2.304 84.811 2.898 84.848 ;
     RECT  3.996 84.721 10.797 84.883 ;
     RECT  11.664 83.569 11.682 84.883 ;
     RECT  78.015 83.933 78.354 84.991 ;
     RECT  2.415 84.848 2.898 85.081 ;
     RECT  3.996 84.883 11.682 85.081 ;
     RECT  80.715 65.747 80.997 85.081 ;
     RECT  86.115 84.065 86.922 85.099 ;
     RECT  88.815 84.137 89.097 85.099 ;
     RECT  90.144 84.847 95.922 85.099 ;
     RECT  78.015 84.991 78.894 85.109 ;
     RECT  80.388 85.081 80.997 85.133 ;
     RECT  65.016 84.257 65.034 85.253 ;
     RECT  75.132 84.721 77.274 85.261 ;
     RECT  78.015 85.109 78.297 85.261 ;
     RECT  85.68 85.099 86.922 85.387 ;
     RECT  85.572 85.387 86.922 85.424 ;
     RECT  88.815 85.099 95.922 85.685 ;
     RECT  97.452 84.641 97.47 85.721 ;
     RECT  90.072 85.685 95.922 85.793 ;
     RECT  90.324 85.793 95.922 85.829 ;
     RECT  82.656 85.801 82.674 85.919 ;
     RECT  86.076 85.424 86.922 85.919 ;
     RECT  0.144 85.147 0.162 85.949 ;
     RECT  80.715 85.133 80.997 86.035 ;
     RECT  90.324 85.829 95.778 86.225 ;
     RECT  90.324 86.225 95.634 86.297 ;
     RECT  41.688 84.365 43.074 86.4 ;
     RECT  75.132 85.261 78.297 86.4 ;
     RECT  20.772 75.901 21.597 86.459 ;
     RECT  95.616 86.297 95.634 86.525 ;
     RECT  81.72 85.801 81.738 86.539 ;
     RECT  86.115 85.919 86.922 86.539 ;
     RECT  86.115 86.539 86.994 86.639 ;
     RECT  37.515 83.605 40.95 86.773 ;
     RECT  41.688 86.4 78.297 86.773 ;
     RECT  34.815 49.469 35.097 86.845 ;
     RECT  0.54 86.341 0.558 87.005 ;
     RECT  34.776 86.845 35.097 87.143 ;
     RECT  2.415 85.081 11.682 87.197 ;
     RECT  37.515 86.773 78.297 87.307 ;
     RECT  84.708 87.259 84.726 87.307 ;
     RECT  84.636 87.307 84.726 87.355 ;
     RECT  2.415 87.197 2.697 87.403 ;
     RECT  90.324 86.297 94.662 87.413 ;
     RECT  37.515 87.307 78.678 87.437 ;
     RECT  3.492 87.197 11.682 87.581 ;
     RECT  94.215 87.413 94.662 87.773 ;
     RECT  4.464 87.581 11.682 87.953 ;
     RECT  90.324 87.413 93.474 87.965 ;
     RECT  3.492 87.581 3.618 88.075 ;
     RECT  0.108 87.547 0.126 88.123 ;
     RECT  2.304 87.403 2.697 88.123 ;
     RECT  3.42 88.075 3.618 88.123 ;
     RECT  90.468 87.965 93.474 88.205 ;
     RECT  2.304 88.123 3.618 88.253 ;
     RECT  0.108 88.123 0.342 88.259 ;
     RECT  0.144 88.259 0.342 88.301 ;
     RECT  3.42 88.253 3.618 88.321 ;
     RECT  4.464 87.953 9.738 88.321 ;
     RECT  10.515 87.953 11.682 88.349 ;
     RECT  86.115 86.639 86.922 88.663 ;
     RECT  3.42 88.321 9.738 88.799 ;
     RECT  10.515 88.349 11.106 88.799 ;
     RECT  0.144 88.301 0.162 88.877 ;
     RECT  3.492 88.799 9.738 88.889 ;
     RECT  37.515 87.437 78.297 88.939 ;
     RECT  86.115 88.663 87.21 89.131 ;
     RECT  3.492 88.889 3.618 89.159 ;
     RECT  4.5 88.889 9.738 89.159 ;
     RECT  79.632 78.971 79.65 89.159 ;
     RECT  2.304 88.253 2.697 89.168 ;
     RECT  86.076 89.131 87.21 89.213 ;
     RECT  86.076 89.213 86.67 89.231 ;
     RECT  37.515 88.939 78.678 89.239 ;
     RECT  4.68 89.159 9.738 89.267 ;
     RECT  37.044 89.239 78.678 89.405 ;
     RECT  76.572 89.405 78.678 89.693 ;
     RECT  86.115 89.231 86.67 89.741 ;
     RECT  90.864 88.205 93.474 89.755 ;
     RECT  37.044 89.405 75.69 89.807 ;
     RECT  4.68 89.267 9.702 89.843 ;
     RECT  4.716 89.843 9.702 89.879 ;
     RECT  90.648 89.755 93.474 89.941 ;
     RECT  94.215 87.773 94.497 89.941 ;
     RECT  37.116 89.807 75.69 89.969 ;
     RECT  90.648 89.941 94.497 89.981 ;
     RECT  77.22 89.693 78.678 90.077 ;
     RECT  90.864 89.981 94.497 90.077 ;
     RECT  77.292 90.077 78.678 90.173 ;
     RECT  90.864 90.077 92.862 90.239 ;
     RECT  81.72 86.539 82.17 90.317 ;
     RECT  34.815 87.143 35.097 90.319 ;
     RECT  80.532 86.035 80.997 90.557 ;
     RECT  86.115 89.741 86.49 90.763 ;
     RECT  82.152 90.317 82.17 90.845 ;
     RECT  77.508 90.173 78.678 90.893 ;
     RECT  86.115 90.763 86.67 90.893 ;
     RECT  90.864 90.239 92.466 90.893 ;
     RECT  3.528 89.159 3.618 90.923 ;
     RECT  4.716 89.879 8.874 90.959 ;
     RECT  34.776 90.319 35.097 91.193 ;
     RECT  3.528 90.923 3.546 91.427 ;
     RECT  37.515 89.969 75.69 91.435 ;
     RECT  9.684 89.879 9.702 91.463 ;
     RECT  37.044 91.435 75.69 91.471 ;
     RECT  4.716 90.959 6.966 91.499 ;
     RECT  37.044 91.471 76.338 91.517 ;
     RECT  37.044 91.517 75.546 91.613 ;
     RECT  37.044 91.613 75.192 91.697 ;
     RECT  76.32 91.517 76.338 91.705 ;
     RECT  76.32 91.705 76.374 91.805 ;
     RECT  4.716 91.499 6.066 91.967 ;
     RECT  34.815 91.193 35.097 92.011 ;
     RECT  76.356 91.805 76.374 92.011 ;
     RECT  77.508 90.893 78.297 92.011 ;
     RECT  76.356 92.011 78.297 92.093 ;
     RECT  34.776 92.011 35.097 92.273 ;
     RECT  76.356 92.093 76.41 92.381 ;
     RECT  77.58 92.093 78.297 92.477 ;
     RECT  6.84 91.499 6.966 92.543 ;
     RECT  7.815 90.959 8.874 92.579 ;
     RECT  7.815 92.579 8.622 93.047 ;
     RECT  34.815 92.273 35.097 93.091 ;
     RECT  37.515 91.697 75.192 93.181 ;
     RECT  4.716 91.967 5.49 93.281 ;
     RECT  22.464 93.307 22.482 93.325 ;
     RECT  34.776 93.091 35.097 93.353 ;
     RECT  37.044 93.181 75.192 93.389 ;
     RECT  21.315 86.459 21.597 93.445 ;
     RECT  22.464 93.325 22.554 93.445 ;
     RECT  21.315 93.445 22.554 93.479 ;
     RECT  6.84 92.543 6.858 93.551 ;
     RECT  18.615 2.413 18.897 93.559 ;
     RECT  5.115 93.281 5.49 93.587 ;
     RECT  18.615 93.559 18.954 93.659 ;
     RECT  21.315 93.479 22.266 93.659 ;
     RECT  76.392 92.381 76.41 93.793 ;
     RECT  77.616 92.477 78.297 93.865 ;
     RECT  37.515 93.389 75.192 93.991 ;
     RECT  76.356 93.793 76.41 93.991 ;
     RECT  77.58 93.865 78.297 93.991 ;
     RECT  77.436 93.991 78.297 94.199 ;
     RECT  37.515 93.991 76.41 94.685 ;
     RECT  77.724 94.199 78.297 94.936 ;
     RECT  76.356 94.685 76.41 95.261 ;
     RECT  94.215 90.077 94.497 96.061 ;
     RECT  95.76 96.025 95.778 96.061 ;
     RECT  77.616 94.936 78.297 96.091 ;
     RECT  94.215 96.061 95.886 96.151 ;
     RECT  94.215 96.151 95.922 96.173 ;
     RECT  94.215 96.173 94.806 96.187 ;
     RECT  76.392 95.261 76.41 96.215 ;
     RECT  90.864 90.893 92.43 96.235 ;
     RECT  93.924 96.187 94.806 96.295 ;
     RECT  90.864 96.235 92.826 96.331 ;
     RECT  93.636 96.295 94.806 96.331 ;
     RECT  77.436 96.091 78.297 96.379 ;
     RECT  95.616 96.173 95.922 96.461 ;
     RECT  37.515 94.685 75.192 96.475 ;
     RECT  95.616 96.461 95.778 96.509 ;
     RECT  76.644 96.379 78.297 96.989 ;
     RECT  86.115 90.893 86.397 97.069 ;
     RECT  90.864 96.331 94.806 97.105 ;
     RECT  90.36 97.105 94.806 97.195 ;
     RECT  95.616 96.509 95.634 97.195 ;
     RECT  90.36 97.195 95.634 97.231 ;
     RECT  86.115 97.069 86.67 97.259 ;
     RECT  90.36 97.231 95.922 97.325 ;
     RECT  97.452 96.331 97.47 97.331 ;
     RECT  90.36 97.325 95.742 97.951 ;
     RECT  88.815 85.685 89.097 98.059 ;
     RECT  89.892 97.951 95.742 98.059 ;
     RECT  37.515 96.475 75.834 98.105 ;
     RECT  97.452 98.059 97.47 98.141 ;
     RECT  39.492 98.105 75.834 98.149 ;
     RECT  76.644 96.989 76.662 98.149 ;
     RECT  86.115 97.259 86.397 98.149 ;
     RECT  86.115 98.149 86.67 98.185 ;
     RECT  88.815 98.059 95.814 98.251 ;
     RECT  86.115 98.185 86.706 98.339 ;
     RECT  88.815 98.251 95.85 98.683 ;
     RECT  37.515 98.105 38.646 98.725 ;
     RECT  98.1 98.635 98.118 98.765 ;
     RECT  37.476 98.725 38.646 98.879 ;
     RECT  37.476 98.879 38.322 99.019 ;
     RECT  37.368 99.019 38.322 99.059 ;
     RECT  97.452 99.211 97.47 99.355 ;
     RECT  77.436 96.989 78.297 99.391 ;
     RECT  97.416 99.355 97.47 99.491 ;
     RECT  21.315 93.659 21.597 99.643 ;
     RECT  22.356 99.547 22.374 99.643 ;
     RECT  21.315 99.643 22.374 99.689 ;
     RECT  77.436 99.391 78.93 99.689 ;
     RECT  88.815 98.683 95.922 99.689 ;
     RECT  97.416 99.491 97.434 99.761 ;
     RECT  84.492 87.355 84.726 100.003 ;
     RECT  86.115 98.339 86.67 100.031 ;
     RECT  84.492 100.003 85.374 100.229 ;
     RECT  98.172 100.219 98.19 100.237 ;
     RECT  98.172 100.237 98.262 100.265 ;
     RECT  84.636 100.229 84.654 100.301 ;
     RECT  98.244 100.265 98.262 100.301 ;
     RECT  88.815 99.689 95.778 100.499 ;
     RECT  90.144 100.499 95.778 100.805 ;
     RECT  88.815 100.499 89.154 100.829 ;
     RECT  95.76 100.805 95.778 100.84 ;
     RECT  90.144 100.805 94.914 100.877 ;
     RECT  95.76 100.84 95.85 100.987 ;
     RECT  95.76 100.987 95.922 101.597 ;
     RECT  39.492 98.149 76.662 101.615 ;
     RECT  95.76 101.597 95.778 101.615 ;
     RECT  39.492 101.615 76.194 103.704 ;
     RECT  93.492 100.877 94.914 103.811 ;
     RECT  90.144 100.877 92.574 103.883 ;
     RECT  90.144 103.883 91.854 103.919 ;
     RECT  93.492 103.811 94.497 104.387 ;
     RECT  93.564 104.387 94.497 104.423 ;
     RECT  90.144 103.919 90.738 104.549 ;
     RECT  39.492 103.704 43.146 104.729 ;
     RECT  75.24 103.704 76.194 104.729 ;
     RECT  93.744 104.423 94.497 105.161 ;
     RECT  91.515 103.919 91.854 105.197 ;
     RECT  75.24 104.729 75.474 105.637 ;
     RECT  49.212 105.133 49.23 105.673 ;
     RECT  48.996 105.673 49.23 105.709 ;
     RECT  50.616 105.169 50.634 105.709 ;
     RECT  70.704 105.637 70.722 105.709 ;
     RECT  75.24 105.637 75.618 105.737 ;
     RECT  90.144 104.549 90.162 105.737 ;
     RECT  48.996 105.709 49.338 105.781 ;
     RECT  75.24 105.737 75.597 105.781 ;
     RECT  70.704 105.709 70.794 105.809 ;
     RECT  78.015 99.689 78.93 105.809 ;
     RECT  48.888 105.781 49.338 105.823 ;
     RECT  50.616 105.709 50.85 105.823 ;
     RECT  64.836 105.451 64.854 105.823 ;
     RECT  46.8 105.745 46.818 105.871 ;
     RECT  48.315 105.823 49.338 105.899 ;
     RECT  50.616 105.823 51.105 105.899 ;
     RECT  75.06 105.781 75.597 105.935 ;
     RECT  46.764 105.871 46.818 105.971 ;
     RECT  46.8 105.971 46.818 106.007 ;
     RECT  41.292 104.729 43.146 106.093 ;
     RECT  45.615 105.823 45.705 106.093 ;
     RECT  51.015 105.899 51.105 106.093 ;
     RECT  53.715 105.823 53.805 106.093 ;
     RECT  56.415 105.823 56.505 106.093 ;
     RECT  59.115 105.823 59.205 106.093 ;
     RECT  61.815 105.823 61.905 106.093 ;
     RECT  67.215 105.823 67.305 106.093 ;
     RECT  72.615 105.823 72.705 106.093 ;
     RECT  64.515 105.823 64.854 106.169 ;
     RECT  75.276 105.935 75.597 106.169 ;
     RECT  66.384 105.973 66.402 106.301 ;
     RECT  90.72 106.951 90.738 106.987 ;
     RECT  90.612 106.987 90.738 107.021 ;
     RECT  90.612 107.021 90.63 107.125 ;
     RECT  90.432 107.125 90.63 107.165 ;
     RECT  90.612 107.165 90.63 107.249 ;
     RECT  41.292 106.093 43.197 107.275 ;
     RECT  41.292 107.275 43.254 107.671 ;
     RECT  64.515 106.169 64.797 107.752 ;
     RECT  64.515 107.752 64.962 107.789 ;
     RECT  66.384 107.905 66.402 108.125 ;
     RECT  41.292 107.671 43.542 108.509 ;
     RECT  41.292 108.509 43.398 108.557 ;
     RECT  41.292 108.557 43.197 113.459 ;
     RECT  41.652 113.459 43.197 114.523 ;
     RECT  41.436 114.523 43.197 114.575 ;
     RECT  37.515 99.059 38.322 115.579 ;
     RECT  37.404 115.579 38.322 115.619 ;
     RECT  37.476 115.619 38.322 115.709 ;
     RECT  88.815 100.829 89.097 116.251 ;
     RECT  87.768 116.239 87.786 116.285 ;
     RECT  88.815 116.251 89.406 116.401 ;
     RECT  87.12 116.311 87.138 116.429 ;
     RECT  86.115 100.031 86.397 116.473 ;
     RECT  88.815 116.401 89.73 116.699 ;
     RECT  85.716 116.473 86.67 116.861 ;
     RECT  88.815 116.699 89.406 116.861 ;
     RECT  63.072 117.781 63.09 117.821 ;
     RECT  61.815 106.093 62.097 117.835 ;
     RECT  61.815 117.835 62.73 117.965 ;
     RECT  6.336 118.021 6.354 118.057 ;
     RECT  7.815 93.047 8.097 118.057 ;
     RECT  34.815 93.353 35.097 118.057 ;
     RECT  5.115 93.587 5.397 118.093 ;
     RECT  6.336 118.057 6.858 118.093 ;
     RECT  34.815 118.057 36.198 118.093 ;
     RECT  2.415 89.168 2.697 118.129 ;
     RECT  3.42 118.021 3.438 118.129 ;
     RECT  7.668 118.057 8.097 118.165 ;
     RECT  10.515 88.799 10.797 118.165 ;
     RECT  34.815 118.093 36.414 118.201 ;
     RECT  5.115 118.093 6.858 118.363 ;
     RECT  7.596 118.165 8.097 118.363 ;
     RECT  37.515 115.709 38.322 118.363 ;
     RECT  39.492 104.729 40.497 118.363 ;
     RECT  10.515 118.165 10.818 118.391 ;
     RECT  5.115 118.363 8.097 118.399 ;
     RECT  2.415 118.129 3.438 118.435 ;
     RECT  5.115 118.399 8.298 118.463 ;
     RECT  2.415 118.435 3.546 118.471 ;
     RECT  2.415 118.471 3.978 118.589 ;
     RECT  6.336 118.463 8.298 118.589 ;
     RECT  41.652 114.575 43.197 118.633 ;
     RECT  34.815 118.201 36.738 118.669 ;
     RECT  37.515 118.363 40.497 118.669 ;
     RECT  2.415 118.589 3.294 118.795 ;
     RECT  4.14 118.741 4.158 118.831 ;
     RECT  5.115 118.463 5.562 118.831 ;
     RECT  2.304 118.795 3.294 118.859 ;
     RECT  4.14 118.831 5.562 118.859 ;
     RECT  4.5 118.859 5.562 118.877 ;
     RECT  0.108 118.129 0.126 118.987 ;
     RECT  6.444 118.589 8.298 119.101 ;
     RECT  9.288 119.011 9.306 119.209 ;
     RECT  41.472 118.633 43.197 119.245 ;
     RECT  9.288 119.209 9.342 119.281 ;
     RECT  9.288 119.281 9.414 119.309 ;
     RECT  2.415 118.859 3.294 119.371 ;
     RECT  5.115 118.877 5.562 119.371 ;
     RECT  6.444 119.101 8.514 119.371 ;
     RECT  9.396 119.309 9.414 119.399 ;
     RECT  5.115 119.371 8.514 119.611 ;
     RECT  2.415 119.371 3.726 119.641 ;
     RECT  4.68 119.611 8.514 119.641 ;
     RECT  2.415 119.641 8.514 119.677 ;
     RECT  9.432 119.551 9.45 119.705 ;
     RECT  2.268 119.677 8.514 119.785 ;
     RECT  34.815 118.669 40.497 119.813 ;
     RECT  2.268 119.785 8.622 119.837 ;
     RECT  0.108 118.987 0.162 119.947 ;
     RECT  0.108 119.947 0.198 119.983 ;
     RECT  0.108 119.983 0.27 120.029 ;
     RECT  21.315 99.689 21.597 120.043 ;
     RECT  29.415 2.413 29.697 120.043 ;
     RECT  0.108 120.029 0.198 120.119 ;
     RECT  2.415 119.837 8.622 120.119 ;
     RECT  24.015 2.413 24.297 120.181 ;
     RECT  22.608 119.707 22.626 120.209 ;
     RECT  14.832 120.043 14.85 120.221 ;
     RECT  21.315 120.043 21.69 120.221 ;
     RECT  23.94 120.181 24.297 120.221 ;
     RECT  29.415 120.043 29.79 120.221 ;
     RECT  30.78 120.043 30.798 120.221 ;
     RECT  34.815 119.813 38.358 120.361 ;
     RECT  34.776 120.361 38.358 120.551 ;
     RECT  34.815 120.551 38.358 120.559 ;
     RECT  39.492 119.813 40.497 120.559 ;
     RECT  34.815 120.559 40.497 120.571 ;
     RECT  41.256 119.245 43.197 120.571 ;
     RECT  2.415 120.119 8.154 120.859 ;
     RECT  2.415 120.859 8.19 121.019 ;
     RECT  3.42 121.019 8.19 121.171 ;
     RECT  34.815 120.571 43.197 121.297 ;
     RECT  64.515 107.789 64.797 121.369 ;
     RECT  34.776 121.297 43.197 121.397 ;
     RECT  69.915 105.823 70.197 121.435 ;
     RECT  13.215 75.197 13.497 121.531 ;
     RECT  21.315 120.221 21.597 121.531 ;
     RECT  26.715 2.413 26.997 121.531 ;
     RECT  13.104 121.531 13.497 121.568 ;
     RECT  21.204 121.531 21.597 121.568 ;
     RECT  3.42 121.171 8.622 121.582 ;
     RECT  46.764 121.435 46.782 121.613 ;
     RECT  58.14 121.261 58.158 121.613 ;
     RECT  63.54 121.261 63.558 121.613 ;
     RECT  64.515 121.369 65.106 121.613 ;
     RECT  69.915 121.435 70.722 121.613 ;
     RECT  14.832 121.531 14.85 121.661 ;
     RECT  26.676 121.531 26.997 121.661 ;
     RECT  30.78 121.297 30.798 121.661 ;
     RECT  0.108 120.119 0.126 121.739 ;
     RECT  2.415 121.019 2.697 121.963 ;
     RECT  2.304 121.963 2.697 122.009 ;
     RECT  3.492 121.582 8.622 122.099 ;
     RECT  34.815 121.397 38.502 122.215 ;
     RECT  39.492 121.397 43.197 122.215 ;
     RECT  3.492 122.099 6.318 122.369 ;
     RECT  7.092 122.099 8.622 122.525 ;
     RECT  7.272 122.525 8.622 122.611 ;
     RECT  0.108 122.539 0.126 122.669 ;
     RECT  34.815 122.215 43.197 122.731 ;
     RECT  7.272 122.611 8.658 122.819 ;
     RECT  34.56 122.731 43.197 122.909 ;
     RECT  3.492 122.369 4.086 123.053 ;
     RECT  7.344 122.819 8.658 123.089 ;
     RECT  34.776 122.909 43.197 123.089 ;
     RECT  7.38 123.089 8.658 123.179 ;
     RECT  7.815 123.179 8.658 123.629 ;
     RECT  34.815 123.089 43.197 123.835 ;
     RECT  34.812 123.835 43.197 123.871 ;
     RECT  4.068 123.053 4.086 123.899 ;
     RECT  30.78 123.799 30.798 123.899 ;
     RECT  5.115 122.369 6.318 123.961 ;
     RECT  34.776 123.871 43.197 124.075 ;
     RECT  5.115 123.961 6.858 124.097 ;
     RECT  34.632 124.075 43.197 124.133 ;
     RECT  7.815 123.629 8.586 124.141 ;
     RECT  7.704 124.141 8.586 124.169 ;
     RECT  7.704 124.169 8.226 124.205 ;
     RECT  7.815 124.205 8.226 124.259 ;
     RECT  5.115 124.097 6.318 124.367 ;
     RECT  95.688 124.231 95.706 124.375 ;
     RECT  74.412 124.219 74.43 124.411 ;
     RECT  75.315 106.169 75.597 124.411 ;
     RECT  5.115 124.367 5.742 124.439 ;
     RECT  74.412 124.411 74.574 124.501 ;
     RECT  75.312 124.411 75.597 124.501 ;
     RECT  91.515 105.197 91.797 124.681 ;
     RECT  95.688 124.375 95.778 124.685 ;
     RECT  91.404 124.681 91.797 124.829 ;
     RECT  74.412 124.501 75.597 124.843 ;
     RECT  34.815 124.133 43.197 124.891 ;
     RECT  94.215 105.161 94.497 124.951 ;
     RECT  95.688 124.685 95.742 124.951 ;
     RECT  73.764 124.843 75.597 125.069 ;
     RECT  76.644 124.681 76.662 125.221 ;
     RECT  94.215 124.951 95.742 125.221 ;
     RECT  76.644 125.221 77.202 125.311 ;
     RECT  78.015 105.809 78.297 125.311 ;
     RECT  92.664 124.681 92.682 125.347 ;
     RECT  92.664 125.347 93.402 125.371 ;
     RECT  94.14 125.221 95.742 125.371 ;
     RECT  74.556 125.069 75.597 125.383 ;
     RECT  34.776 124.891 43.197 125.419 ;
     RECT  92.664 125.371 95.742 125.491 ;
     RECT  88.815 116.861 89.097 125.581 ;
     RECT  98.172 125.563 98.19 125.581 ;
     RECT  98.172 125.581 98.262 125.609 ;
     RECT  98.244 125.609 98.262 125.645 ;
     RECT  34.56 125.419 43.197 125.653 ;
     RECT  74.556 125.383 75.654 125.761 ;
     RECT  91.515 124.829 91.797 125.761 ;
     RECT  88.596 125.581 89.097 125.803 ;
     RECT  91.515 125.761 91.854 125.887 ;
     RECT  92.664 125.491 95.814 125.887 ;
     RECT  83.415 84.569 83.697 125.899 ;
     RECT  34.56 125.653 43.29 125.923 ;
     RECT  73.764 125.069 73.782 125.923 ;
     RECT  74.556 125.761 75.69 125.923 ;
     RECT  90.252 125.887 90.27 125.923 ;
     RECT  88.596 125.803 89.334 125.995 ;
     RECT  90.252 125.923 90.378 125.995 ;
     RECT  91.515 125.887 95.814 125.995 ;
     RECT  73.764 125.923 75.762 126.139 ;
     RECT  88.596 125.995 90.378 126.149 ;
     RECT  83.088 125.899 83.697 126.185 ;
     RECT  91.515 125.995 95.85 126.185 ;
     RECT  89.892 126.149 90.378 126.229 ;
     RECT  73.764 126.139 75.906 126.301 ;
     RECT  76.644 125.311 78.297 126.301 ;
     RECT  91.515 126.185 92.898 126.391 ;
     RECT  89.892 126.229 90.486 126.419 ;
     RECT  93.708 126.185 95.85 126.419 ;
     RECT  89.892 126.419 90.342 126.461 ;
     RECT  83.415 126.185 83.697 126.475 ;
     RECT  97.452 126.427 97.47 126.491 ;
     RECT  91.26 126.391 92.898 126.523 ;
     RECT  93.852 126.419 95.85 126.619 ;
     RECT  80.715 90.557 80.997 126.661 ;
     RECT  73.764 126.301 78.297 126.667 ;
     RECT  34.56 125.923 43.326 126.689 ;
     RECT  80.715 126.661 81.09 126.701 ;
     RECT  98.1 126.571 98.118 126.701 ;
     RECT  83.415 126.475 83.79 126.725 ;
     RECT  73.764 126.667 78.39 126.733 ;
     RECT  69.915 121.613 70.197 126.805 ;
     RECT  55.548 126.805 55.566 126.841 ;
     RECT  85.716 116.861 86.397 126.931 ;
     RECT  55.476 126.841 55.566 126.967 ;
     RECT  56.415 106.093 56.697 126.967 ;
     RECT  55.476 126.967 56.697 126.995 ;
     RECT  73.728 126.733 78.39 126.995 ;
     RECT  69.915 126.805 70.722 127.067 ;
     RECT  55.548 126.995 56.697 127.103 ;
     RECT  74.7 126.995 78.39 127.111 ;
     RECT  83.415 126.725 83.697 127.111 ;
     RECT  88.596 126.149 89.097 127.111 ;
     RECT  89.892 126.461 89.946 127.111 ;
     RECT  45.615 106.093 45.897 127.187 ;
     RECT  48.315 105.899 48.597 127.187 ;
     RECT  51.015 106.093 51.297 127.187 ;
     RECT  53.715 106.093 53.997 127.187 ;
     RECT  55.728 127.103 56.697 127.187 ;
     RECT  59.115 106.093 59.397 127.187 ;
     RECT  61.815 117.965 62.097 127.187 ;
     RECT  64.515 121.613 64.797 127.187 ;
     RECT  67.215 106.093 67.497 127.187 ;
     RECT  69.915 127.067 70.197 127.187 ;
     RECT  72.615 106.093 72.897 127.187 ;
     RECT  88.596 127.111 89.946 127.201 ;
     RECT  73.728 126.995 73.782 127.229 ;
     RECT  74.7 127.111 78.678 127.229 ;
     RECT  83.16 127.111 83.697 127.229 ;
     RECT  93.852 126.619 95.922 127.229 ;
     RECT  55.728 127.187 56.505 127.277 ;
     RECT  88.596 127.201 90.306 127.291 ;
     RECT  91.188 126.523 92.898 127.291 ;
     RECT  88.596 127.291 92.898 127.345 ;
     RECT  93.852 127.229 95.814 127.345 ;
     RECT  85.716 126.931 86.67 127.373 ;
     RECT  88.596 127.345 95.814 127.373 ;
     RECT  34.74 126.689 43.326 127.381 ;
     RECT  55.836 127.277 56.505 127.409 ;
     RECT  73.728 127.229 73.746 127.409 ;
     RECT  45.615 127.187 45.705 127.457 ;
     RECT  48.315 127.187 48.405 127.457 ;
     RECT  51.015 127.187 51.105 127.457 ;
     RECT  53.715 127.187 53.805 127.457 ;
     RECT  56.415 127.409 56.505 127.457 ;
     RECT  59.115 127.187 59.205 127.457 ;
     RECT  61.815 127.187 61.905 127.457 ;
     RECT  64.515 127.187 64.605 127.457 ;
     RECT  67.215 127.187 67.305 127.457 ;
     RECT  69.915 127.187 70.005 127.457 ;
     RECT  72.615 127.187 72.705 127.457 ;
     RECT  83.196 127.229 83.697 127.565 ;
     RECT  89.892 127.373 95.814 127.565 ;
     RECT  34.74 127.381 43.362 127.571 ;
     RECT  34.74 127.571 43.074 127.921 ;
     RECT  89.892 127.565 89.91 128.093 ;
     RECT  90.792 127.565 95.814 128.093 ;
     RECT  85.716 127.373 86.397 128.155 ;
     RECT  5.115 124.439 5.397 128.251 ;
     RECT  93.564 128.093 95.814 128.309 ;
     RECT  93.564 128.309 94.59 128.525 ;
     RECT  5.115 128.251 5.598 128.539 ;
     RECT  95.364 128.309 95.814 128.551 ;
     RECT  85.032 128.155 86.397 128.615 ;
     RECT  79.2 128.551 79.218 128.621 ;
     RECT  85.14 128.615 86.397 128.621 ;
     RECT  2.415 122.009 2.697 128.731 ;
     RECT  74.7 127.229 78.297 128.813 ;
     RECT  90.828 128.093 92.538 128.827 ;
     RECT  90.648 128.827 92.538 128.957 ;
     RECT  93.636 128.525 94.59 128.957 ;
     RECT  5.115 128.539 6.21 128.965 ;
     RECT  7.815 124.259 8.097 128.965 ;
     RECT  93.636 128.957 94.497 128.993 ;
     RECT  3.996 128.875 4.014 129.001 ;
     RECT  95.364 128.551 95.922 129.029 ;
     RECT  5.115 128.965 6.966 129.091 ;
     RECT  7.815 128.965 8.406 129.091 ;
     RECT  5.115 129.091 8.406 129.119 ;
     RECT  5.115 129.119 8.37 129.191 ;
     RECT  5.115 129.191 6.966 129.211 ;
     RECT  3.744 129.001 4.014 129.235 ;
     RECT  4.968 129.211 6.966 129.235 ;
     RECT  0.216 129.019 0.234 129.245 ;
     RECT  2.304 128.731 2.697 129.271 ;
     RECT  3.744 129.235 6.966 129.271 ;
     RECT  2.304 129.271 6.966 129.389 ;
     RECT  95.76 129.029 95.922 129.389 ;
     RECT  95.76 129.389 95.778 129.437 ;
     RECT  34.38 127.921 43.074 129.451 ;
     RECT  3.42 129.389 6.966 129.485 ;
     RECT  34.38 129.451 43.11 129.6 ;
     RECT  75.204 128.813 78.297 129.6 ;
     RECT  9.144 129.739 9.162 129.929 ;
     RECT  3.564 129.485 6.966 129.965 ;
     RECT  93.276 129.979 93.294 130.235 ;
     RECT  0.144 129.499 0.162 130.301 ;
     RECT  80.715 126.701 80.997 130.315 ;
     RECT  4.176 129.965 6.966 130.351 ;
     RECT  7.815 129.191 8.37 130.351 ;
     RECT  94.14 128.993 94.497 130.351 ;
     RECT  2.304 129.389 2.697 130.379 ;
     RECT  4.176 130.351 8.37 130.441 ;
     RECT  34.38 129.6 78.297 130.459 ;
     RECT  34.38 130.459 78.678 130.541 ;
     RECT  2.415 130.379 2.697 130.621 ;
     RECT  2.415 130.621 3.222 130.711 ;
     RECT  4.176 130.441 8.478 130.711 ;
     RECT  2.415 130.711 8.478 130.739 ;
     RECT  83.415 127.565 83.697 130.747 ;
     RECT  85.716 128.621 86.397 130.747 ;
     RECT  88.596 127.373 89.097 130.747 ;
     RECT  90.9 128.957 92.538 130.819 ;
     RECT  6.876 130.739 8.406 130.919 ;
     RECT  34.596 130.541 78.678 130.987 ;
     RECT  85.716 130.747 86.634 130.987 ;
     RECT  0.324 130.603 0.342 131.035 ;
     RECT  90.756 130.819 92.538 131.053 ;
     RECT  93.492 130.351 94.497 131.053 ;
     RECT  0.108 131.035 0.342 131.069 ;
     RECT  90.684 131.053 94.497 131.083 ;
     RECT  34.596 130.987 78.786 131.117 ;
     RECT  88.596 130.747 89.766 131.165 ;
     RECT  90.648 131.083 94.497 131.189 ;
     RECT  0.108 131.069 0.234 131.213 ;
     RECT  83.124 130.747 83.697 131.279 ;
     RECT  34.596 131.117 78.678 131.309 ;
     RECT  85.716 130.987 86.778 131.309 ;
     RECT  90.684 131.189 94.497 131.309 ;
     RECT  88.668 131.165 89.766 131.405 ;
     RECT  34.596 131.309 78.297 131.515 ;
     RECT  2.415 130.739 5.814 131.521 ;
     RECT  2.376 131.521 5.814 131.611 ;
     RECT  90.828 131.309 94.497 131.645 ;
     RECT  34.416 131.515 78.297 131.827 ;
     RECT  0.108 131.213 0.126 131.885 ;
     RECT  90.9 131.645 94.497 131.933 ;
     RECT  2.304 131.611 5.814 131.971 ;
     RECT  7.2 130.919 8.406 131.971 ;
     RECT  2.304 131.971 6.246 131.999 ;
     RECT  2.415 131.999 6.246 132.089 ;
     RECT  7.164 131.971 8.406 132.089 ;
     RECT  87.156 131.395 87.21 132.133 ;
     RECT  2.415 132.089 3.51 132.161 ;
     RECT  34.2 131.827 78.297 132.235 ;
     RECT  85.716 131.309 86.397 132.235 ;
     RECT  87.12 132.133 87.21 132.235 ;
     RECT  4.248 132.089 6.246 132.241 ;
     RECT  7.2 132.089 8.406 132.241 ;
     RECT  9.144 131.665 9.162 132.241 ;
     RECT  7.2 132.241 9.162 132.269 ;
     RECT  93.132 131.933 94.497 132.359 ;
     RECT  90.9 131.933 92.25 132.367 ;
     RECT  34.2 132.235 78.786 132.413 ;
     RECT  93.168 132.359 94.497 132.413 ;
     RECT  34.2 132.413 78.678 132.509 ;
     RECT  85.716 132.235 87.21 132.509 ;
     RECT  90.648 132.367 92.25 132.539 ;
     RECT  87.12 132.509 87.21 132.653 ;
     RECT  87.192 132.653 87.21 132.701 ;
     RECT  76.68 132.509 78.678 132.797 ;
     RECT  90.9 132.539 92.25 133.037 ;
     RECT  4.248 132.241 6.282 133.313 ;
     RECT  76.68 132.797 78.39 133.591 ;
     RECT  34.2 132.509 75.798 133.627 ;
     RECT  34.2 133.627 75.834 133.709 ;
     RECT  76.68 133.591 78.462 133.709 ;
     RECT  76.68 133.709 78.39 133.745 ;
     RECT  4.248 133.313 6.03 133.889 ;
     RECT  76.68 133.745 78.354 134.131 ;
     RECT  7.815 132.269 9.162 134.159 ;
     RECT  76.392 134.131 78.354 134.249 ;
     RECT  2.415 132.161 2.862 134.429 ;
     RECT  34.2 133.709 75.546 134.699 ;
     RECT  76.392 134.249 78.297 134.909 ;
     RECT  7.815 134.159 8.586 134.969 ;
     RECT  34.815 134.699 75.546 135.067 ;
     RECT  76.392 134.909 76.41 135.067 ;
     RECT  4.248 133.889 4.266 135.239 ;
     RECT  34.815 135.067 76.41 135.293 ;
     RECT  77.544 134.909 78.297 135.293 ;
     RECT  7.815 134.969 8.37 135.473 ;
     RECT  5.115 133.889 6.03 135.509 ;
     RECT  34.815 135.293 42.462 135.677 ;
     RECT  34.815 135.677 42.21 135.869 ;
     RECT  34.815 135.869 35.37 136.049 ;
     RECT  36.18 135.869 42.21 136.061 ;
     RECT  36.18 136.061 41.67 136.139 ;
     RECT  36.828 136.139 41.67 136.157 ;
     RECT  77.58 135.293 78.297 136.157 ;
     RECT  77.616 136.157 78.297 136.253 ;
     RECT  36.828 136.157 41.022 136.891 ;
     RECT  36.612 136.891 41.022 136.949 ;
     RECT  77.724 136.253 78.297 137.065 ;
     RECT  37.08 136.949 41.022 137.275 ;
     RECT  77.58 137.065 78.297 137.309 ;
     RECT  37.08 137.275 41.598 137.335 ;
     RECT  37.08 137.335 42.21 137.563 ;
     RECT  43.2 135.293 76.41 137.563 ;
     RECT  94.215 132.413 94.497 137.755 ;
     RECT  95.904 137.731 95.922 137.875 ;
     RECT  37.08 137.563 76.41 137.933 ;
     RECT  94.215 137.755 94.626 138.001 ;
     RECT  95.76 137.875 95.922 138.001 ;
     RECT  94.215 138.001 95.922 138.269 ;
     RECT  77.616 137.309 78.297 138.427 ;
     RECT  94.215 138.269 95.778 138.461 ;
     RECT  90.9 133.037 92.142 138.541 ;
     RECT  85.716 132.509 86.397 138.571 ;
     RECT  85.716 138.571 86.418 138.721 ;
     RECT  90.9 138.541 92.214 138.721 ;
     RECT  37.515 137.933 76.41 138.845 ;
     RECT  88.815 131.405 89.766 138.847 ;
     RECT  90.576 138.721 92.214 138.847 ;
     RECT  85.716 138.721 87.246 138.875 ;
     RECT  37.515 138.845 75.51 138.949 ;
     RECT  88.815 138.847 92.214 138.955 ;
     RECT  85.788 138.875 87.246 138.983 ;
     RECT  37.188 138.949 75.51 138.989 ;
     RECT  88.524 138.955 92.214 138.991 ;
     RECT  86.115 138.983 87.246 139.037 ;
     RECT  88.2 138.991 92.214 139.145 ;
     RECT  77.436 138.427 78.297 139.225 ;
     RECT  88.815 139.145 92.214 139.225 ;
     RECT  93.168 132.413 93.222 139.225 ;
     RECT  94.215 138.461 95.634 139.225 ;
     RECT  86.115 139.037 86.67 139.289 ;
     RECT  76.392 138.845 76.41 139.415 ;
     RECT  88.815 139.225 92.394 139.483 ;
     RECT  93.168 139.225 95.778 139.483 ;
     RECT  88.815 139.483 95.85 139.523 ;
     RECT  37.515 138.989 75.51 139.621 ;
     RECT  37.515 139.621 75.834 139.649 ;
     RECT  93.168 139.523 95.85 139.649 ;
     RECT  93.168 139.649 95.814 139.853 ;
     RECT  77.22 139.225 78.297 139.867 ;
     RECT  88.815 139.523 92.394 140.305 ;
     RECT  93.168 139.853 95.778 140.305 ;
     RECT  88.815 140.305 95.778 140.729 ;
     RECT  86.115 139.289 86.397 140.779 ;
     RECT  90.936 140.729 95.778 141.067 ;
     RECT  90.936 141.067 95.922 141.179 ;
     RECT  90.936 141.179 95.598 141.269 ;
     RECT  90.936 141.269 95.418 141.305 ;
     RECT  86.115 140.779 87.03 141.539 ;
     RECT  42.444 139.649 75.834 141.547 ;
     RECT  76.644 139.867 78.297 141.547 ;
     RECT  88.815 140.729 90.162 141.583 ;
     RECT  90.936 141.305 95.274 141.583 ;
     RECT  86.115 141.539 86.67 141.809 ;
     RECT  88.815 141.583 95.274 141.953 ;
     RECT  90.756 141.953 95.274 142.079 ;
     RECT  97.452 140.251 97.47 142.16 ;
     RECT  91.044 142.079 95.274 142.267 ;
     RECT  88.815 141.953 89.838 142.321 ;
     RECT  80.64 130.315 80.997 142.421 ;
     RECT  37.515 139.649 41.598 142.429 ;
     RECT  42.444 141.547 78.297 142.429 ;
     RECT  88.344 142.321 89.838 142.499 ;
     RECT  91.044 142.267 95.634 142.507 ;
     RECT  88.344 142.499 89.19 142.529 ;
     RECT  91.044 142.507 95.778 142.591 ;
     RECT  98.1 142.555 98.118 142.685 ;
     RECT  86.115 141.809 86.397 142.771 ;
     RECT  91.044 142.591 95.922 142.861 ;
     RECT  81.756 130.843 81.774 142.889 ;
     RECT  86.115 142.771 86.67 143.033 ;
     RECT  88.815 142.529 89.19 143.159 ;
     RECT  91.008 142.861 95.922 143.429 ;
     RECT  92.916 143.429 95.922 143.465 ;
     RECT  93.276 143.465 95.922 143.879 ;
     RECT  95.76 143.879 95.922 144.545 ;
     RECT  95.904 144.545 95.922 144.557 ;
     RECT  37.515 142.429 78.297 146.904 ;
     RECT  93.276 143.879 94.914 147.083 ;
     RECT  91.008 143.429 92.034 147.281 ;
     RECT  37.515 146.904 42.75 147.643 ;
     RECT  37.44 147.643 42.75 147.749 ;
     RECT  93.528 147.083 94.914 147.749 ;
     RECT  42.444 147.749 42.75 147.785 ;
     RECT  93.528 147.749 94.842 147.785 ;
     RECT  37.44 147.749 41.454 147.821 ;
     RECT  37.44 147.821 41.31 147.857 ;
     RECT  91.044 147.281 92.034 147.857 ;
     RECT  93.528 147.785 94.497 147.929 ;
     RECT  37.44 147.857 40.95 148.019 ;
     RECT  75.24 146.904 78.297 148.019 ;
     RECT  37.476 148.019 40.698 148.055 ;
     RECT  76.104 148.019 78.297 148.055 ;
     RECT  37.476 148.055 40.626 148.091 ;
     RECT  76.104 148.055 76.662 148.091 ;
     RECT  49.608 147.901 49.626 148.441 ;
     RECT  91.515 147.857 92.034 148.469 ;
     RECT  37.476 148.091 40.497 148.589 ;
     RECT  48.996 148.441 49.626 148.873 ;
     RECT  75.24 148.019 75.294 148.981 ;
     RECT  42.66 147.785 42.75 149.009 ;
     RECT  76.104 148.091 76.122 149.009 ;
     RECT  48.996 148.873 50.202 149.023 ;
     RECT  74.664 148.981 75.294 149.023 ;
     RECT  48.315 149.023 50.202 149.071 ;
     RECT  51.015 149.023 51.105 149.071 ;
     RECT  48.315 149.071 51.105 149.099 ;
     RECT  74.664 149.023 75.597 149.099 ;
     RECT  50.724 149.099 51.105 149.171 ;
     RECT  42.915 149.023 43.005 149.293 ;
     RECT  45.615 149.023 45.705 149.293 ;
     RECT  51.015 149.171 51.105 149.293 ;
     RECT  53.715 149.023 53.805 149.293 ;
     RECT  56.415 149.023 56.505 149.293 ;
     RECT  59.115 149.023 59.205 149.293 ;
     RECT  61.815 149.023 61.905 149.293 ;
     RECT  64.515 149.023 64.605 149.293 ;
     RECT  67.215 149.023 67.305 149.293 ;
     RECT  69.915 149.023 70.005 149.293 ;
     RECT  72.615 149.023 72.705 149.293 ;
     RECT  75.24 149.099 75.597 149.675 ;
     RECT  37.515 148.589 40.497 165.883 ;
     RECT  37.44 165.883 40.497 165.92 ;
     RECT  37.515 165.92 40.497 167.189 ;
     RECT  37.515 167.189 39.438 167.531 ;
     RECT  37.515 167.531 39.186 167.999 ;
     RECT  2.415 134.429 2.697 168.227 ;
     RECT  5.115 135.509 5.397 168.227 ;
     RECT  7.815 135.473 8.097 168.227 ;
     RECT  10.515 118.391 10.797 168.227 ;
     RECT  13.215 121.568 13.497 168.227 ;
     RECT  15.915 2.413 16.197 168.227 ;
     RECT  18.615 93.659 18.897 168.227 ;
     RECT  21.315 121.568 21.597 168.227 ;
     RECT  24.015 120.221 24.297 168.227 ;
     RECT  26.715 121.661 26.997 168.227 ;
     RECT  29.415 120.221 29.697 168.227 ;
     RECT  32.115 2.413 32.397 168.227 ;
     RECT  34.815 136.049 35.097 168.227 ;
     RECT  40.215 167.189 40.497 168.227 ;
     RECT  42.915 149.293 43.197 168.227 ;
     RECT  45.615 149.293 45.897 168.227 ;
     RECT  48.315 149.099 48.597 168.227 ;
     RECT  51.015 149.293 51.297 168.227 ;
     RECT  53.715 149.293 53.997 168.227 ;
     RECT  56.415 149.293 56.697 168.227 ;
     RECT  59.115 149.293 59.397 168.227 ;
     RECT  61.815 149.293 62.097 168.227 ;
     RECT  64.515 149.293 64.797 168.227 ;
     RECT  67.215 149.293 67.497 168.227 ;
     RECT  69.915 149.293 70.197 168.227 ;
     RECT  72.615 149.293 72.897 168.227 ;
     RECT  75.315 149.675 75.597 168.227 ;
     RECT  78.015 148.055 78.297 168.227 ;
     RECT  80.715 142.421 80.997 168.227 ;
     RECT  83.415 131.279 83.697 168.227 ;
     RECT  86.115 143.033 86.397 168.227 ;
     RECT  88.815 143.159 89.097 168.227 ;
     RECT  91.515 148.469 91.797 168.227 ;
     RECT  94.215 147.929 94.497 168.227 ;
     RECT  2.415 168.227 2.505 168.497 ;
     RECT  5.115 168.227 5.205 168.497 ;
     RECT  7.815 168.227 7.905 168.497 ;
     RECT  10.515 168.227 10.605 168.497 ;
     RECT  13.215 168.227 13.305 168.497 ;
     RECT  15.915 168.227 16.005 168.497 ;
     RECT  18.615 168.227 18.705 168.497 ;
     RECT  21.315 168.227 21.405 168.497 ;
     RECT  24.015 168.227 24.105 168.497 ;
     RECT  26.715 168.227 26.805 168.497 ;
     RECT  29.415 168.227 29.505 168.497 ;
     RECT  32.115 168.227 32.205 168.497 ;
     RECT  34.815 168.227 34.905 168.497 ;
     RECT  37.515 167.999 39.006 168.497 ;
     RECT  40.215 168.227 40.305 168.497 ;
     RECT  42.915 168.227 43.005 168.497 ;
     RECT  45.615 168.227 45.705 168.497 ;
     RECT  48.315 168.227 48.405 168.497 ;
     RECT  51.015 168.227 51.105 168.497 ;
     RECT  53.715 168.227 53.805 168.497 ;
     RECT  56.415 168.227 56.505 168.497 ;
     RECT  59.115 168.227 59.205 168.497 ;
     RECT  61.815 168.227 61.905 168.497 ;
     RECT  64.515 168.227 64.605 168.497 ;
     RECT  67.215 168.227 67.305 168.497 ;
     RECT  69.915 168.227 70.005 168.497 ;
     RECT  72.615 168.227 72.705 168.497 ;
     RECT  75.315 168.227 75.405 168.497 ;
     RECT  78.015 168.227 78.105 168.497 ;
     RECT  80.715 168.227 80.805 168.497 ;
     RECT  83.415 168.227 83.505 168.497 ;
     RECT  86.115 168.227 86.205 168.497 ;
     RECT  88.815 168.227 88.905 168.497 ;
     RECT  91.515 168.227 91.605 168.497 ;
     RECT  94.215 168.227 94.305 168.497 ;
     RECT  38.124 168.497 39.006 170.395 ;
     RECT  37.836 170.395 39.006 170.609 ;
     RECT  37.908 170.609 39.006 170.621 ;
    LAYER M4 ;
     RECT  0.06 118.08 0.097 122.568 ;
     RECT  0.06 128.736 0.097 131.784 ;
     RECT  0.06 31.68 0.137 36.168 ;
     RECT  0.06 74.304 0.137 78.792 ;
     RECT  0.06 84.672 0.137 89.16 ;
     RECT  0.06 40.896 0.569 45.384 ;
     RECT  0.137 31.776 2.252 36.168 ;
     RECT  2.252 31.776 2.408 36.264 ;
     RECT  0.569 41.136 2.408 45.384 ;
     RECT  0.137 74.448 2.408 78.792 ;
     RECT  0.137 84.816 2.408 89.16 ;
     RECT  0.097 118.08 2.408 122.664 ;
     RECT  0.097 128.736 2.408 131.88 ;
     RECT  2.408 2.148 2.512 168.492 ;
     RECT  2.512 2.418 2.704 168.222 ;
     RECT  2.704 118.08 3.449 122.664 ;
     RECT  2.704 74.448 3.973 78.792 ;
     RECT  2.704 41.136 3.989 45.432 ;
     RECT  2.704 31.776 4.025 36.12 ;
     RECT  2.704 84.816 4.025 89.16 ;
     RECT  2.704 128.88 4.025 131.88 ;
     RECT  4.129 40.032 4.157 40.056 ;
     RECT  3.973 74.064 4.412 78.792 ;
     RECT  4.412 74.064 4.561 79.08 ;
     RECT  4.453 80.112 4.561 80.136 ;
     RECT  4.025 31.968 5.108 36.12 ;
     RECT  4.157 39.984 5.108 40.056 ;
     RECT  3.989 41.184 5.108 45.432 ;
     RECT  4.561 74.064 5.108 80.136 ;
     RECT  4.025 84.96 5.108 89.16 ;
     RECT  3.449 118.368 5.108 122.664 ;
     RECT  4.025 129.168 5.108 131.88 ;
     RECT  5.108 2.148 5.212 168.492 ;
     RECT  5.212 2.418 5.404 168.222 ;
     RECT  5.404 75.12 5.465 76.008 ;
     RECT  5.404 78.624 5.465 78.648 ;
     RECT  5.404 85.632 5.555 89.016 ;
     RECT  5.404 128.256 5.573 131.88 ;
     RECT  5.404 43.056 5.609 45.24 ;
     RECT  5.404 41.184 5.645 41.928 ;
     RECT  5.609 44.736 5.645 45.24 ;
     RECT  5.555 88.992 5.645 89.016 ;
     RECT  5.404 118.368 5.681 119.208 ;
     RECT  5.404 32.208 5.717 36.12 ;
     RECT  5.645 41.232 5.717 41.928 ;
     RECT  5.609 43.056 5.717 43.656 ;
     RECT  5.645 44.736 5.717 45 ;
     RECT  5.465 75.264 5.717 76.008 ;
     RECT  5.404 120.24 5.717 122.52 ;
     RECT  5.573 131.04 5.717 131.064 ;
     RECT  5.717 32.352 5.747 36.12 ;
     RECT  5.747 32.448 5.795 36.12 ;
     RECT  5.717 44.736 5.825 44.856 ;
     RECT  5.795 32.448 5.933 34.008 ;
     RECT  5.404 79.728 5.939 80.136 ;
     RECT  5.555 85.632 5.939 85.656 ;
     RECT  5.825 44.736 5.969 44.76 ;
     RECT  5.555 86.64 6.157 87.816 ;
     RECT  5.573 128.256 6.227 129.432 ;
     RECT  5.933 33.984 6.257 34.008 ;
     RECT  6.157 86.64 6.401 87.336 ;
     RECT  5.404 38.016 6.515 38.04 ;
     RECT  5.681 119.184 6.721 119.208 ;
     RECT  5.717 43.344 6.757 43.368 ;
     RECT  6.721 118.512 6.805 119.208 ;
     RECT  5.717 75.264 6.937 75.288 ;
     RECT  5.717 120.768 7.117 122.52 ;
     RECT  7.117 120.24 7.333 122.52 ;
     RECT  6.937 75.168 7.381 75.288 ;
     RECT  7.381 74.976 7.429 75.288 ;
     RECT  5.717 41.664 7.441 41.688 ;
     RECT  6.721 78.048 7.549 78.072 ;
     RECT  7.045 85.104 7.628 85.128 ;
     RECT  7.628 85.104 7.669 85.608 ;
     RECT  6.401 86.64 7.669 86.76 ;
     RECT  7.333 120.24 7.669 123.048 ;
     RECT  5.933 32.448 7.808 32.472 ;
     RECT  5.795 35.328 7.808 35.352 ;
     RECT  6.469 36.672 7.808 36.696 ;
     RECT  5.404 40.032 7.808 40.056 ;
     RECT  7.441 41.664 7.808 42.024 ;
     RECT  6.757 43.344 7.808 43.416 ;
     RECT  7.429 74.976 7.808 75.96 ;
     RECT  7.125 76.944 7.808 76.968 ;
     RECT  7.549 78.048 7.808 78.648 ;
     RECT  5.939 79.728 7.808 79.752 ;
     RECT  7.669 84.912 7.808 85.608 ;
     RECT  7.669 86.64 7.808 87.288 ;
     RECT  6.805 119.184 7.808 119.208 ;
     RECT  7.669 120.192 7.808 123.048 ;
     RECT  7.649 124.176 7.808 124.2 ;
     RECT  6.227 128.256 7.808 128.28 ;
     RECT  6.227 129.408 7.808 129.432 ;
     RECT  7.808 2.148 7.912 168.492 ;
     RECT  7.912 2.418 8.104 168.222 ;
     RECT  8.104 78.624 8.165 78.648 ;
     RECT  8.104 84.912 8.165 84.936 ;
     RECT  8.104 36.144 8.243 36.168 ;
     RECT  8.104 41.424 8.243 44.088 ;
     RECT  8.104 120.192 8.243 123.048 ;
     RECT  8.104 124.176 8.243 124.2 ;
     RECT  8.243 120.192 8.245 122.28 ;
     RECT  8.104 86.736 8.273 86.76 ;
     RECT  8.104 129.12 8.284 129.144 ;
     RECT  8.243 42.96 8.381 42.984 ;
     RECT  8.243 44.064 8.381 44.088 ;
     RECT  8.245 121.632 8.417 122.28 ;
     RECT  8.104 74.976 8.489 75.192 ;
     RECT  8.104 119.184 8.489 119.208 ;
     RECT  8.104 40.032 10.508 40.056 ;
     RECT  8.243 41.424 10.508 41.448 ;
     RECT  8.489 74.976 10.508 75 ;
     RECT  8.245 120.192 10.508 120.216 ;
     RECT  8.417 121.632 10.508 121.656 ;
     RECT  10.508 2.148 10.612 168.492 ;
     RECT  10.612 2.418 10.804 168.222 ;
     RECT  10.804 74.976 10.865 75.096 ;
     RECT  10.804 40.032 11.981 40.056 ;
     RECT  12.301 40.416 12.373 40.44 ;
     RECT  10.804 41.424 12.373 41.448 ;
     RECT  12.373 40.416 13.208 41.448 ;
     RECT  10.865 74.976 13.208 75 ;
     RECT  10.804 120.192 13.208 120.216 ;
     RECT  10.804 121.536 13.208 121.56 ;
     RECT  13.208 2.148 13.312 168.492 ;
     RECT  13.312 2.418 13.504 168.222 ;
     RECT  13.504 74.976 13.853 75.192 ;
     RECT  13.504 120.192 14.821 120.216 ;
     RECT  13.504 121.536 14.821 121.56 ;
     RECT  14.821 120.048 14.861 120.216 ;
     RECT  14.821 121.536 14.861 121.656 ;
     RECT  13.504 41.376 15.908 41.4 ;
     RECT  13.853 75.168 15.908 75.192 ;
     RECT  14.861 120.048 15.908 120.072 ;
     RECT  14.861 121.632 15.908 121.656 ;
     RECT  15.908 2.148 16.012 168.492 ;
     RECT  16.012 2.418 16.204 168.222 ;
     RECT  16.204 41.376 18.608 41.4 ;
     RECT  16.204 75.168 18.608 75.192 ;
     RECT  16.204 120.048 18.608 120.072 ;
     RECT  16.204 121.632 18.608 121.656 ;
     RECT  18.608 2.148 18.712 168.492 ;
     RECT  18.712 2.418 18.904 168.222 ;
     RECT  18.904 41.376 21.308 41.4 ;
     RECT  18.904 75.168 21.308 75.192 ;
     RECT  18.904 120.048 21.308 120.072 ;
     RECT  18.904 121.536 21.308 121.56 ;
     RECT  21.308 2.148 21.412 168.492 ;
     RECT  21.412 2.418 21.604 168.222 ;
     RECT  21.604 99.552 22.141 99.672 ;
     RECT  21.604 93.312 22.211 93.48 ;
     RECT  22.141 99.552 22.385 99.576 ;
     RECT  21.604 75.168 22.499 75.192 ;
     RECT  22.211 93.312 22.499 93.336 ;
     RECT  21.604 119.712 22.637 120.216 ;
     RECT  21.604 121.536 23.893 121.56 ;
     RECT  21.604 41.376 24.008 41.4 ;
     RECT  22.637 120.192 24.008 120.216 ;
     RECT  23.893 121.536 24.008 121.656 ;
     RECT  21.604 142.944 24.008 142.968 ;
     RECT  24.008 2.148 24.112 168.492 ;
     RECT  24.112 2.418 24.304 168.222 ;
     RECT  24.304 41.376 26.708 41.4 ;
     RECT  24.304 120.048 26.708 120.072 ;
     RECT  24.304 121.632 26.708 121.656 ;
     RECT  24.304 142.944 26.708 142.968 ;
     RECT  26.708 2.148 26.812 168.492 ;
     RECT  26.812 2.418 27.004 168.222 ;
     RECT  27.004 41.376 29.408 41.4 ;
     RECT  27.004 120.048 29.408 120.072 ;
     RECT  27.004 121.632 29.408 121.656 ;
     RECT  27.004 142.944 29.408 142.968 ;
     RECT  29.408 2.148 29.512 168.492 ;
     RECT  29.512 2.418 29.704 168.222 ;
     RECT  29.704 120.048 29.801 120.216 ;
     RECT  29.801 120.192 30.769 120.216 ;
     RECT  29.704 121.536 30.769 121.56 ;
     RECT  30.769 120.048 30.809 120.216 ;
     RECT  30.769 121.536 30.809 121.656 ;
     RECT  29.704 41.376 32.108 41.4 ;
     RECT  30.809 120.048 32.108 120.072 ;
     RECT  30.809 121.632 32.108 121.656 ;
     RECT  29.704 142.944 32.108 142.968 ;
     RECT  32.108 2.148 32.212 168.492 ;
     RECT  32.212 2.418 32.404 168.222 ;
     RECT  34.357 131.52 34.693 131.544 ;
     RECT  34.621 124.08 34.765 124.104 ;
     RECT  32.404 41.376 34.808 41.4 ;
     RECT  32.404 120.048 34.808 120.072 ;
     RECT  32.404 121.632 34.808 121.656 ;
     RECT  34.549 122.736 34.808 122.76 ;
     RECT  34.765 124.08 34.808 124.92 ;
     RECT  34.549 125.952 34.808 125.976 ;
     RECT  34.369 129.408 34.808 129.432 ;
     RECT  34.325 130.512 34.808 130.536 ;
     RECT  34.693 131.52 34.808 132.216 ;
     RECT  32.404 142.944 34.808 142.968 ;
     RECT  34.808 2.148 34.912 168.492 ;
     RECT  34.912 2.418 35.104 168.222 ;
     RECT  35.104 128.88 35.165 132.792 ;
     RECT  35.104 121.392 35.219 124.92 ;
     RECT  35.165 129.936 35.315 132.792 ;
     RECT  35.104 134.112 35.345 135.672 ;
     RECT  35.315 129.936 35.363 131.688 ;
     RECT  35.219 121.392 35.452 124.248 ;
     RECT  35.452 121.392 35.597 124.104 ;
     RECT  35.104 125.952 35.669 127.848 ;
     RECT  35.597 121.44 35.921 124.104 ;
     RECT  35.669 125.952 35.921 126.504 ;
     RECT  35.921 121.44 35.939 123.72 ;
     RECT  35.921 125.952 35.957 125.976 ;
     RECT  35.363 129.936 36.035 131.64 ;
     RECT  35.315 132.768 36.035 132.792 ;
     RECT  35.345 135.648 36.037 135.672 ;
     RECT  35.104 118.896 36.092 120.072 ;
     RECT  35.165 128.88 36.101 128.904 ;
     RECT  36.035 129.936 36.101 131.112 ;
     RECT  36.092 118.896 36.133 120.264 ;
     RECT  35.939 121.44 36.173 122.28 ;
     RECT  35.939 123.504 36.173 123.72 ;
     RECT  36.173 121.44 36.217 121.656 ;
     RECT  36.133 117.84 36.275 120.264 ;
     RECT  36.217 121.536 36.275 121.656 ;
     RECT  36.229 128.832 36.316 128.856 ;
     RECT  35.345 134.112 36.421 134.136 ;
     RECT  36.421 133.824 36.601 134.136 ;
     RECT  36.169 136.08 36.601 136.104 ;
     RECT  36.601 133.824 36.62 134.568 ;
     RECT  35.669 127.632 36.961 127.848 ;
     RECT  36.275 118.896 36.997 120.264 ;
     RECT  36.601 136.08 37.069 136.92 ;
     RECT  36.101 130.464 37.105 131.112 ;
     RECT  36.173 123.504 37.213 123.672 ;
     RECT  36.275 117.84 37.237 117.864 ;
     RECT  36.997 118.896 37.237 120.504 ;
     RECT  36.275 121.632 37.237 121.656 ;
     RECT  37.105 129.888 37.237 131.112 ;
     RECT  37.148 138.96 37.237 138.984 ;
     RECT  37.237 115.584 37.333 115.608 ;
     RECT  36.62 133.2 37.333 134.568 ;
     RECT  37.237 148.176 37.333 148.2 ;
     RECT  37.333 147.648 37.381 148.2 ;
     RECT  36.961 127.056 37.429 127.848 ;
     RECT  37.333 132.48 37.501 134.568 ;
     RECT  35.104 41.376 37.508 41.4 ;
     RECT  37.381 97.632 37.508 97.656 ;
     RECT  37.34 99.024 37.508 99.048 ;
     RECT  37.333 115.584 37.508 115.704 ;
     RECT  37.237 117.84 37.508 121.656 ;
     RECT  37.213 123.504 37.508 124.344 ;
     RECT  37.429 126.96 37.508 127.848 ;
     RECT  37.237 129.216 37.508 131.112 ;
     RECT  37.501 132.384 37.508 134.568 ;
     RECT  37.069 135.648 37.508 136.92 ;
     RECT  37.069 137.904 37.508 137.928 ;
     RECT  37.237 138.96 37.508 139.656 ;
     RECT  37.189 141.264 37.508 141.288 ;
     RECT  35.104 142.944 37.508 142.968 ;
     RECT  37.381 147.648 37.508 148.584 ;
     RECT  37.381 165.888 37.508 165.912 ;
     RECT  37.508 2.148 37.612 168.492 ;
     RECT  37.612 2.418 37.804 168.222 ;
     RECT  37.804 127.248 37.865 127.272 ;
     RECT  37.804 120.048 37.955 120.504 ;
     RECT  37.804 121.584 37.955 122.232 ;
     RECT  37.804 123.456 37.955 124.68 ;
     RECT  37.825 170.4 37.957 170.424 ;
     RECT  37.804 137.184 38.009 137.352 ;
     RECT  37.804 140.208 38.009 141.288 ;
     RECT  37.957 170.4 38.044 170.52 ;
     RECT  37.804 142.32 38.147 144.696 ;
     RECT  37.804 157.344 38.147 157.896 ;
     RECT  37.804 165.024 38.147 166.248 ;
     RECT  38.044 170.4 38.147 170.424 ;
     RECT  37.804 148.8 38.153 149.4 ;
     RECT  37.804 153.408 38.153 153.912 ;
     RECT  37.804 130.992 38.195 135.672 ;
     RECT  38.009 140.736 38.195 141.288 ;
     RECT  38.153 153.888 38.195 153.912 ;
     RECT  38.147 157.344 38.225 157.368 ;
     RECT  38.147 142.32 38.233 144.6 ;
     RECT  37.804 162.048 38.261 163.56 ;
     RECT  38.195 140.784 38.291 141.288 ;
     RECT  38.195 130.992 38.297 135.528 ;
     RECT  38.233 142.32 38.332 143.736 ;
     RECT  38.147 165.024 38.339 165.912 ;
     RECT  38.339 165.792 38.369 165.912 ;
     RECT  38.332 142.512 38.387 143.736 ;
     RECT  38.369 165.888 38.483 165.912 ;
     RECT  38.387 142.944 38.613 143.736 ;
     RECT  38.261 163.008 38.621 163.56 ;
     RECT  37.955 123.6 38.765 124.68 ;
     RECT  38.765 123.6 38.801 124.344 ;
     RECT  38.801 123.6 38.873 124.248 ;
     RECT  38.873 123.6 38.941 124.008 ;
     RECT  38.917 76.08 38.965 76.104 ;
     RECT  38.897 96.912 38.981 96.936 ;
     RECT  38.941 123.12 38.981 124.008 ;
     RECT  38.965 75.84 39.004 76.104 ;
     RECT  38.924 54.528 39.011 54.552 ;
     RECT  38.297 130.992 39.013 133.704 ;
     RECT  39.077 150.48 39.116 150.504 ;
     RECT  39.004 75.84 39.125 75.864 ;
     RECT  38.153 149.328 39.155 149.4 ;
     RECT  39.116 150.48 39.161 151.032 ;
     RECT  39.161 151.008 39.203 151.032 ;
     RECT  38.621 163.008 39.203 163.032 ;
     RECT  38.977 126.336 39.229 126.36 ;
     RECT  38.291 140.784 39.233 140.808 ;
     RECT  37.955 121.584 39.301 121.656 ;
     RECT  37.804 48.48 39.337 48.504 ;
     RECT  37.804 93.744 39.373 93.768 ;
     RECT  39.013 130.704 39.373 133.704 ;
     RECT  38.297 135.024 39.373 135.528 ;
     RECT  37.804 128.256 39.404 129.24 ;
     RECT  39.404 127.968 39.452 129.24 ;
     RECT  39.373 130.704 39.481 135.528 ;
     RECT  39.229 125.472 39.517 126.36 ;
     RECT  38.905 137.568 39.517 137.592 ;
     RECT  39.337 48.48 39.589 48.744 ;
     RECT  39.517 125.472 39.589 126.456 ;
     RECT  39.452 127.968 39.589 129.336 ;
     RECT  37.804 91.344 39.625 91.368 ;
     RECT  39.373 93.36 39.692 93.768 ;
     RECT  39.517 88.944 39.697 88.968 ;
     RECT  38.941 90.048 39.697 90.072 ;
     RECT  39.625 91.104 39.697 91.368 ;
     RECT  37.804 83.76 39.733 83.784 ;
     RECT  39.697 88.944 39.733 91.368 ;
     RECT  39.553 49.776 39.769 49.8 ;
     RECT  38.869 50.88 39.769 50.904 ;
     RECT  37.804 41.376 39.829 41.4 ;
     RECT  39.589 47.856 39.913 48.744 ;
     RECT  39.769 49.776 39.913 50.904 ;
     RECT  39.733 88.944 39.913 91.608 ;
     RECT  39.692 93.36 39.913 94.008 ;
     RECT  39.913 88.944 40.021 94.008 ;
     RECT  39.589 106.896 40.028 106.92 ;
     RECT  37.955 120.048 40.069 120.072 ;
     RECT  39.301 121.584 40.069 121.704 ;
     RECT  39.481 130.656 40.093 135.528 ;
     RECT  39.517 136.8 40.093 137.592 ;
     RECT  39.829 40.896 40.208 41.4 ;
     RECT  40.129 45.984 40.208 46.008 ;
     RECT  39.913 47.856 40.208 50.904 ;
     RECT  37.804 51.888 40.208 51.912 ;
     RECT  39.733 83.76 40.208 84.12 ;
     RECT  40.021 88.32 40.208 94.008 ;
     RECT  39.733 95.088 40.208 95.112 ;
     RECT  39.805 96.192 40.208 96.216 ;
     RECT  40.028 106.896 40.208 107.016 ;
     RECT  37.804 117.84 40.208 117.864 ;
     RECT  40.069 120.048 40.208 120.6 ;
     RECT  40.069 121.584 40.208 122.136 ;
     RECT  38.981 123.12 40.208 123.144 ;
     RECT  39.589 125.472 40.208 129.336 ;
     RECT  40.093 130.656 40.208 137.592 ;
     RECT  39.445 140.208 40.208 140.232 ;
     RECT  39.553 141.36 40.208 141.384 ;
     RECT  38.613 142.944 40.208 142.968 ;
     RECT  39.155 149.328 40.208 149.352 ;
     RECT  40.208 2.148 40.312 168.492 ;
     RECT  40.312 2.418 40.504 168.222 ;
     RECT  40.504 120.576 40.817 126.024 ;
     RECT  40.504 87.936 40.825 97.464 ;
     RECT  40.504 141.312 40.933 141.336 ;
     RECT  40.817 123.744 41.027 126.024 ;
     RECT  40.504 127.248 41.027 128.424 ;
     RECT  41.027 127.248 41.033 127.992 ;
     RECT  40.504 142.512 41.033 142.536 ;
     RECT  41.027 123.84 41.075 126.024 ;
     RECT  40.817 120.576 41.141 122.568 ;
     RECT  41.075 123.84 41.429 124.296 ;
     RECT  40.504 114.528 41.465 114.552 ;
     RECT  41.075 125.424 41.497 126.024 ;
     RECT  41.033 127.248 41.497 127.416 ;
     RECT  40.504 140.16 41.497 140.184 ;
     RECT  40.504 131.52 41.533 131.544 ;
     RECT  40.504 137.472 41.533 139.032 ;
     RECT  41.497 140.064 41.533 140.184 ;
     RECT  41.497 125.424 41.537 127.416 ;
     RECT  40.504 47.904 41.569 51.096 ;
     RECT  41.533 137.472 41.569 140.184 ;
     RECT  40.504 45.504 41.605 46.2 ;
     RECT  41.569 47.424 41.605 51.192 ;
     RECT  41.537 125.424 41.609 127.272 ;
     RECT  41.605 45.504 41.641 51.576 ;
     RECT  40.504 52.608 41.641 53.784 ;
     RECT  40.504 132.864 41.641 132.888 ;
     RECT  40.504 134.208 41.641 136.248 ;
     RECT  41.609 125.424 41.717 126.024 ;
     RECT  40.504 83.76 41.749 84.12 ;
     RECT  41.749 114 41.833 114.024 ;
     RECT  41.641 132.864 41.893 136.248 ;
     RECT  41.533 131.136 41.965 131.544 ;
     RECT  41.893 132.672 41.965 136.248 ;
     RECT  41.677 44.448 42.073 44.472 ;
     RECT  41.641 45.504 42.073 53.784 ;
     RECT  41.749 129.408 42.083 129.432 ;
     RECT  40.825 87.936 42.145 96.888 ;
     RECT  41.141 121.392 42.145 122.568 ;
     RECT  42.145 120.768 42.181 122.568 ;
     RECT  42.073 44.448 42.289 53.784 ;
     RECT  41.429 124.272 42.325 124.296 ;
     RECT  41.717 125.424 42.325 125.496 ;
     RECT  41.749 83.568 42.373 84.12 ;
     RECT  42.145 87.36 42.373 96.888 ;
     RECT  42.373 83.184 42.469 84.12 ;
     RECT  41.965 131.136 42.469 136.248 ;
     RECT  42.181 120.096 42.476 122.568 ;
     RECT  42.289 44.352 42.517 53.784 ;
     RECT  42.469 82.656 42.613 84.12 ;
     RECT  42.517 44.16 42.661 53.784 ;
     RECT  42.565 64.704 42.661 64.728 ;
     RECT  42.613 107.28 42.709 107.304 ;
     RECT  42.469 130.56 42.709 136.248 ;
     RECT  42.661 64.608 42.757 64.728 ;
     RECT  40.504 40.896 42.908 40.92 ;
     RECT  42.757 64.608 42.908 64.968 ;
     RECT  42.613 82.656 42.908 84.36 ;
     RECT  42.709 107.28 42.908 108.216 ;
     RECT  40.504 117.84 42.908 117.864 ;
     RECT  42.476 120.096 42.908 123.144 ;
     RECT  42.325 124.272 42.908 125.496 ;
     RECT  41.609 127.248 42.908 127.272 ;
     RECT  42.908 2.148 43.012 41.052 ;
     RECT  42.908 62.628 43.012 84.36 ;
     RECT  42.908 105.828 43.012 127.452 ;
     RECT  42.908 149.028 43.012 168.492 ;
     RECT  42.373 86.592 43.045 96.888 ;
     RECT  42.709 130.368 43.081 136.248 ;
     RECT  43.081 129.456 43.2 136.248 ;
     RECT  41.569 137.28 43.2 140.184 ;
     RECT  43.012 2.418 43.204 40.92 ;
     RECT  43.012 62.898 43.204 84.36 ;
     RECT  43.012 106.098 43.204 127.272 ;
     RECT  43.012 149.298 43.204 168.222 ;
     RECT  43.204 64.608 43.229 64.968 ;
     RECT  43.204 107.28 43.265 108.552 ;
     RECT  42.661 43.968 43.272 53.784 ;
     RECT  40.504 61.056 43.272 61.128 ;
     RECT  43.045 86.592 43.272 96.984 ;
     RECT  40.504 103.776 43.272 104.328 ;
     RECT  43.2 129.456 43.272 140.184 ;
     RECT  40.504 147.072 43.272 147.144 ;
     RECT  43.229 64.608 43.331 64.872 ;
     RECT  43.272 129.456 43.331 147.144 ;
     RECT  43.265 108.192 43.409 108.552 ;
     RECT  43.331 64.608 43.553 64.728 ;
     RECT  43.204 83.28 43.553 84.36 ;
     RECT  43.204 40.896 45.608 40.92 ;
     RECT  43.553 83.76 45.608 84.12 ;
     RECT  43.204 117.84 45.608 117.864 ;
     RECT  43.204 121.584 45.608 121.608 ;
     RECT  43.204 127.248 45.608 127.272 ;
     RECT  45.608 2.148 45.712 41.052 ;
     RECT  45.608 62.628 45.712 84.252 ;
     RECT  45.608 105.828 45.712 127.452 ;
     RECT  45.608 149.028 45.712 168.492 ;
     RECT  45.712 2.418 45.904 40.92 ;
     RECT  45.712 62.898 45.904 84.12 ;
     RECT  45.712 106.098 45.904 127.272 ;
     RECT  45.712 149.298 45.904 168.222 ;
     RECT  45.904 40.848 46.286 40.92 ;
     RECT  45.904 83.76 46.753 84.12 ;
     RECT  45.904 121.44 46.793 121.608 ;
     RECT  46.286 40.848 48.308 40.872 ;
     RECT  46.753 83.76 48.308 84.168 ;
     RECT  45.904 117.84 48.308 117.864 ;
     RECT  46.793 121.584 48.308 121.608 ;
     RECT  45.904 127.248 48.308 127.272 ;
     RECT  48.308 2.148 48.412 41.052 ;
     RECT  48.308 62.628 48.412 84.252 ;
     RECT  48.308 105.828 48.412 127.452 ;
     RECT  48.308 149.028 48.412 168.492 ;
     RECT  48.412 2.418 48.604 40.872 ;
     RECT  48.412 62.898 48.604 84.168 ;
     RECT  48.412 106.098 48.604 127.272 ;
     RECT  48.412 149.298 48.604 168.222 ;
     RECT  48.604 83.664 49.132 84.168 ;
     RECT  48.604 40.848 51.008 40.872 ;
     RECT  49.132 83.76 51.008 84.168 ;
     RECT  48.604 117.84 51.008 117.864 ;
     RECT  48.604 121.584 51.008 121.608 ;
     RECT  48.604 127.248 51.008 127.272 ;
     RECT  51.008 2.148 51.112 41.052 ;
     RECT  51.008 62.628 51.112 84.252 ;
     RECT  51.008 105.828 51.112 127.452 ;
     RECT  51.008 149.028 51.112 168.492 ;
     RECT  51.112 2.418 51.304 40.872 ;
     RECT  51.112 62.898 51.304 84.168 ;
     RECT  51.112 106.098 51.304 127.272 ;
     RECT  51.112 149.298 51.304 168.222 ;
     RECT  51.304 40.848 53.708 40.872 ;
     RECT  51.304 83.76 53.708 84.168 ;
     RECT  51.304 117.84 53.708 117.864 ;
     RECT  51.304 121.584 53.708 121.608 ;
     RECT  51.304 127.248 53.708 127.272 ;
     RECT  53.708 2.148 53.812 41.052 ;
     RECT  53.708 62.628 53.812 84.252 ;
     RECT  53.708 105.828 53.812 127.452 ;
     RECT  53.708 149.028 53.812 168.492 ;
     RECT  53.812 2.418 54.004 40.872 ;
     RECT  53.812 62.898 54.004 84.168 ;
     RECT  53.812 106.098 54.004 127.272 ;
     RECT  53.812 149.298 54.004 168.222 ;
     RECT  54.004 127.248 56.149 127.272 ;
     RECT  54.004 121.44 56.293 121.464 ;
     RECT  54.004 40.848 56.408 40.872 ;
     RECT  54.004 83.76 56.408 84.168 ;
     RECT  54.004 117.84 56.408 117.864 ;
     RECT  56.293 121.44 56.408 121.608 ;
     RECT  56.149 127.056 56.408 127.272 ;
     RECT  56.408 2.148 56.512 41.052 ;
     RECT  56.408 62.628 56.512 84.252 ;
     RECT  56.408 105.828 56.512 127.452 ;
     RECT  56.408 149.028 56.512 168.492 ;
     RECT  56.512 2.418 56.704 40.872 ;
     RECT  56.512 62.898 56.704 84.168 ;
     RECT  56.512 106.098 56.704 127.272 ;
     RECT  56.512 149.298 56.704 168.222 ;
     RECT  56.704 127.056 57.011 127.272 ;
     RECT  56.704 40.56 59.108 40.872 ;
     RECT  56.704 83.76 59.108 84.168 ;
     RECT  56.704 117.84 59.108 117.864 ;
     RECT  56.704 121.296 59.108 121.608 ;
     RECT  57.011 127.056 59.108 127.08 ;
     RECT  59.108 2.148 59.212 41.052 ;
     RECT  59.108 62.628 59.212 84.252 ;
     RECT  59.108 105.828 59.212 127.452 ;
     RECT  59.108 149.028 59.212 168.492 ;
     RECT  59.212 2.418 59.404 40.872 ;
     RECT  59.212 62.898 59.404 84.168 ;
     RECT  59.212 106.098 59.404 127.182 ;
     RECT  59.212 149.298 59.404 168.222 ;
     RECT  59.404 40.56 61.808 40.872 ;
     RECT  59.404 83.76 61.808 84.168 ;
     RECT  59.404 117.84 61.808 117.864 ;
     RECT  59.404 121.296 61.808 121.32 ;
     RECT  59.404 127.056 61.808 127.08 ;
     RECT  61.808 2.148 61.912 41.052 ;
     RECT  61.808 62.628 61.912 84.252 ;
     RECT  61.808 105.828 61.912 127.452 ;
     RECT  61.808 149.028 61.912 168.492 ;
     RECT  61.912 2.418 62.104 40.872 ;
     RECT  61.912 62.898 62.104 84.168 ;
     RECT  61.912 106.098 62.104 127.182 ;
     RECT  61.912 149.298 62.104 168.222 ;
     RECT  62.104 117.792 63.107 117.96 ;
     RECT  62.104 127.056 63.107 127.08 ;
     RECT  62.104 121.296 63.529 121.32 ;
     RECT  62.104 40.56 64.508 40.872 ;
     RECT  62.104 83.76 64.508 84.168 ;
     RECT  62.104 108.096 64.508 108.12 ;
     RECT  63.107 117.936 64.508 117.96 ;
     RECT  63.529 121.296 64.508 121.608 ;
     RECT  64.508 2.148 64.612 41.052 ;
     RECT  64.508 62.628 64.612 84.252 ;
     RECT  64.508 105.828 64.612 127.452 ;
     RECT  64.508 149.028 64.612 168.492 ;
     RECT  64.612 2.418 64.804 41.016 ;
     RECT  64.612 62.898 64.804 84.168 ;
     RECT  64.612 105.828 64.804 127.182 ;
     RECT  64.612 149.298 64.804 168.222 ;
     RECT  64.804 105.828 64.825 106.296 ;
     RECT  64.804 40.56 65.017 41.016 ;
     RECT  64.804 107.76 65.017 108.12 ;
     RECT  64.825 105.456 65.267 106.296 ;
     RECT  64.804 83.664 65.305 84.168 ;
     RECT  64.804 78.672 65.809 78.696 ;
     RECT  65.305 83.76 65.873 84.168 ;
     RECT  65.017 40.56 67.208 40.872 ;
     RECT  64.804 65.712 67.208 65.736 ;
     RECT  66.373 75.456 67.208 75.48 ;
     RECT  66.697 78.528 67.208 78.552 ;
     RECT  65.873 83.76 67.208 84.072 ;
     RECT  65.267 105.984 67.208 106.296 ;
     RECT  65.017 108.096 67.208 108.12 ;
     RECT  64.804 117.84 67.208 117.864 ;
     RECT  64.804 121.584 67.208 121.608 ;
     RECT  67.208 2.148 67.312 41.052 ;
     RECT  67.208 62.628 67.312 84.252 ;
     RECT  67.208 105.828 67.312 127.452 ;
     RECT  67.208 149.028 67.312 168.492 ;
     RECT  67.312 2.418 67.504 40.872 ;
     RECT  67.312 62.898 67.504 84.072 ;
     RECT  67.312 106.098 67.504 127.182 ;
     RECT  67.312 149.298 67.504 168.222 ;
     RECT  67.504 40.56 69.908 40.872 ;
     RECT  67.504 65.712 69.908 65.736 ;
     RECT  67.504 75.456 69.908 75.48 ;
     RECT  67.504 83.808 69.908 84.072 ;
     RECT  67.504 117.84 69.908 117.864 ;
     RECT  67.504 121.584 69.908 121.608 ;
     RECT  69.908 2.148 70.012 41.052 ;
     RECT  69.908 62.628 70.012 84.252 ;
     RECT  69.908 105.828 70.012 127.452 ;
     RECT  69.908 149.028 70.012 168.492 ;
     RECT  70.012 2.418 70.204 40.872 ;
     RECT  70.012 62.898 70.204 84.252 ;
     RECT  70.012 106.098 70.204 127.182 ;
     RECT  70.012 149.298 70.204 168.222 ;
     RECT  70.204 83.808 70.697 84.252 ;
     RECT  70.204 121.44 70.733 121.608 ;
     RECT  70.697 83.952 70.801 84.252 ;
     RECT  70.204 40.56 72.608 40.872 ;
     RECT  70.204 65.712 72.608 65.736 ;
     RECT  70.204 75.456 72.608 75.48 ;
     RECT  70.801 83.952 72.608 84.36 ;
     RECT  70.204 117.84 72.608 117.864 ;
     RECT  70.733 121.584 72.608 121.608 ;
     RECT  72.608 2.148 72.712 41.052 ;
     RECT  72.608 62.628 72.712 84.36 ;
     RECT  72.608 105.828 72.712 127.452 ;
     RECT  72.608 149.028 72.712 168.492 ;
     RECT  72.712 2.418 72.904 40.872 ;
     RECT  72.712 62.898 72.904 84.36 ;
     RECT  72.712 106.098 72.904 127.182 ;
     RECT  72.712 149.298 72.904 168.222 ;
     RECT  72.904 121.584 73.811 121.608 ;
     RECT  72.904 124.224 73.837 125.64 ;
     RECT  43.331 129.6 74.689 147.144 ;
     RECT  43.272 43.2 74.941 61.128 ;
     RECT  72.904 40.56 75.085 40.872 ;
     RECT  74.941 42.768 75.12 61.128 ;
     RECT  43.272 86.4 75.12 104.328 ;
     RECT  74.689 128.784 75.12 147.144 ;
     RECT  75.085 40.56 75.157 41.352 ;
     RECT  72.904 84.048 75.157 84.36 ;
     RECT  75.12 128.784 75.157 128.808 ;
     RECT  73.837 124.224 75.193 124.248 ;
     RECT  75.157 40.56 75.244 41.64 ;
     RECT  75.12 42.768 75.305 53.88 ;
     RECT  75.12 87.168 75.305 96.984 ;
     RECT  75.244 40.56 75.308 41.352 ;
     RECT  72.904 65.712 75.308 65.736 ;
     RECT  72.904 75.456 75.308 75.48 ;
     RECT  75.157 84.048 75.308 84.984 ;
     RECT  72.904 117.84 75.308 117.864 ;
     RECT  75.193 124.224 75.308 124.536 ;
     RECT  73.837 125.616 75.308 125.64 ;
     RECT  75.121 127.008 75.308 127.032 ;
     RECT  75.157 128.256 75.308 128.808 ;
     RECT  75.305 44.064 75.341 53.88 ;
     RECT  75.308 105.828 75.341 128.808 ;
     RECT  75.12 130.32 75.341 140.184 ;
     RECT  75.305 42.768 75.377 43.08 ;
     RECT  75.341 44.064 75.377 53.688 ;
     RECT  75.308 2.148 75.412 41.352 ;
     RECT  75.308 62.628 75.412 84.984 ;
     RECT  75.341 105.828 75.412 128.28 ;
     RECT  75.308 149.028 75.412 168.492 ;
     RECT  75.412 62.898 75.413 84.984 ;
     RECT  75.412 128.256 75.449 128.28 ;
     RECT  75.305 87.264 75.485 96.984 ;
     RECT  75.12 58.704 75.521 58.728 ;
     RECT  75.12 147.072 75.557 147.144 ;
     RECT  75.412 2.418 75.604 41.352 ;
     RECT  75.413 62.898 75.604 84.36 ;
     RECT  75.412 106.098 75.604 127.272 ;
     RECT  75.412 149.298 75.604 168.222 ;
     RECT  75.557 147.12 75.665 147.144 ;
     RECT  75.377 44.064 75.701 53.592 ;
     RECT  75.12 103.776 75.701 104.328 ;
     RECT  75.604 40.56 75.779 41.352 ;
     RECT  75.377 42.768 75.827 42.792 ;
     RECT  75.604 82.752 76.643 84.36 ;
     RECT  75.485 87.264 76.673 96.696 ;
     RECT  75.341 130.32 76.709 139.992 ;
     RECT  75.604 73.296 76.741 73.32 ;
     RECT  76.709 130.32 76.781 139.896 ;
     RECT  76.741 72.96 76.825 73.32 ;
     RECT  76.825 73.296 76.931 73.32 ;
     RECT  75.604 126.144 77.461 127.272 ;
     RECT  76.741 70.656 77.893 70.68 ;
     RECT  75.779 40.56 78.008 40.872 ;
     RECT  75.701 44.064 78.008 53.496 ;
     RECT  75.12 61.056 78.008 61.128 ;
     RECT  75.604 65.712 78.008 65.736 ;
     RECT  77.893 68.16 78.008 68.184 ;
     RECT  77.893 70.512 78.008 70.68 ;
     RECT  75.604 75.456 78.008 75.48 ;
     RECT  76.643 82.752 78.008 84.12 ;
     RECT  76.673 87.264 78.008 96.6 ;
     RECT  75.701 104.304 78.008 104.328 ;
     RECT  75.604 117.84 78.008 117.864 ;
     RECT  77.461 126.144 78.008 128.088 ;
     RECT  76.781 130.32 78.008 139.608 ;
     RECT  78.008 2.148 78.112 168.492 ;
     RECT  78.112 2.418 78.304 168.222 ;
     RECT  78.304 67.824 78.473 67.848 ;
     RECT  78.304 61.056 78.689 61.176 ;
     RECT  78.304 65.712 78.905 65.832 ;
     RECT  78.304 40.56 79.523 40.872 ;
     RECT  78.304 44.064 79.585 47.688 ;
     RECT  79.523 40.56 80.708 40.584 ;
     RECT  79.585 44.064 80.708 47.88 ;
     RECT  78.689 61.104 80.708 61.176 ;
     RECT  78.905 65.712 80.708 65.736 ;
     RECT  78.304 82.752 80.708 84.12 ;
     RECT  80.377 85.104 80.708 85.128 ;
     RECT  78.304 87.264 80.708 90.888 ;
     RECT  78.304 104.304 80.708 104.328 ;
     RECT  78.304 117.84 80.708 117.864 ;
     RECT  78.304 126.144 80.708 128.616 ;
     RECT  78.304 130.32 80.708 134.04 ;
     RECT  80.708 2.148 80.812 168.492 ;
     RECT  80.812 2.418 81.004 168.222 ;
     RECT  81.004 87.264 82.033 90.888 ;
     RECT  81.004 126.144 83.077 128.616 ;
     RECT  81.004 40.56 83.408 40.584 ;
     RECT  81.004 44.064 83.408 47.88 ;
     RECT  81.004 61.104 83.408 61.176 ;
     RECT  81.004 65.712 83.408 65.736 ;
     RECT  82.885 77.952 83.408 77.976 ;
     RECT  81.004 82.752 83.408 84.12 ;
     RECT  81.004 85.104 83.408 85.128 ;
     RECT  82.033 86.544 83.408 90.888 ;
     RECT  81.004 104.304 83.408 104.328 ;
     RECT  81.004 117.84 83.408 117.864 ;
     RECT  83.077 125.904 83.408 128.616 ;
     RECT  81.004 130.56 83.408 134.04 ;
     RECT  83.408 2.148 83.512 168.492 ;
     RECT  83.512 2.418 83.704 168.222 ;
     RECT  83.704 82.752 84.733 84.072 ;
     RECT  83.704 85.104 84.733 85.128 ;
     RECT  83.704 86.544 84.737 90.888 ;
     RECT  84.733 82.752 84.949 85.128 ;
     RECT  84.949 82.656 85.057 85.128 ;
     RECT  85.057 82.416 85.477 85.128 ;
     RECT  85.477 82.224 85.561 85.128 ;
     RECT  83.704 40.56 86.108 40.584 ;
     RECT  83.704 44.064 86.108 47.88 ;
     RECT  83.704 61.104 86.108 61.176 ;
     RECT  83.704 65.712 86.108 65.736 ;
     RECT  83.704 77.952 86.108 77.976 ;
     RECT  85.561 82.224 86.108 85.416 ;
     RECT  84.737 86.544 86.108 86.568 ;
     RECT  84.737 87.552 86.108 90.888 ;
     RECT  83.704 104.304 86.108 104.328 ;
     RECT  83.704 117.84 86.108 117.864 ;
     RECT  83.704 125.904 86.108 126.504 ;
     RECT  83.704 127.536 86.108 128.616 ;
     RECT  83.704 130.56 86.108 134.04 ;
     RECT  86.108 2.148 86.212 168.492 ;
     RECT  86.212 2.418 86.404 168.222 ;
     RECT  86.404 117.84 86.579 117.864 ;
     RECT  86.404 138.576 86.579 139.032 ;
     RECT  86.404 61.056 86.681 61.176 ;
     RECT  86.404 77.952 86.681 78.072 ;
     RECT  86.404 116.832 86.681 116.856 ;
     RECT  86.404 130.56 86.915 134.04 ;
     RECT  86.404 86.496 87.005 86.568 ;
     RECT  86.404 140.784 87.041 141.528 ;
     RECT  86.579 139.008 88.021 139.032 ;
     RECT  88.021 139.008 88.513 139.128 ;
     RECT  86.404 40.56 88.808 40.584 ;
     RECT  86.404 44.064 88.808 47.88 ;
     RECT  86.681 61.104 88.808 61.176 ;
     RECT  86.404 65.712 88.808 65.736 ;
     RECT  86.681 77.952 88.808 77.976 ;
     RECT  86.404 82.224 88.808 82.44 ;
     RECT  86.404 83.568 88.808 85.416 ;
     RECT  87.005 86.496 88.808 86.52 ;
     RECT  86.404 87.552 88.808 90.888 ;
     RECT  86.404 104.304 88.808 104.328 ;
     RECT  87.757 116.256 88.808 116.28 ;
     RECT  86.404 125.904 88.808 126.504 ;
     RECT  86.404 127.536 88.808 128.184 ;
     RECT  86.915 130.56 88.808 133.032 ;
     RECT  86.915 134.016 88.808 134.04 ;
     RECT  88.513 138.96 88.808 139.128 ;
     RECT  87.041 140.784 88.808 140.856 ;
     RECT  88.808 2.148 88.912 168.492 ;
     RECT  88.912 2.418 89.104 168.222 ;
     RECT  89.104 39.024 89.219 40.584 ;
     RECT  89.104 77.952 89.219 77.976 ;
     RECT  89.104 100.8 89.219 100.824 ;
     RECT  89.104 116.256 89.417 116.856 ;
     RECT  89.417 116.4 89.459 116.856 ;
     RECT  89.104 125.808 89.459 128.856 ;
     RECT  89.104 41.76 89.507 47.88 ;
     RECT  89.104 82.128 89.507 86.52 ;
     RECT  89.459 116.832 89.507 116.856 ;
     RECT  89.104 54.336 89.525 54.648 ;
     RECT  89.104 55.632 89.561 57.24 ;
     RECT  89.104 99.168 89.633 99.72 ;
     RECT  89.104 142.464 89.843 143.112 ;
     RECT  89.633 99.696 89.849 99.72 ;
     RECT  89.843 142.464 89.884 142.488 ;
     RECT  89.104 138.96 90.205 138.984 ;
     RECT  90.205 138.96 90.245 139.656 ;
     RECT  89.459 125.904 90.281 126.552 ;
     RECT  89.561 55.632 90.349 57 ;
     RECT  89.219 39.024 90.373 39.912 ;
     RECT  89.104 97.296 90.389 98.184 ;
     RECT  90.281 125.952 90.419 126.552 ;
     RECT  90.373 38.112 90.433 39.912 ;
     RECT  89.104 107.136 90.461 107.16 ;
     RECT  89.507 41.904 90.497 47.88 ;
     RECT  90.349 55.44 90.565 57 ;
     RECT  90.389 97.44 90.565 98.184 ;
     RECT  89.525 54.336 90.601 54.36 ;
     RECT  90.601 53.52 90.613 54.36 ;
     RECT  90.433 38.112 90.637 39.816 ;
     RECT  89.459 127.536 90.637 128.856 ;
     RECT  89.507 85.104 90.709 85.416 ;
     RECT  89.507 86.496 90.709 86.52 ;
     RECT  89.507 82.128 90.745 83.64 ;
     RECT  90.709 85.104 90.745 86.52 ;
     RECT  90.565 55.44 90.781 57.096 ;
     RECT  90.529 100.08 90.781 100.104 ;
     RECT  90.419 126.192 90.781 126.552 ;
     RECT  90.637 127.536 90.781 128.952 ;
     RECT  90.565 97.44 90.817 98.472 ;
     RECT  90.745 82.128 90.901 86.52 ;
     RECT  89.104 140.784 90.961 140.856 ;
     RECT  89.104 130.56 90.997 133.032 ;
     RECT  90.245 139.104 90.997 139.656 ;
     RECT  90.961 140.784 90.997 141.384 ;
     RECT  90.817 97.44 91.105 98.52 ;
     RECT  90.781 100.08 91.105 101.064 ;
     RECT  90.613 52.992 91.133 54.36 ;
     RECT  91.133 52.464 91.141 54.36 ;
     RECT  90.781 55.44 91.141 57.336 ;
     RECT  91.177 143.28 91.381 143.304 ;
     RECT  90.961 40.896 91.465 40.92 ;
     RECT  90.497 41.904 91.465 44.712 ;
     RECT  90.637 37.968 91.508 39.816 ;
     RECT  91.465 40.896 91.508 44.712 ;
     RECT  90.497 45.696 91.508 47.88 ;
     RECT  91.141 52.464 91.508 57.336 ;
     RECT  89.104 61.104 91.508 61.176 ;
     RECT  89.104 65.712 91.508 65.736 ;
     RECT  90.901 82.128 91.508 86.568 ;
     RECT  89.104 87.552 91.508 90.888 ;
     RECT  91.105 97.44 91.508 101.064 ;
     RECT  89.104 104.304 91.508 104.328 ;
     RECT  90.601 106.992 91.508 107.016 ;
     RECT  89.104 124.8 91.508 124.824 ;
     RECT  90.781 126.192 91.508 128.952 ;
     RECT  90.997 129.936 91.508 133.032 ;
     RECT  90.565 138.048 91.508 138.072 ;
     RECT  90.997 139.104 91.508 141.384 ;
     RECT  91.381 142.8 91.508 143.544 ;
     RECT  91.508 2.148 91.612 168.492 ;
     RECT  91.612 2.418 91.804 168.222 ;
     RECT  91.804 126 91.865 130.584 ;
     RECT  91.804 54.144 91.901 57.336 ;
     RECT  91.804 46.272 92.009 47.064 ;
     RECT  91.804 88.704 92.009 90.888 ;
     RECT  92.009 88.704 92.153 89.784 ;
     RECT  91.804 131.904 92.261 133.032 ;
     RECT  91.865 126 92.339 129.96 ;
     RECT  91.804 139.44 92.339 143.544 ;
     RECT  92.339 129.936 92.369 129.96 ;
     RECT  92.339 139.44 92.387 141.336 ;
     RECT  92.009 90.864 92.477 90.888 ;
     RECT  92.261 131.904 92.549 132.408 ;
     RECT  91.804 69.456 92.627 70.68 ;
     RECT  91.901 54.288 92.693 57.336 ;
     RECT  92.627 69.456 92.723 70.104 ;
     RECT  92.723 69.648 92.764 70.104 ;
     RECT  91.804 81.408 92.797 85.416 ;
     RECT  91.804 96.336 92.797 96.36 ;
     RECT  91.804 39.024 92.821 39.912 ;
     RECT  91.804 37.968 92.828 37.992 ;
     RECT  92.821 38.976 92.828 39.912 ;
     RECT  92.339 126 92.833 128.952 ;
     RECT  92.828 37.968 92.867 39.912 ;
     RECT  92.867 37.968 92.915 39.576 ;
     RECT  92.009 46.608 92.945 47.064 ;
     RECT  92.945 47.04 93.017 47.064 ;
     RECT  92.153 88.704 93.157 89.496 ;
     RECT  92.764 70.08 93.203 70.104 ;
     RECT  92.549 132.24 93.205 132.408 ;
     RECT  93.157 77.52 93.265 77.544 ;
     RECT  92.797 81.408 93.265 85.512 ;
     RECT  91.804 86.496 93.265 87.576 ;
     RECT  93.265 81.408 93.301 87.576 ;
     RECT  93.301 81.408 93.337 87.72 ;
     RECT  93.157 88.704 93.337 89.544 ;
     RECT  91.804 52.8 93.349 53.064 ;
     RECT  93.265 77.52 93.349 78.024 ;
     RECT  93.349 52.368 93.373 53.064 ;
     RECT  92.797 96.24 93.373 96.36 ;
     RECT  91.804 97.392 93.373 101.064 ;
     RECT  92.387 141.312 93.404 141.336 ;
     RECT  92.339 142.56 93.404 143.544 ;
     RECT  93.337 81.408 93.481 89.544 ;
     RECT  93.301 47.76 93.589 47.784 ;
     RECT  91.804 65.712 93.589 65.736 ;
     RECT  92.833 125.712 93.589 128.952 ;
     RECT  93.157 129.984 93.589 130.392 ;
     RECT  93.589 125.712 93.697 130.392 ;
     RECT  93.697 125.712 93.74 131.112 ;
     RECT  92.693 54.336 93.769 57.336 ;
     RECT  92.387 139.44 93.788 139.992 ;
     RECT  93.788 139.44 93.829 140.232 ;
     RECT  93.404 141.312 93.829 143.544 ;
     RECT  93.349 77.52 93.841 78.072 ;
     RECT  93.829 139.44 93.884 143.544 ;
     RECT  93.373 96.24 93.913 101.064 ;
     RECT  93.481 81.408 93.925 90.072 ;
     RECT  93.884 139.44 93.925 143.88 ;
     RECT  92.915 37.968 94.021 37.992 ;
     RECT  92.915 38.976 94.021 39.576 ;
     RECT  91.804 40.896 94.021 44.376 ;
     RECT  93.769 54.144 94.021 57.336 ;
     RECT  93.973 80.256 94.021 80.28 ;
     RECT  93.925 81.36 94.021 90.072 ;
     RECT  91.804 138.048 94.021 138.072 ;
     RECT  93.925 139.44 94.021 144.552 ;
     RECT  93.373 51.888 94.057 53.064 ;
     RECT  94.021 54.144 94.057 57.384 ;
     RECT  94.021 37.44 94.208 39.576 ;
     RECT  94.021 40.56 94.208 44.376 ;
     RECT  93.589 47.76 94.208 48.456 ;
     RECT  94.057 51.888 94.208 57.384 ;
     RECT  91.804 61.104 94.208 61.176 ;
     RECT  93.589 65.712 94.208 66.12 ;
     RECT  93.841 77.52 94.208 78.12 ;
     RECT  94.021 80.256 94.208 90.072 ;
     RECT  93.913 96.192 94.208 101.064 ;
     RECT  91.804 104.304 94.208 104.328 ;
     RECT  93.74 125.376 94.208 131.112 ;
     RECT  93.205 132.384 94.208 132.408 ;
     RECT  94.021 138.048 94.208 144.552 ;
     RECT  94.208 2.148 94.312 168.492 ;
     RECT  94.312 2.418 94.504 168.222 ;
     RECT  94.504 87.744 94.643 87.864 ;
     RECT  94.643 87.744 94.673 87.768 ;
     RECT  94.504 80.16 94.684 86.664 ;
     RECT  94.504 52.8 94.739 57.624 ;
     RECT  94.504 61.104 95.033 61.176 ;
     RECT  94.739 52.8 95.497 57.384 ;
     RECT  95.497 52.704 95.564 57.384 ;
     RECT  95.033 61.152 95.573 61.176 ;
     RECT  94.684 80.16 95.645 86.52 ;
     RECT  94.504 125.616 95.701 129.24 ;
     RECT  94.504 51.36 95.708 51.384 ;
     RECT  94.504 96.144 95.708 101.592 ;
     RECT  95.701 125.424 95.708 129.24 ;
     RECT  95.708 51.36 95.749 51.528 ;
     RECT  95.564 52.56 95.749 57.384 ;
     RECT  95.645 80.16 95.749 85.848 ;
     RECT  95.708 124.656 95.749 129.24 ;
     RECT  95.749 51.216 95.795 51.528 ;
     RECT  95.708 96.048 95.795 101.592 ;
     RECT  95.795 51.216 95.843 51.384 ;
     RECT  95.749 124.416 95.843 129.432 ;
     RECT  95.749 80.112 95.891 85.848 ;
     RECT  94.504 37.44 95.933 44.52 ;
     RECT  95.843 51.36 95.933 51.384 ;
     RECT  95.891 80.16 95.933 85.848 ;
     RECT  95.795 96.192 95.933 101.592 ;
     RECT  94.504 137.76 95.933 144.552 ;
     RECT  95.933 80.352 95.939 85.848 ;
     RECT  95.939 80.64 95.987 85.848 ;
     RECT  95.987 80.88 96.005 85.848 ;
     RECT  95.933 38.736 96.227 44.472 ;
     RECT  95.933 96.48 96.227 101.496 ;
     RECT  95.843 125.136 96.227 129.432 ;
     RECT  96.227 96.48 96.275 101.016 ;
     RECT  96.227 129.408 96.275 129.432 ;
     RECT  95.933 138.96 96.275 144.36 ;
     RECT  96.227 38.736 96.323 43.944 ;
     RECT  95.749 52.56 96.323 57.624 ;
     RECT  96.275 96.48 96.323 100.92 ;
     RECT  96.227 125.136 96.323 128.328 ;
     RECT  96.275 138.96 96.323 144.264 ;
     RECT  96.323 96.48 97.441 100.824 ;
     RECT  96.323 38.736 98.22 43.224 ;
     RECT  96.323 52.56 98.22 57.048 ;
     RECT  96.005 81.36 98.22 85.848 ;
     RECT  97.441 96.336 98.22 100.824 ;
     RECT  96.323 125.136 98.22 128.184 ;
     RECT  96.323 138.96 98.22 143.448 ;
     RECT  98.22 100.272 98.273 100.296 ;
     RECT  98.22 125.616 98.273 125.64 ;
    LAYER M5 ;
     RECT  2.4 2.137 2.52 2.151 ;
     RECT  5.1 2.137 5.22 2.151 ;
     RECT  7.8 2.137 7.92 2.151 ;
     RECT  10.5 2.137 10.62 2.151 ;
     RECT  13.2 2.137 13.32 2.151 ;
     RECT  15.9 2.137 16.02 2.151 ;
     RECT  18.6 2.137 18.72 2.151 ;
     RECT  21.3 2.137 21.42 2.151 ;
     RECT  24 2.137 24.12 2.151 ;
     RECT  26.7 2.137 26.82 2.151 ;
     RECT  29.4 2.137 29.52 2.151 ;
     RECT  32.1 2.137 32.22 2.151 ;
     RECT  34.8 2.137 34.92 2.151 ;
     RECT  37.5 2.137 37.62 2.151 ;
     RECT  40.2 2.137 40.32 2.151 ;
     RECT  42.9 2.137 43.02 2.151 ;
     RECT  45.6 2.137 45.72 2.151 ;
     RECT  48.3 2.137 48.42 2.151 ;
     RECT  51 2.137 51.12 2.151 ;
     RECT  53.7 2.137 53.82 2.151 ;
     RECT  56.4 2.137 56.52 2.151 ;
     RECT  59.1 2.137 59.22 2.151 ;
     RECT  61.8 2.137 61.92 2.151 ;
     RECT  64.5 2.137 64.62 2.151 ;
     RECT  67.2 2.137 67.32 2.151 ;
     RECT  69.9 2.137 70.02 2.151 ;
     RECT  72.6 2.137 72.72 2.151 ;
     RECT  75.3 2.137 75.42 2.151 ;
     RECT  78 2.137 78.12 2.151 ;
     RECT  80.7 2.137 80.82 2.151 ;
     RECT  83.4 2.137 83.52 2.151 ;
     RECT  86.1 2.137 86.22 2.151 ;
     RECT  88.8 2.137 88.92 2.151 ;
     RECT  91.5 2.137 91.62 2.151 ;
     RECT  94.2 2.137 94.32 2.151 ;
     RECT  0.144 31.765 0.168 31.955 ;
     RECT  5.1 2.151 5.412 32.341 ;
     RECT  5.1 32.341 5.736 33.973 ;
     RECT  5.1 33.973 5.784 34.789 ;
     RECT  4.176 34.789 5.784 35.939 ;
     RECT  2.4 2.151 2.712 36.085 ;
     RECT  7.8 2.151 8.112 36.133 ;
     RECT  2.304 36.085 2.712 36.275 ;
     RECT  94.2 2.151 94.512 37.429 ;
     RECT  4.176 35.939 5.412 38.005 ;
     RECT  6.48 36.661 6.504 38.005 ;
     RECT  95.76 37.573 95.784 38.005 ;
     RECT  94.032 37.429 94.512 38.053 ;
     RECT  95.76 38.005 95.832 38.053 ;
     RECT  94.032 38.053 95.832 38.533 ;
     RECT  94.032 38.533 95.88 38.773 ;
     RECT  92.88 38.725 92.904 38.965 ;
     RECT  92.832 38.965 92.904 39.251 ;
     RECT  94.032 38.773 95.928 39.395 ;
     RECT  90.384 38.101 90.408 39.923 ;
     RECT  92.832 39.251 92.856 39.923 ;
     RECT  94.2 39.395 95.928 39.923 ;
     RECT  94.2 39.923 94.728 39.971 ;
     RECT  4.176 38.005 6.504 40.019 ;
     RECT  5.1 40.019 6.504 40.021 ;
     RECT  7.8 36.133 8.232 40.021 ;
     RECT  5.1 40.021 8.232 40.067 ;
     RECT  13.2 2.151 13.512 40.405 ;
     RECT  88.8 2.151 89.112 40.549 ;
     RECT  95.712 39.923 95.928 40.597 ;
     RECT  40.2 2.151 40.512 40.885 ;
     RECT  64.5 2.151 64.812 40.981 ;
     RECT  12.48 40.405 13.512 41.029 ;
     RECT  75.3 2.151 75.612 41.125 ;
     RECT  91.5 2.151 91.812 41.221 ;
     RECT  94.2 39.971 94.512 41.221 ;
     RECT  75.3 41.125 75.72 41.317 ;
     RECT  39.84 40.885 40.512 41.365 ;
     RECT  12.384 41.029 13.512 41.459 ;
     RECT  75.3 41.317 75.768 41.605 ;
     RECT  95.712 40.597 96.312 41.651 ;
     RECT  6.48 40.067 8.232 41.699 ;
     RECT  88.8 40.549 89.208 41.749 ;
     RECT  91.5 41.221 92.376 42.613 ;
     RECT  93.456 41.221 94.512 42.661 ;
     RECT  75.168 41.605 75.768 42.757 ;
     RECT  90.912 42.613 92.376 42.803 ;
     RECT  93.456 42.661 95.064 42.851 ;
     RECT  93.648 42.851 95.064 42.901 ;
     RECT  96.24 41.651 96.312 42.901 ;
     RECT  75.168 42.757 75.816 43.091 ;
     RECT  93.648 42.901 96.312 43.427 ;
     RECT  90.912 42.803 91.812 43.525 ;
     RECT  88.8 41.749 89.496 43.571 ;
     RECT  3.696 42.709 3.72 43.811 ;
     RECT  93.648 43.427 95.16 43.861 ;
     RECT  93.312 43.861 95.16 43.955 ;
     RECT  96.192 43.427 96.312 43.955 ;
     RECT  42.9 2.151 43.212 43.957 ;
     RECT  7.392 41.699 8.232 44.099 ;
     RECT  42.672 43.957 43.212 44.149 ;
     RECT  96.192 43.955 96.216 44.483 ;
     RECT  93.312 43.955 95.112 44.531 ;
     RECT  2.4 36.275 2.712 44.773 ;
     RECT  2.304 44.773 2.712 45.011 ;
     RECT  88.8 43.571 89.304 46.259 ;
     RECT  79.488 40.837 79.512 46.501 ;
     RECT  80.7 2.151 81.012 46.501 ;
     RECT  79.488 46.501 81.012 46.547 ;
     RECT  76.944 46.837 76.968 46.933 ;
     RECT  76.896 46.933 76.968 47.123 ;
     RECT  76.896 47.123 76.92 47.219 ;
     RECT  79.776 46.547 81.012 47.363 ;
     RECT  93.312 44.531 94.512 47.795 ;
     RECT  39.6 41.365 40.512 47.891 ;
     RECT  90.672 43.525 91.812 47.891 ;
     RECT  75.3 43.091 75.816 48.035 ;
     RECT  75.3 48.035 75.768 48.131 ;
     RECT  75.3 48.131 75.72 48.227 ;
     RECT  95.808 51.205 95.832 51.493 ;
     RECT  39.84 47.891 40.512 51.923 ;
     RECT  93.408 47.795 94.512 52.357 ;
     RECT  95.76 51.493 95.832 52.549 ;
     RECT  95.616 52.549 95.832 52.883 ;
     RECT  91.152 47.891 91.812 52.981 ;
     RECT  93.36 52.357 94.512 53.075 ;
     RECT  95.616 52.883 95.64 53.459 ;
     RECT  90.624 52.981 91.812 53.555 ;
     RECT  40.2 51.923 40.512 53.557 ;
     RECT  91.152 53.555 91.812 54.277 ;
     RECT  93.6 53.075 94.512 54.421 ;
     RECT  91.152 54.277 92.424 54.517 ;
     RECT  93.6 54.421 95.256 54.517 ;
     RECT  91.152 54.517 95.256 54.755 ;
     RECT  91.5 54.755 95.256 55.141 ;
     RECT  96.288 54.277 96.312 55.141 ;
     RECT  88.8 46.259 89.208 55.621 ;
     RECT  91.5 55.141 96.312 55.907 ;
     RECT  95.712 55.907 96.312 55.955 ;
     RECT  88.8 55.621 89.784 56.531 ;
     RECT  91.5 55.907 91.812 56.917 ;
     RECT  93.072 55.907 94.728 56.917 ;
     RECT  91.5 56.917 94.728 57.635 ;
     RECT  96.288 55.955 96.312 57.635 ;
     RECT  40.2 53.557 40.92 61.139 ;
     RECT  42.528 44.149 43.212 64.837 ;
     RECT  64.5 40.981 64.968 65.701 ;
     RECT  78 2.151 78.312 65.797 ;
     RECT  91.5 57.635 94.512 66.131 ;
     RECT  78 65.797 78.456 67.859 ;
     RECT  78 67.859 78.312 68.149 ;
     RECT  91.5 66.131 92.712 70.069 ;
     RECT  94.032 66.131 94.512 70.069 ;
     RECT  77.904 68.149 78.312 70.547 ;
     RECT  76.752 70.645 76.776 72.995 ;
     RECT  21.3 2.151 21.612 75.157 ;
     RECT  64.5 65.701 65.784 75.445 ;
     RECT  67.2 2.151 67.512 75.445 ;
     RECT  76.896 73.285 76.92 75.445 ;
     RECT  76.608 75.445 76.92 75.491 ;
     RECT  38.976 54.517 39 75.875 ;
     RECT  3.984 74.053 4.008 75.923 ;
     RECT  7.392 44.099 8.112 76.933 ;
     RECT  83.4 2.151 83.712 77.941 ;
     RECT  64.5 75.445 67.512 78.707 ;
     RECT  5.1 40.067 5.412 79.045 ;
     RECT  4.464 79.045 5.412 79.717 ;
     RECT  7.152 76.933 8.112 79.763 ;
     RECT  4.464 79.717 6.12 80.147 ;
     RECT  91.5 70.069 94.512 80.149 ;
     RECT  95.856 80.101 95.88 80.149 ;
     RECT  91.5 80.149 95.88 80.341 ;
     RECT  91.5 80.341 95.928 80.629 ;
     RECT  86.1 2.151 86.412 82.213 ;
     RECT  91.5 80.629 95.976 82.547 ;
     RECT  42.528 64.837 43.32 82.645 ;
     RECT  85.488 82.213 86.412 82.691 ;
     RECT  88.8 56.531 89.208 82.979 ;
     RECT  91.5 82.547 95.16 82.979 ;
     RECT  42.48 82.645 43.32 83.173 ;
     RECT  96.288 82.645 96.312 83.267 ;
     RECT  42.384 83.173 43.32 83.557 ;
     RECT  91.5 82.979 94.512 83.557 ;
     RECT  48.3 2.151 48.612 83.653 ;
     RECT  64.5 78.707 64.968 83.653 ;
     RECT  37.5 2.151 37.812 83.749 ;
     RECT  38.928 76.069 38.952 83.749 ;
     RECT  66.384 78.707 67.512 83.795 ;
     RECT  53.7 2.151 54.012 84.037 ;
     RECT  88.8 82.979 89.112 84.037 ;
     RECT  66.72 83.795 67.512 84.083 ;
     RECT  37.5 83.749 38.952 84.085 ;
     RECT  40.2 61.139 40.512 84.085 ;
     RECT  48.3 83.653 49.08 84.131 ;
     RECT  82.896 77.941 83.712 84.131 ;
     RECT  53.7 84.037 54.744 84.179 ;
     RECT  41.76 83.557 43.32 84.371 ;
     RECT  76.608 75.491 76.632 84.371 ;
     RECT  95.712 83.653 95.736 84.419 ;
     RECT  88.8 84.037 89.208 84.565 ;
     RECT  7.8 79.763 8.112 84.901 ;
     RECT  7.68 84.901 8.112 85.619 ;
     RECT  88.8 84.565 89.496 85.667 ;
     RECT  91.344 83.557 94.512 86.533 ;
     RECT  90.912 86.533 94.632 86.675 ;
     RECT  2.4 45.011 2.712 86.677 ;
     RECT  7.8 85.619 8.112 86.725 ;
     RECT  2.256 86.677 2.712 86.819 ;
     RECT  2.4 86.819 2.712 87.157 ;
     RECT  7.68 86.725 8.112 87.299 ;
     RECT  5.1 80.147 6.12 87.301 ;
     RECT  93.36 86.675 94.512 87.685 ;
     RECT  93.312 87.685 94.512 87.733 ;
     RECT  4.56 87.301 6.12 87.827 ;
     RECT  93.312 87.733 94.632 87.875 ;
     RECT  2.4 87.157 3.432 87.925 ;
     RECT  2.304 87.925 3.432 88.115 ;
     RECT  4.56 87.827 5.544 88.403 ;
     RECT  90.912 86.675 91.812 88.403 ;
     RECT  4.56 88.403 5.412 88.931 ;
     RECT  93.312 87.875 94.512 89.555 ;
     RECT  37.5 84.085 40.512 95.123 ;
     RECT  40.08 95.123 40.512 95.557 ;
     RECT  41.76 84.371 43.212 95.557 ;
     RECT  93.504 89.555 94.512 96.277 ;
     RECT  93.504 96.277 94.728 96.371 ;
     RECT  37.5 95.123 38.952 96.947 ;
     RECT  95.76 96.037 95.784 96.947 ;
     RECT  91.392 88.403 91.812 97.429 ;
     RECT  37.5 96.947 38.472 97.621 ;
     RECT  94.2 96.371 94.728 97.669 ;
     RECT  88.8 85.667 89.208 98.099 ;
     RECT  90.576 97.429 91.812 98.483 ;
     RECT  91.344 98.483 91.812 98.581 ;
     RECT  91.344 98.581 92.76 98.675 ;
     RECT  96.288 97.477 96.312 98.675 ;
     RECT  94.2 97.669 95.016 98.773 ;
     RECT  91.5 98.675 92.76 99.203 ;
     RECT  88.8 98.099 89.112 99.685 ;
     RECT  94.2 98.773 95.784 99.827 ;
     RECT  91.5 99.203 91.812 100.837 ;
     RECT  96.192 100.069 96.312 100.931 ;
     RECT  96.192 100.931 96.264 101.027 ;
     RECT  94.2 99.827 95.112 101.171 ;
     RECT  96.192 101.027 96.216 101.507 ;
     RECT  40.08 95.557 43.212 104.339 ;
     RECT  64.5 83.653 65.256 105.491 ;
     RECT  40.08 104.339 40.512 106.885 ;
     RECT  91.392 100.837 91.812 107.027 ;
     RECT  88.8 99.685 89.208 107.125 ;
     RECT  64.5 105.491 64.968 107.795 ;
     RECT  61.8 2.151 62.112 108.085 ;
     RECT  41.76 104.339 43.212 108.517 ;
     RECT  41.76 108.517 43.32 114.035 ;
     RECT  39.6 106.885 40.512 114.517 ;
     RECT  37.392 97.621 38.472 115.573 ;
     RECT  88.8 107.125 89.256 116.389 ;
     RECT  86.1 82.691 86.412 116.821 ;
     RECT  88.8 116.389 89.448 116.821 ;
     RECT  36.144 117.829 36.168 118.549 ;
     RECT  36.144 118.549 36.264 118.595 ;
     RECT  6.768 118.501 6.792 119.219 ;
     RECT  5.1 88.931 5.412 119.605 ;
     RECT  21.3 75.157 22.488 119.747 ;
     RECT  39.6 114.517 41.016 120.037 ;
     RECT  7.8 87.299 8.112 120.181 ;
     RECT  7.68 120.181 8.112 120.229 ;
     RECT  36.24 118.595 36.264 120.229 ;
     RECT  7.68 120.229 8.232 120.757 ;
     RECT  6.864 120.757 8.232 120.899 ;
     RECT  4.992 119.605 5.412 120.997 ;
     RECT  37.248 115.573 38.472 121.091 ;
     RECT  56.4 2.151 56.712 121.285 ;
     RECT  39.456 120.037 41.016 121.381 ;
     RECT  56.4 121.285 57 121.429 ;
     RECT  6.864 120.899 8.112 121.475 ;
     RECT  4.992 120.997 5.736 121.523 ;
     RECT  24 2.151 24.312 121.525 ;
     RECT  36.144 120.229 36.264 121.571 ;
     RECT  72.6 2.151 72.912 121.573 ;
     RECT  56.304 121.429 57 121.619 ;
     RECT  4.992 121.523 5.412 121.667 ;
     RECT  23.904 121.525 24.312 121.667 ;
     RECT  37.344 121.091 38.472 121.669 ;
     RECT  39.456 121.381 41.4 121.669 ;
     RECT  42.528 114.035 43.32 121.717 ;
     RECT  2.4 88.115 2.712 122.149 ;
     RECT  7.68 121.475 8.112 122.245 ;
     RECT  34.8 2.151 35.112 122.245 ;
     RECT  36.144 121.571 36.168 122.245 ;
     RECT  2.256 122.149 2.712 122.291 ;
     RECT  5.1 121.667 5.412 122.485 ;
     RECT  3.936 121.525 3.96 122.579 ;
     RECT  37.344 121.669 41.4 122.579 ;
     RECT  37.344 122.579 41.016 123.155 ;
     RECT  39.456 123.155 41.016 123.829 ;
     RECT  42.432 121.717 43.32 124.261 ;
     RECT  95.808 124.405 95.832 124.645 ;
     RECT  88.8 116.821 89.496 124.789 ;
     RECT  72.6 121.573 73.8 124.883 ;
     RECT  95.76 124.645 95.832 125.269 ;
     RECT  94.2 101.171 94.512 125.365 ;
     RECT  42.144 124.261 43.32 125.413 ;
     RECT  95.76 125.269 96.312 125.413 ;
     RECT  88.8 124.789 89.784 125.941 ;
     RECT  39.456 123.829 41.064 126.035 ;
     RECT  95.712 125.413 96.312 126.085 ;
     RECT  88.8 125.941 90.408 126.227 ;
     RECT  75.3 48.227 75.612 126.421 ;
     RECT  95.616 126.085 96.312 126.611 ;
     RECT  93.792 125.365 94.512 126.755 ;
     RECT  75.3 126.421 76.056 126.803 ;
     RECT  37.344 123.155 38.472 127.045 ;
     RECT  61.8 108.085 63.096 127.091 ;
     RECT  88.8 126.227 89.448 127.235 ;
     RECT  56.4 121.619 57 127.283 ;
     RECT  39.456 126.035 40.92 127.381 ;
     RECT  95.664 126.611 95.736 127.573 ;
     RECT  34.8 122.245 36.168 127.621 ;
     RECT  91.5 107.027 91.812 127.621 ;
     RECT  95.664 127.573 96.312 127.715 ;
     RECT  94.08 126.755 94.512 127.765 ;
     RECT  93.408 127.765 94.512 127.957 ;
     RECT  78 70.547 78.312 128.053 ;
     RECT  7.68 122.245 8.232 128.291 ;
     RECT  95.712 127.715 96.312 128.291 ;
     RECT  96.192 128.291 96.312 128.339 ;
     RECT  5.1 122.485 6.216 128.579 ;
     RECT  34.8 127.621 36.264 128.867 ;
     RECT  88.8 127.235 89.208 128.867 ;
     RECT  96.192 128.339 96.264 128.867 ;
     RECT  7.8 128.291 8.232 129.155 ;
     RECT  37.248 127.045 38.472 129.251 ;
     RECT  93.408 127.957 94.728 129.251 ;
     RECT  42.096 125.413 43.32 129.397 ;
     RECT  91.5 127.621 92.328 129.443 ;
     RECT  96.24 128.867 96.264 129.443 ;
     RECT  42.048 129.397 43.32 129.491 ;
     RECT  91.5 129.443 91.812 129.925 ;
     RECT  93.408 129.251 94.512 130.357 ;
     RECT  34.8 128.867 35.4 130.501 ;
     RECT  37.344 129.251 38.472 130.501 ;
     RECT  34.368 130.501 35.4 130.595 ;
     RECT  0.144 130.741 0.168 130.883 ;
     RECT  37.056 130.501 38.472 130.981 ;
     RECT  39.456 127.381 41.016 130.981 ;
     RECT  5.1 128.579 5.412 131.077 ;
     RECT  37.056 130.981 41.016 131.123 ;
     RECT  93.168 130.357 94.512 131.123 ;
     RECT  34.368 130.595 35.352 131.555 ;
     RECT  34.8 131.555 35.352 131.605 ;
     RECT  91.008 129.925 91.812 131.699 ;
     RECT  4.272 131.077 5.412 131.891 ;
     RECT  77.472 128.053 78.312 132.275 ;
     RECT  93.168 131.123 93.192 132.275 ;
     RECT  86.1 116.821 86.568 132.277 ;
     RECT  42.048 129.491 43.212 132.323 ;
     RECT  78 132.275 78.312 132.373 ;
     RECT  86.1 132.277 86.664 132.419 ;
     RECT  78 132.373 78.696 132.515 ;
     RECT  42.144 132.323 43.212 132.611 ;
     RECT  34.8 131.605 36.024 133.189 ;
     RECT  37.344 131.123 41.016 133.189 ;
     RECT  34.8 133.189 41.016 133.235 ;
     RECT  86.1 132.419 86.568 133.429 ;
     RECT  88.8 128.867 89.112 134.005 ;
     RECT  42.576 132.611 43.212 134.147 ;
     RECT  34.8 133.235 38.472 135.683 ;
     RECT  36.672 135.683 38.472 136.931 ;
     RECT  37.344 136.931 38.472 137.893 ;
     RECT  91.5 131.699 91.812 138.037 ;
     RECT  95.856 137.893 95.88 138.181 ;
     RECT  94.2 131.123 94.512 138.229 ;
     RECT  95.808 138.181 95.88 138.229 ;
     RECT  94.2 138.229 95.88 138.901 ;
     RECT  86.1 133.429 86.904 138.997 ;
     RECT  88.032 134.005 89.112 138.997 ;
     RECT  86.1 138.997 89.112 139.139 ;
     RECT  90.576 138.037 91.812 139.139 ;
     RECT  94.032 138.901 95.88 139.427 ;
     RECT  94.032 139.427 95.544 140.003 ;
     RECT  95.52 140.003 95.544 140.147 ;
     RECT  91.5 139.139 91.812 140.197 ;
     RECT  94.032 140.003 94.512 140.197 ;
     RECT  91.008 140.197 91.812 140.725 ;
     RECT  86.1 139.139 87.768 140.819 ;
     RECT  93.84 140.197 94.512 140.819 ;
     RECT  37.2 137.893 38.472 141.299 ;
     RECT  91.008 140.725 92.376 141.395 ;
     RECT  86.1 140.819 86.904 141.539 ;
     RECT  96.288 141.397 96.312 141.685 ;
     RECT  96.24 141.685 96.312 141.829 ;
     RECT  94.2 140.819 94.512 141.877 ;
     RECT  95.712 141.829 96.312 141.877 ;
     RECT  94.2 141.877 96.312 142.261 ;
     RECT  88.8 139.139 89.112 142.453 ;
     RECT  39.456 133.235 41.016 142.547 ;
     RECT  91.5 141.395 92.376 142.595 ;
     RECT  91.5 142.595 92.328 142.739 ;
     RECT  93.456 142.261 96.312 142.787 ;
     RECT  91.5 142.739 91.812 142.789 ;
     RECT  21.3 119.747 22.104 142.979 ;
     RECT  88.8 142.453 89.832 143.123 ;
     RECT  94.08 142.787 96.312 143.123 ;
     RECT  94.08 143.123 95.064 143.171 ;
     RECT  91.392 142.789 91.812 143.555 ;
     RECT  96.192 143.123 96.312 143.699 ;
     RECT  37.248 141.299 38.472 143.701 ;
     RECT  39.456 142.547 40.92 143.701 ;
     RECT  94.08 143.171 94.776 143.845 ;
     RECT  96.24 143.699 96.312 144.275 ;
     RECT  93.936 143.845 94.776 144.323 ;
     RECT  96.24 144.275 96.264 144.371 ;
     RECT  93.936 144.323 94.512 144.563 ;
     RECT  37.248 143.701 40.92 147.155 ;
     RECT  37.248 147.155 40.512 148.211 ;
     RECT  37.392 148.211 40.512 149.363 ;
     RECT  37.392 149.363 39.144 150.997 ;
     RECT  37.392 150.997 39.192 163.043 ;
     RECT  37.392 163.043 38.472 165.923 ;
     RECT  2.4 122.291 2.712 168.489 ;
     RECT  5.1 131.891 5.412 168.489 ;
     RECT  7.8 129.155 8.112 168.489 ;
     RECT  10.5 2.151 10.812 168.489 ;
     RECT  13.2 41.459 13.512 168.489 ;
     RECT  15.9 2.151 16.212 168.489 ;
     RECT  18.6 2.151 18.912 168.489 ;
     RECT  21.3 142.979 21.612 168.489 ;
     RECT  24 121.667 24.312 168.489 ;
     RECT  26.7 2.151 27.012 168.489 ;
     RECT  29.4 2.151 29.712 168.489 ;
     RECT  32.1 2.151 32.412 168.489 ;
     RECT  34.8 135.683 35.112 168.489 ;
     RECT  40.2 149.363 40.512 168.489 ;
     RECT  42.9 134.147 43.212 168.489 ;
     RECT  45.6 2.151 45.912 168.489 ;
     RECT  48.3 84.131 48.612 168.489 ;
     RECT  51 2.151 51.312 168.489 ;
     RECT  53.7 84.179 54.012 168.489 ;
     RECT  56.4 127.283 56.712 168.489 ;
     RECT  59.1 2.151 59.412 168.489 ;
     RECT  61.8 127.091 62.112 168.489 ;
     RECT  64.5 107.795 64.812 168.489 ;
     RECT  67.2 84.083 67.512 168.489 ;
     RECT  69.9 2.151 70.212 168.489 ;
     RECT  72.6 124.883 72.912 168.489 ;
     RECT  75.3 126.803 75.612 168.489 ;
     RECT  78 132.515 78.312 168.489 ;
     RECT  80.7 47.363 81.012 168.489 ;
     RECT  83.4 84.131 83.712 168.489 ;
     RECT  86.1 141.539 86.412 168.489 ;
     RECT  88.8 143.123 89.112 168.489 ;
     RECT  91.5 143.555 91.812 168.489 ;
     RECT  94.2 144.563 94.512 168.489 ;
     RECT  2.4 168.489 2.52 168.503 ;
     RECT  5.1 168.489 5.22 168.503 ;
     RECT  7.8 168.489 7.92 168.503 ;
     RECT  10.5 168.489 10.62 168.503 ;
     RECT  13.2 168.489 13.32 168.503 ;
     RECT  15.9 168.489 16.02 168.503 ;
     RECT  18.6 168.489 18.72 168.503 ;
     RECT  21.3 168.489 21.42 168.503 ;
     RECT  24 168.489 24.12 168.503 ;
     RECT  26.7 168.489 26.82 168.503 ;
     RECT  29.4 168.489 29.52 168.503 ;
     RECT  32.1 168.489 32.22 168.503 ;
     RECT  34.8 168.489 34.92 168.503 ;
     RECT  37.5 165.923 38.136 168.503 ;
     RECT  40.2 168.489 40.32 168.503 ;
     RECT  42.9 168.489 43.02 168.503 ;
     RECT  45.6 168.489 45.72 168.503 ;
     RECT  48.3 168.489 48.42 168.503 ;
     RECT  51 168.489 51.12 168.503 ;
     RECT  53.7 168.489 53.82 168.503 ;
     RECT  56.4 168.489 56.52 168.503 ;
     RECT  59.1 168.489 59.22 168.503 ;
     RECT  61.8 168.489 61.92 168.503 ;
     RECT  64.5 168.489 64.62 168.503 ;
     RECT  67.2 168.489 67.32 168.503 ;
     RECT  69.9 168.489 70.02 168.503 ;
     RECT  72.6 168.489 72.72 168.503 ;
     RECT  75.3 168.489 75.42 168.503 ;
     RECT  78 168.489 78.12 168.503 ;
     RECT  80.7 168.489 80.82 168.503 ;
     RECT  83.4 168.489 83.52 168.503 ;
     RECT  86.1 168.489 86.22 168.503 ;
     RECT  88.8 168.489 88.92 168.503 ;
     RECT  91.5 168.489 91.62 168.503 ;
     RECT  94.2 168.489 94.32 168.503 ;
     RECT  37.968 168.503 38.136 170.435 ;
     RECT  37.968 170.435 37.992 170.531 ;
  END
END qfd_landh0d8s_182_EW_98x171
END LIBRARY
